VERSION 5.8 ;
BUSBITCHARS "[]" ;
DIVIDERCHAR "/" ;
UNITS
    DATABASE MICRONS 1000 ;
END UNITS

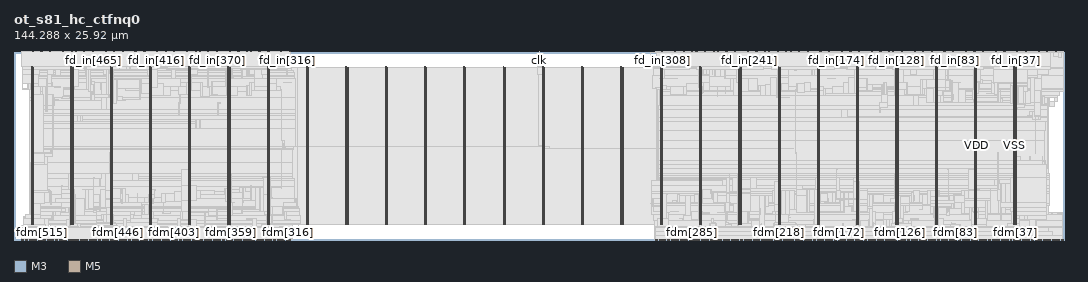
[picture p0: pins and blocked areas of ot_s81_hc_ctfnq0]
MACRO ot_s81_hc_ctfnq0
  FOREIGN ot_s81_hc_ctfnq0 0 0 ;
  CLASS BLOCK ;
  SIZE 144.288 BY 25.92 ;
  PIN clk
    DIRECTION INPUT ;
    USE SIGNAL ;
    PORT
      LAYER M3 ;
        RECT  72.144 25.882 72.162 25.92 ;
    END
  END clk
  PIN fd_in[0]
    DIRECTION INPUT ;
    USE SIGNAL ;
    PORT
      LAYER M5 ;
        RECT  144.24 25.836 144.264 25.92 ;
    END
  END fd_in[0]
  PIN fd_in[100]
    DIRECTION INPUT ;
    USE SIGNAL ;
    PORT
      LAYER M5 ;
        RECT  126.336 25.836 126.36 25.92 ;
    END
  END fd_in[100]
  PIN fd_in[101]
    DIRECTION INPUT ;
    USE SIGNAL ;
    PORT
      LAYER M5 ;
        RECT  126.144 25.836 126.168 25.92 ;
    END
  END fd_in[101]
  PIN fd_in[102]
    DIRECTION INPUT ;
    USE SIGNAL ;
    PORT
      LAYER M5 ;
        RECT  125.952 25.836 125.976 25.92 ;
    END
  END fd_in[102]
  PIN fd_in[103]
    DIRECTION INPUT ;
    USE SIGNAL ;
    PORT
      LAYER M5 ;
        RECT  125.808 25.836 125.832 25.92 ;
    END
  END fd_in[103]
  PIN fd_in[104]
    DIRECTION INPUT ;
    USE SIGNAL ;
    PORT
      LAYER M5 ;
        RECT  125.616 25.836 125.64 25.92 ;
    END
  END fd_in[104]
  PIN fd_in[105]
    DIRECTION INPUT ;
    USE SIGNAL ;
    PORT
      LAYER M5 ;
        RECT  125.424 25.836 125.448 25.92 ;
    END
  END fd_in[105]
  PIN fd_in[106]
    DIRECTION INPUT ;
    USE SIGNAL ;
    PORT
      LAYER M5 ;
        RECT  125.232 25.836 125.256 25.92 ;
    END
  END fd_in[106]
  PIN fd_in[107]
    DIRECTION INPUT ;
    USE SIGNAL ;
    PORT
      LAYER M5 ;
        RECT  125.088 25.836 125.112 25.92 ;
    END
  END fd_in[107]
  PIN fd_in[108]
    DIRECTION INPUT ;
    USE SIGNAL ;
    PORT
      LAYER M5 ;
        RECT  124.896 25.836 124.92 25.92 ;
    END
  END fd_in[108]
  PIN fd_in[109]
    DIRECTION INPUT ;
    USE SIGNAL ;
    PORT
      LAYER M5 ;
        RECT  124.704 25.836 124.728 25.92 ;
    END
  END fd_in[109]
  PIN fd_in[10]
    DIRECTION INPUT ;
    USE SIGNAL ;
    PORT
      LAYER M5 ;
        RECT  142.464 25.836 142.488 25.92 ;
    END
  END fd_in[10]
  PIN fd_in[110]
    DIRECTION INPUT ;
    USE SIGNAL ;
    PORT
      LAYER M5 ;
        RECT  124.512 25.836 124.536 25.92 ;
    END
  END fd_in[110]
  PIN fd_in[111]
    DIRECTION INPUT ;
    USE SIGNAL ;
    PORT
      LAYER M5 ;
        RECT  124.368 25.836 124.392 25.92 ;
    END
  END fd_in[111]
  PIN fd_in[112]
    DIRECTION INPUT ;
    USE SIGNAL ;
    PORT
      LAYER M5 ;
        RECT  124.176 25.836 124.2 25.92 ;
    END
  END fd_in[112]
  PIN fd_in[113]
    DIRECTION INPUT ;
    USE SIGNAL ;
    PORT
      LAYER M5 ;
        RECT  123.984 25.836 124.008 25.92 ;
    END
  END fd_in[113]
  PIN fd_in[114]
    DIRECTION INPUT ;
    USE SIGNAL ;
    PORT
      LAYER M5 ;
        RECT  123.792 25.836 123.816 25.92 ;
    END
  END fd_in[114]
  PIN fd_in[115]
    DIRECTION INPUT ;
    USE SIGNAL ;
    PORT
      LAYER M5 ;
        RECT  123.648 25.836 123.672 25.92 ;
    END
  END fd_in[115]
  PIN fd_in[116]
    DIRECTION INPUT ;
    USE SIGNAL ;
    PORT
      LAYER M5 ;
        RECT  123.456 25.836 123.48 25.92 ;
    END
  END fd_in[116]
  PIN fd_in[117]
    DIRECTION INPUT ;
    USE SIGNAL ;
    PORT
      LAYER M5 ;
        RECT  123.264 25.836 123.288 25.92 ;
    END
  END fd_in[117]
  PIN fd_in[118]
    DIRECTION INPUT ;
    USE SIGNAL ;
    PORT
      LAYER M5 ;
        RECT  123.072 25.836 123.096 25.92 ;
    END
  END fd_in[118]
  PIN fd_in[119]
    DIRECTION INPUT ;
    USE SIGNAL ;
    PORT
      LAYER M5 ;
        RECT  122.928 25.836 122.952 25.92 ;
    END
  END fd_in[119]
  PIN fd_in[11]
    DIRECTION INPUT ;
    USE SIGNAL ;
    PORT
      LAYER M5 ;
        RECT  142.272 25.836 142.296 25.92 ;
    END
  END fd_in[11]
  PIN fd_in[120]
    DIRECTION INPUT ;
    USE SIGNAL ;
    PORT
      LAYER M5 ;
        RECT  122.736 25.836 122.76 25.92 ;
    END
  END fd_in[120]
  PIN fd_in[121]
    DIRECTION INPUT ;
    USE SIGNAL ;
    PORT
      LAYER M5 ;
        RECT  122.544 25.836 122.568 25.92 ;
    END
  END fd_in[121]
  PIN fd_in[122]
    DIRECTION INPUT ;
    USE SIGNAL ;
    PORT
      LAYER M5 ;
        RECT  122.4 25.836 122.424 25.92 ;
    END
  END fd_in[122]
  PIN fd_in[123]
    DIRECTION INPUT ;
    USE SIGNAL ;
    PORT
      LAYER M5 ;
        RECT  122.208 25.836 122.232 25.92 ;
    END
  END fd_in[123]
  PIN fd_in[124]
    DIRECTION INPUT ;
    USE SIGNAL ;
    PORT
      LAYER M5 ;
        RECT  122.016 25.836 122.04 25.92 ;
    END
  END fd_in[124]
  PIN fd_in[125]
    DIRECTION INPUT ;
    USE SIGNAL ;
    PORT
      LAYER M5 ;
        RECT  121.824 25.836 121.848 25.92 ;
    END
  END fd_in[125]
  PIN fd_in[126]
    DIRECTION INPUT ;
    USE SIGNAL ;
    PORT
      LAYER M5 ;
        RECT  121.68 25.836 121.704 25.92 ;
    END
  END fd_in[126]
  PIN fd_in[127]
    DIRECTION INPUT ;
    USE SIGNAL ;
    PORT
      LAYER M5 ;
        RECT  121.488 25.836 121.512 25.92 ;
    END
  END fd_in[127]
  PIN fd_in[128]
    DIRECTION INPUT ;
    USE SIGNAL ;
    PORT
      LAYER M5 ;
        RECT  121.296 25.836 121.32 25.92 ;
    END
  END fd_in[128]
  PIN fd_in[129]
    DIRECTION INPUT ;
    USE SIGNAL ;
    PORT
      LAYER M5 ;
        RECT  121.104 25.836 121.128 25.92 ;
    END
  END fd_in[129]
  PIN fd_in[12]
    DIRECTION INPUT ;
    USE SIGNAL ;
    PORT
      LAYER M5 ;
        RECT  142.128 25.836 142.152 25.92 ;
    END
  END fd_in[12]
  PIN fd_in[130]
    DIRECTION INPUT ;
    USE SIGNAL ;
    PORT
      LAYER M5 ;
        RECT  120.96 25.836 120.984 25.92 ;
    END
  END fd_in[130]
  PIN fd_in[131]
    DIRECTION INPUT ;
    USE SIGNAL ;
    PORT
      LAYER M5 ;
        RECT  120.768 25.836 120.792 25.92 ;
    END
  END fd_in[131]
  PIN fd_in[132]
    DIRECTION INPUT ;
    USE SIGNAL ;
    PORT
      LAYER M5 ;
        RECT  120.576 25.836 120.6 25.92 ;
    END
  END fd_in[132]
  PIN fd_in[133]
    DIRECTION INPUT ;
    USE SIGNAL ;
    PORT
      LAYER M5 ;
        RECT  120.384 25.836 120.408 25.92 ;
    END
  END fd_in[133]
  PIN fd_in[134]
    DIRECTION INPUT ;
    USE SIGNAL ;
    PORT
      LAYER M5 ;
        RECT  120.24 25.836 120.264 25.92 ;
    END
  END fd_in[134]
  PIN fd_in[135]
    DIRECTION INPUT ;
    USE SIGNAL ;
    PORT
      LAYER M5 ;
        RECT  120.048 25.836 120.072 25.92 ;
    END
  END fd_in[135]
  PIN fd_in[136]
    DIRECTION INPUT ;
    USE SIGNAL ;
    PORT
      LAYER M5 ;
        RECT  119.856 25.836 119.88 25.92 ;
    END
  END fd_in[136]
  PIN fd_in[137]
    DIRECTION INPUT ;
    USE SIGNAL ;
    PORT
      LAYER M5 ;
        RECT  119.712 25.836 119.736 25.92 ;
    END
  END fd_in[137]
  PIN fd_in[138]
    DIRECTION INPUT ;
    USE SIGNAL ;
    PORT
      LAYER M5 ;
        RECT  119.52 25.836 119.544 25.92 ;
    END
  END fd_in[138]
  PIN fd_in[139]
    DIRECTION INPUT ;
    USE SIGNAL ;
    PORT
      LAYER M5 ;
        RECT  119.328 25.836 119.352 25.92 ;
    END
  END fd_in[139]
  PIN fd_in[13]
    DIRECTION INPUT ;
    USE SIGNAL ;
    PORT
      LAYER M5 ;
        RECT  141.936 25.836 141.96 25.92 ;
    END
  END fd_in[13]
  PIN fd_in[140]
    DIRECTION INPUT ;
    USE SIGNAL ;
    PORT
      LAYER M5 ;
        RECT  119.136 25.836 119.16 25.92 ;
    END
  END fd_in[140]
  PIN fd_in[141]
    DIRECTION INPUT ;
    USE SIGNAL ;
    PORT
      LAYER M5 ;
        RECT  118.992 25.836 119.016 25.92 ;
    END
  END fd_in[141]
  PIN fd_in[142]
    DIRECTION INPUT ;
    USE SIGNAL ;
    PORT
      LAYER M5 ;
        RECT  118.8 25.836 118.824 25.92 ;
    END
  END fd_in[142]
  PIN fd_in[143]
    DIRECTION INPUT ;
    USE SIGNAL ;
    PORT
      LAYER M5 ;
        RECT  118.608 25.836 118.632 25.92 ;
    END
  END fd_in[143]
  PIN fd_in[144]
    DIRECTION INPUT ;
    USE SIGNAL ;
    PORT
      LAYER M5 ;
        RECT  118.416 25.836 118.44 25.92 ;
    END
  END fd_in[144]
  PIN fd_in[145]
    DIRECTION INPUT ;
    USE SIGNAL ;
    PORT
      LAYER M5 ;
        RECT  118.272 25.836 118.296 25.92 ;
    END
  END fd_in[145]
  PIN fd_in[146]
    DIRECTION INPUT ;
    USE SIGNAL ;
    PORT
      LAYER M5 ;
        RECT  118.08 25.836 118.104 25.92 ;
    END
  END fd_in[146]
  PIN fd_in[147]
    DIRECTION INPUT ;
    USE SIGNAL ;
    PORT
      LAYER M5 ;
        RECT  117.888 25.836 117.912 25.92 ;
    END
  END fd_in[147]
  PIN fd_in[148]
    DIRECTION INPUT ;
    USE SIGNAL ;
    PORT
      LAYER M5 ;
        RECT  117.696 25.836 117.72 25.92 ;
    END
  END fd_in[148]
  PIN fd_in[149]
    DIRECTION INPUT ;
    USE SIGNAL ;
    PORT
      LAYER M5 ;
        RECT  117.552 25.836 117.576 25.92 ;
    END
  END fd_in[149]
  PIN fd_in[14]
    DIRECTION INPUT ;
    USE SIGNAL ;
    PORT
      LAYER M5 ;
        RECT  141.744 25.836 141.768 25.92 ;
    END
  END fd_in[14]
  PIN fd_in[150]
    DIRECTION INPUT ;
    USE SIGNAL ;
    PORT
      LAYER M5 ;
        RECT  117.36 25.836 117.384 25.92 ;
    END
  END fd_in[150]
  PIN fd_in[151]
    DIRECTION INPUT ;
    USE SIGNAL ;
    PORT
      LAYER M5 ;
        RECT  117.168 25.836 117.192 25.92 ;
    END
  END fd_in[151]
  PIN fd_in[152]
    DIRECTION INPUT ;
    USE SIGNAL ;
    PORT
      LAYER M5 ;
        RECT  116.976 25.836 117 25.92 ;
    END
  END fd_in[152]
  PIN fd_in[153]
    DIRECTION INPUT ;
    USE SIGNAL ;
    PORT
      LAYER M5 ;
        RECT  116.832 25.836 116.856 25.92 ;
    END
  END fd_in[153]
  PIN fd_in[154]
    DIRECTION INPUT ;
    USE SIGNAL ;
    PORT
      LAYER M5 ;
        RECT  116.64 25.836 116.664 25.92 ;
    END
  END fd_in[154]
  PIN fd_in[155]
    DIRECTION INPUT ;
    USE SIGNAL ;
    PORT
      LAYER M5 ;
        RECT  116.448 25.836 116.472 25.92 ;
    END
  END fd_in[155]
  PIN fd_in[156]
    DIRECTION INPUT ;
    USE SIGNAL ;
    PORT
      LAYER M5 ;
        RECT  116.304 25.836 116.328 25.92 ;
    END
  END fd_in[156]
  PIN fd_in[157]
    DIRECTION INPUT ;
    USE SIGNAL ;
    PORT
      LAYER M5 ;
        RECT  116.112 25.836 116.136 25.92 ;
    END
  END fd_in[157]
  PIN fd_in[158]
    DIRECTION INPUT ;
    USE SIGNAL ;
    PORT
      LAYER M5 ;
        RECT  115.92 25.836 115.944 25.92 ;
    END
  END fd_in[158]
  PIN fd_in[159]
    DIRECTION INPUT ;
    USE SIGNAL ;
    PORT
      LAYER M5 ;
        RECT  115.728 25.836 115.752 25.92 ;
    END
  END fd_in[159]
  PIN fd_in[15]
    DIRECTION INPUT ;
    USE SIGNAL ;
    PORT
      LAYER M5 ;
        RECT  141.552 25.836 141.576 25.92 ;
    END
  END fd_in[15]
  PIN fd_in[160]
    DIRECTION INPUT ;
    USE SIGNAL ;
    PORT
      LAYER M5 ;
        RECT  115.584 25.836 115.608 25.92 ;
    END
  END fd_in[160]
  PIN fd_in[161]
    DIRECTION INPUT ;
    USE SIGNAL ;
    PORT
      LAYER M5 ;
        RECT  115.392 25.836 115.416 25.92 ;
    END
  END fd_in[161]
  PIN fd_in[162]
    DIRECTION INPUT ;
    USE SIGNAL ;
    PORT
      LAYER M5 ;
        RECT  115.2 25.836 115.224 25.92 ;
    END
  END fd_in[162]
  PIN fd_in[163]
    DIRECTION INPUT ;
    USE SIGNAL ;
    PORT
      LAYER M5 ;
        RECT  115.008 25.836 115.032 25.92 ;
    END
  END fd_in[163]
  PIN fd_in[164]
    DIRECTION INPUT ;
    USE SIGNAL ;
    PORT
      LAYER M5 ;
        RECT  114.864 25.836 114.888 25.92 ;
    END
  END fd_in[164]
  PIN fd_in[165]
    DIRECTION INPUT ;
    USE SIGNAL ;
    PORT
      LAYER M5 ;
        RECT  114.672 25.836 114.696 25.92 ;
    END
  END fd_in[165]
  PIN fd_in[166]
    DIRECTION INPUT ;
    USE SIGNAL ;
    PORT
      LAYER M5 ;
        RECT  114.48 25.836 114.504 25.92 ;
    END
  END fd_in[166]
  PIN fd_in[167]
    DIRECTION INPUT ;
    USE SIGNAL ;
    PORT
      LAYER M5 ;
        RECT  114.288 25.836 114.312 25.92 ;
    END
  END fd_in[167]
  PIN fd_in[168]
    DIRECTION INPUT ;
    USE SIGNAL ;
    PORT
      LAYER M5 ;
        RECT  114.144 25.836 114.168 25.92 ;
    END
  END fd_in[168]
  PIN fd_in[169]
    DIRECTION INPUT ;
    USE SIGNAL ;
    PORT
      LAYER M5 ;
        RECT  113.952 25.836 113.976 25.92 ;
    END
  END fd_in[169]
  PIN fd_in[16]
    DIRECTION INPUT ;
    USE SIGNAL ;
    PORT
      LAYER M5 ;
        RECT  141.408 25.836 141.432 25.92 ;
    END
  END fd_in[16]
  PIN fd_in[170]
    DIRECTION INPUT ;
    USE SIGNAL ;
    PORT
      LAYER M5 ;
        RECT  113.76 25.836 113.784 25.92 ;
    END
  END fd_in[170]
  PIN fd_in[171]
    DIRECTION INPUT ;
    USE SIGNAL ;
    PORT
      LAYER M5 ;
        RECT  113.568 25.836 113.592 25.92 ;
    END
  END fd_in[171]
  PIN fd_in[172]
    DIRECTION INPUT ;
    USE SIGNAL ;
    PORT
      LAYER M5 ;
        RECT  113.424 25.836 113.448 25.92 ;
    END
  END fd_in[172]
  PIN fd_in[173]
    DIRECTION INPUT ;
    USE SIGNAL ;
    PORT
      LAYER M5 ;
        RECT  113.232 25.836 113.256 25.92 ;
    END
  END fd_in[173]
  PIN fd_in[174]
    DIRECTION INPUT ;
    USE SIGNAL ;
    PORT
      LAYER M5 ;
        RECT  113.04 25.836 113.064 25.92 ;
    END
  END fd_in[174]
  PIN fd_in[175]
    DIRECTION INPUT ;
    USE SIGNAL ;
    PORT
      LAYER M5 ;
        RECT  112.896 25.836 112.92 25.92 ;
    END
  END fd_in[175]
  PIN fd_in[176]
    DIRECTION INPUT ;
    USE SIGNAL ;
    PORT
      LAYER M5 ;
        RECT  112.704 25.836 112.728 25.92 ;
    END
  END fd_in[176]
  PIN fd_in[177]
    DIRECTION INPUT ;
    USE SIGNAL ;
    PORT
      LAYER M5 ;
        RECT  112.512 25.836 112.536 25.92 ;
    END
  END fd_in[177]
  PIN fd_in[178]
    DIRECTION INPUT ;
    USE SIGNAL ;
    PORT
      LAYER M5 ;
        RECT  112.32 25.836 112.344 25.92 ;
    END
  END fd_in[178]
  PIN fd_in[179]
    DIRECTION INPUT ;
    USE SIGNAL ;
    PORT
      LAYER M5 ;
        RECT  112.176 25.836 112.2 25.92 ;
    END
  END fd_in[179]
  PIN fd_in[17]
    DIRECTION INPUT ;
    USE SIGNAL ;
    PORT
      LAYER M5 ;
        RECT  141.216 25.836 141.24 25.92 ;
    END
  END fd_in[17]
  PIN fd_in[180]
    DIRECTION INPUT ;
    USE SIGNAL ;
    PORT
      LAYER M5 ;
        RECT  111.984 25.836 112.008 25.92 ;
    END
  END fd_in[180]
  PIN fd_in[181]
    DIRECTION INPUT ;
    USE SIGNAL ;
    PORT
      LAYER M5 ;
        RECT  111.792 25.836 111.816 25.92 ;
    END
  END fd_in[181]
  PIN fd_in[182]
    DIRECTION INPUT ;
    USE SIGNAL ;
    PORT
      LAYER M5 ;
        RECT  111.6 25.836 111.624 25.92 ;
    END
  END fd_in[182]
  PIN fd_in[183]
    DIRECTION INPUT ;
    USE SIGNAL ;
    PORT
      LAYER M5 ;
        RECT  111.456 25.836 111.48 25.92 ;
    END
  END fd_in[183]
  PIN fd_in[184]
    DIRECTION INPUT ;
    USE SIGNAL ;
    PORT
      LAYER M5 ;
        RECT  111.264 25.836 111.288 25.92 ;
    END
  END fd_in[184]
  PIN fd_in[185]
    DIRECTION INPUT ;
    USE SIGNAL ;
    PORT
      LAYER M5 ;
        RECT  111.072 25.836 111.096 25.92 ;
    END
  END fd_in[185]
  PIN fd_in[186]
    DIRECTION INPUT ;
    USE SIGNAL ;
    PORT
      LAYER M5 ;
        RECT  110.88 25.836 110.904 25.92 ;
    END
  END fd_in[186]
  PIN fd_in[187]
    DIRECTION INPUT ;
    USE SIGNAL ;
    PORT
      LAYER M5 ;
        RECT  110.736 25.836 110.76 25.92 ;
    END
  END fd_in[187]
  PIN fd_in[188]
    DIRECTION INPUT ;
    USE SIGNAL ;
    PORT
      LAYER M5 ;
        RECT  110.544 25.836 110.568 25.92 ;
    END
  END fd_in[188]
  PIN fd_in[189]
    DIRECTION INPUT ;
    USE SIGNAL ;
    PORT
      LAYER M5 ;
        RECT  110.352 25.836 110.376 25.92 ;
    END
  END fd_in[189]
  PIN fd_in[18]
    DIRECTION INPUT ;
    USE SIGNAL ;
    PORT
      LAYER M5 ;
        RECT  141.024 25.836 141.048 25.92 ;
    END
  END fd_in[18]
  PIN fd_in[190]
    DIRECTION INPUT ;
    USE SIGNAL ;
    PORT
      LAYER M5 ;
        RECT  110.16 25.836 110.184 25.92 ;
    END
  END fd_in[190]
  PIN fd_in[191]
    DIRECTION INPUT ;
    USE SIGNAL ;
    PORT
      LAYER M5 ;
        RECT  110.016 25.836 110.04 25.92 ;
    END
  END fd_in[191]
  PIN fd_in[192]
    DIRECTION INPUT ;
    USE SIGNAL ;
    PORT
      LAYER M5 ;
        RECT  109.824 25.836 109.848 25.92 ;
    END
  END fd_in[192]
  PIN fd_in[193]
    DIRECTION INPUT ;
    USE SIGNAL ;
    PORT
      LAYER M5 ;
        RECT  109.632 25.836 109.656 25.92 ;
    END
  END fd_in[193]
  PIN fd_in[194]
    DIRECTION INPUT ;
    USE SIGNAL ;
    PORT
      LAYER M5 ;
        RECT  109.488 25.836 109.512 25.92 ;
    END
  END fd_in[194]
  PIN fd_in[195]
    DIRECTION INPUT ;
    USE SIGNAL ;
    PORT
      LAYER M5 ;
        RECT  109.296 25.836 109.32 25.92 ;
    END
  END fd_in[195]
  PIN fd_in[196]
    DIRECTION INPUT ;
    USE SIGNAL ;
    PORT
      LAYER M5 ;
        RECT  109.104 25.836 109.128 25.92 ;
    END
  END fd_in[196]
  PIN fd_in[197]
    DIRECTION INPUT ;
    USE SIGNAL ;
    PORT
      LAYER M5 ;
        RECT  108.912 25.836 108.936 25.92 ;
    END
  END fd_in[197]
  PIN fd_in[198]
    DIRECTION INPUT ;
    USE SIGNAL ;
    PORT
      LAYER M5 ;
        RECT  108.768 25.836 108.792 25.92 ;
    END
  END fd_in[198]
  PIN fd_in[199]
    DIRECTION INPUT ;
    USE SIGNAL ;
    PORT
      LAYER M5 ;
        RECT  108.576 25.836 108.6 25.92 ;
    END
  END fd_in[199]
  PIN fd_in[19]
    DIRECTION INPUT ;
    USE SIGNAL ;
    PORT
      LAYER M5 ;
        RECT  140.832 25.836 140.856 25.92 ;
    END
  END fd_in[19]
  PIN fd_in[1]
    DIRECTION INPUT ;
    USE SIGNAL ;
    PORT
      LAYER M5 ;
        RECT  144.096 25.836 144.12 25.92 ;
    END
  END fd_in[1]
  PIN fd_in[200]
    DIRECTION INPUT ;
    USE SIGNAL ;
    PORT
      LAYER M5 ;
        RECT  108.384 25.836 108.408 25.92 ;
    END
  END fd_in[200]
  PIN fd_in[201]
    DIRECTION INPUT ;
    USE SIGNAL ;
    PORT
      LAYER M5 ;
        RECT  108.192 25.836 108.216 25.92 ;
    END
  END fd_in[201]
  PIN fd_in[202]
    DIRECTION INPUT ;
    USE SIGNAL ;
    PORT
      LAYER M5 ;
        RECT  108.048 25.836 108.072 25.92 ;
    END
  END fd_in[202]
  PIN fd_in[203]
    DIRECTION INPUT ;
    USE SIGNAL ;
    PORT
      LAYER M5 ;
        RECT  107.856 25.836 107.88 25.92 ;
    END
  END fd_in[203]
  PIN fd_in[204]
    DIRECTION INPUT ;
    USE SIGNAL ;
    PORT
      LAYER M5 ;
        RECT  107.664 25.836 107.688 25.92 ;
    END
  END fd_in[204]
  PIN fd_in[205]
    DIRECTION INPUT ;
    USE SIGNAL ;
    PORT
      LAYER M5 ;
        RECT  107.472 25.836 107.496 25.92 ;
    END
  END fd_in[205]
  PIN fd_in[206]
    DIRECTION INPUT ;
    USE SIGNAL ;
    PORT
      LAYER M5 ;
        RECT  107.328 25.836 107.352 25.92 ;
    END
  END fd_in[206]
  PIN fd_in[207]
    DIRECTION INPUT ;
    USE SIGNAL ;
    PORT
      LAYER M5 ;
        RECT  107.136 25.836 107.16 25.92 ;
    END
  END fd_in[207]
  PIN fd_in[208]
    DIRECTION INPUT ;
    USE SIGNAL ;
    PORT
      LAYER M5 ;
        RECT  106.944 25.836 106.968 25.92 ;
    END
  END fd_in[208]
  PIN fd_in[209]
    DIRECTION INPUT ;
    USE SIGNAL ;
    PORT
      LAYER M5 ;
        RECT  106.752 25.836 106.776 25.92 ;
    END
  END fd_in[209]
  PIN fd_in[20]
    DIRECTION INPUT ;
    USE SIGNAL ;
    PORT
      LAYER M5 ;
        RECT  140.688 25.836 140.712 25.92 ;
    END
  END fd_in[20]
  PIN fd_in[210]
    DIRECTION INPUT ;
    USE SIGNAL ;
    PORT
      LAYER M5 ;
        RECT  106.608 25.836 106.632 25.92 ;
    END
  END fd_in[210]
  PIN fd_in[211]
    DIRECTION INPUT ;
    USE SIGNAL ;
    PORT
      LAYER M5 ;
        RECT  106.416 25.836 106.44 25.92 ;
    END
  END fd_in[211]
  PIN fd_in[212]
    DIRECTION INPUT ;
    USE SIGNAL ;
    PORT
      LAYER M5 ;
        RECT  106.224 25.836 106.248 25.92 ;
    END
  END fd_in[212]
  PIN fd_in[213]
    DIRECTION INPUT ;
    USE SIGNAL ;
    PORT
      LAYER M5 ;
        RECT  106.08 25.836 106.104 25.92 ;
    END
  END fd_in[213]
  PIN fd_in[214]
    DIRECTION INPUT ;
    USE SIGNAL ;
    PORT
      LAYER M5 ;
        RECT  105.888 25.836 105.912 25.92 ;
    END
  END fd_in[214]
  PIN fd_in[215]
    DIRECTION INPUT ;
    USE SIGNAL ;
    PORT
      LAYER M5 ;
        RECT  105.696 25.836 105.72 25.92 ;
    END
  END fd_in[215]
  PIN fd_in[216]
    DIRECTION INPUT ;
    USE SIGNAL ;
    PORT
      LAYER M5 ;
        RECT  105.504 25.836 105.528 25.92 ;
    END
  END fd_in[216]
  PIN fd_in[217]
    DIRECTION INPUT ;
    USE SIGNAL ;
    PORT
      LAYER M5 ;
        RECT  105.36 25.836 105.384 25.92 ;
    END
  END fd_in[217]
  PIN fd_in[218]
    DIRECTION INPUT ;
    USE SIGNAL ;
    PORT
      LAYER M5 ;
        RECT  105.168 25.836 105.192 25.92 ;
    END
  END fd_in[218]
  PIN fd_in[219]
    DIRECTION INPUT ;
    USE SIGNAL ;
    PORT
      LAYER M5 ;
        RECT  104.976 25.836 105 25.92 ;
    END
  END fd_in[219]
  PIN fd_in[21]
    DIRECTION INPUT ;
    USE SIGNAL ;
    PORT
      LAYER M5 ;
        RECT  140.496 25.836 140.52 25.92 ;
    END
  END fd_in[21]
  PIN fd_in[220]
    DIRECTION INPUT ;
    USE SIGNAL ;
    PORT
      LAYER M5 ;
        RECT  104.784 25.836 104.808 25.92 ;
    END
  END fd_in[220]
  PIN fd_in[221]
    DIRECTION INPUT ;
    USE SIGNAL ;
    PORT
      LAYER M5 ;
        RECT  104.64 25.836 104.664 25.92 ;
    END
  END fd_in[221]
  PIN fd_in[222]
    DIRECTION INPUT ;
    USE SIGNAL ;
    PORT
      LAYER M5 ;
        RECT  104.448 25.836 104.472 25.92 ;
    END
  END fd_in[222]
  PIN fd_in[223]
    DIRECTION INPUT ;
    USE SIGNAL ;
    PORT
      LAYER M5 ;
        RECT  104.256 25.836 104.28 25.92 ;
    END
  END fd_in[223]
  PIN fd_in[224]
    DIRECTION INPUT ;
    USE SIGNAL ;
    PORT
      LAYER M5 ;
        RECT  104.064 25.836 104.088 25.92 ;
    END
  END fd_in[224]
  PIN fd_in[225]
    DIRECTION INPUT ;
    USE SIGNAL ;
    PORT
      LAYER M5 ;
        RECT  103.92 25.836 103.944 25.92 ;
    END
  END fd_in[225]
  PIN fd_in[226]
    DIRECTION INPUT ;
    USE SIGNAL ;
    PORT
      LAYER M5 ;
        RECT  103.728 25.836 103.752 25.92 ;
    END
  END fd_in[226]
  PIN fd_in[227]
    DIRECTION INPUT ;
    USE SIGNAL ;
    PORT
      LAYER M5 ;
        RECT  103.536 25.836 103.56 25.92 ;
    END
  END fd_in[227]
  PIN fd_in[228]
    DIRECTION INPUT ;
    USE SIGNAL ;
    PORT
      LAYER M5 ;
        RECT  103.392 25.836 103.416 25.92 ;
    END
  END fd_in[228]
  PIN fd_in[229]
    DIRECTION INPUT ;
    USE SIGNAL ;
    PORT
      LAYER M5 ;
        RECT  103.2 25.836 103.224 25.92 ;
    END
  END fd_in[229]
  PIN fd_in[22]
    DIRECTION INPUT ;
    USE SIGNAL ;
    PORT
      LAYER M5 ;
        RECT  140.304 25.836 140.328 25.92 ;
    END
  END fd_in[22]
  PIN fd_in[230]
    DIRECTION INPUT ;
    USE SIGNAL ;
    PORT
      LAYER M5 ;
        RECT  103.008 25.836 103.032 25.92 ;
    END
  END fd_in[230]
  PIN fd_in[231]
    DIRECTION INPUT ;
    USE SIGNAL ;
    PORT
      LAYER M5 ;
        RECT  102.816 25.836 102.84 25.92 ;
    END
  END fd_in[231]
  PIN fd_in[232]
    DIRECTION INPUT ;
    USE SIGNAL ;
    PORT
      LAYER M5 ;
        RECT  102.672 25.836 102.696 25.92 ;
    END
  END fd_in[232]
  PIN fd_in[233]
    DIRECTION INPUT ;
    USE SIGNAL ;
    PORT
      LAYER M5 ;
        RECT  102.48 25.836 102.504 25.92 ;
    END
  END fd_in[233]
  PIN fd_in[234]
    DIRECTION INPUT ;
    USE SIGNAL ;
    PORT
      LAYER M5 ;
        RECT  102.288 25.836 102.312 25.92 ;
    END
  END fd_in[234]
  PIN fd_in[235]
    DIRECTION INPUT ;
    USE SIGNAL ;
    PORT
      LAYER M5 ;
        RECT  102.096 25.836 102.12 25.92 ;
    END
  END fd_in[235]
  PIN fd_in[236]
    DIRECTION INPUT ;
    USE SIGNAL ;
    PORT
      LAYER M5 ;
        RECT  101.952 25.836 101.976 25.92 ;
    END
  END fd_in[236]
  PIN fd_in[237]
    DIRECTION INPUT ;
    USE SIGNAL ;
    PORT
      LAYER M5 ;
        RECT  101.76 25.836 101.784 25.92 ;
    END
  END fd_in[237]
  PIN fd_in[238]
    DIRECTION INPUT ;
    USE SIGNAL ;
    PORT
      LAYER M5 ;
        RECT  101.568 25.836 101.592 25.92 ;
    END
  END fd_in[238]
  PIN fd_in[239]
    DIRECTION INPUT ;
    USE SIGNAL ;
    PORT
      LAYER M5 ;
        RECT  101.376 25.836 101.4 25.92 ;
    END
  END fd_in[239]
  PIN fd_in[23]
    DIRECTION INPUT ;
    USE SIGNAL ;
    PORT
      LAYER M5 ;
        RECT  140.112 25.836 140.136 25.92 ;
    END
  END fd_in[23]
  PIN fd_in[240]
    DIRECTION INPUT ;
    USE SIGNAL ;
    PORT
      LAYER M5 ;
        RECT  101.232 25.836 101.256 25.92 ;
    END
  END fd_in[240]
  PIN fd_in[241]
    DIRECTION INPUT ;
    USE SIGNAL ;
    PORT
      LAYER M5 ;
        RECT  101.04 25.836 101.064 25.92 ;
    END
  END fd_in[241]
  PIN fd_in[242]
    DIRECTION INPUT ;
    USE SIGNAL ;
    PORT
      LAYER M5 ;
        RECT  100.848 25.836 100.872 25.92 ;
    END
  END fd_in[242]
  PIN fd_in[243]
    DIRECTION INPUT ;
    USE SIGNAL ;
    PORT
      LAYER M5 ;
        RECT  100.656 25.836 100.68 25.92 ;
    END
  END fd_in[243]
  PIN fd_in[244]
    DIRECTION INPUT ;
    USE SIGNAL ;
    PORT
      LAYER M5 ;
        RECT  100.512 25.836 100.536 25.92 ;
    END
  END fd_in[244]
  PIN fd_in[245]
    DIRECTION INPUT ;
    USE SIGNAL ;
    PORT
      LAYER M5 ;
        RECT  100.32 25.836 100.344 25.92 ;
    END
  END fd_in[245]
  PIN fd_in[246]
    DIRECTION INPUT ;
    USE SIGNAL ;
    PORT
      LAYER M5 ;
        RECT  100.128 25.836 100.152 25.92 ;
    END
  END fd_in[246]
  PIN fd_in[247]
    DIRECTION INPUT ;
    USE SIGNAL ;
    PORT
      LAYER M5 ;
        RECT  99.984 25.836 100.008 25.92 ;
    END
  END fd_in[247]
  PIN fd_in[248]
    DIRECTION INPUT ;
    USE SIGNAL ;
    PORT
      LAYER M5 ;
        RECT  99.792 25.836 99.816 25.92 ;
    END
  END fd_in[248]
  PIN fd_in[249]
    DIRECTION INPUT ;
    USE SIGNAL ;
    PORT
      LAYER M5 ;
        RECT  99.6 25.836 99.624 25.92 ;
    END
  END fd_in[249]
  PIN fd_in[24]
    DIRECTION INPUT ;
    USE SIGNAL ;
    PORT
      LAYER M5 ;
        RECT  139.968 25.836 139.992 25.92 ;
    END
  END fd_in[24]
  PIN fd_in[250]
    DIRECTION INPUT ;
    USE SIGNAL ;
    PORT
      LAYER M5 ;
        RECT  99.408 25.836 99.432 25.92 ;
    END
  END fd_in[250]
  PIN fd_in[251]
    DIRECTION INPUT ;
    USE SIGNAL ;
    PORT
      LAYER M5 ;
        RECT  99.264 25.836 99.288 25.92 ;
    END
  END fd_in[251]
  PIN fd_in[252]
    DIRECTION INPUT ;
    USE SIGNAL ;
    PORT
      LAYER M5 ;
        RECT  99.072 25.836 99.096 25.92 ;
    END
  END fd_in[252]
  PIN fd_in[253]
    DIRECTION INPUT ;
    USE SIGNAL ;
    PORT
      LAYER M5 ;
        RECT  98.88 25.836 98.904 25.92 ;
    END
  END fd_in[253]
  PIN fd_in[254]
    DIRECTION INPUT ;
    USE SIGNAL ;
    PORT
      LAYER M5 ;
        RECT  98.688 25.836 98.712 25.92 ;
    END
  END fd_in[254]
  PIN fd_in[255]
    DIRECTION INPUT ;
    USE SIGNAL ;
    PORT
      LAYER M5 ;
        RECT  98.544 25.836 98.568 25.92 ;
    END
  END fd_in[255]
  PIN fd_in[256]
    DIRECTION INPUT ;
    USE SIGNAL ;
    PORT
      LAYER M5 ;
        RECT  98.352 25.836 98.376 25.92 ;
    END
  END fd_in[256]
  PIN fd_in[257]
    DIRECTION INPUT ;
    USE SIGNAL ;
    PORT
      LAYER M5 ;
        RECT  98.16 25.836 98.184 25.92 ;
    END
  END fd_in[257]
  PIN fd_in[258]
    DIRECTION INPUT ;
    USE SIGNAL ;
    PORT
      LAYER M5 ;
        RECT  97.968 25.836 97.992 25.92 ;
    END
  END fd_in[258]
  PIN fd_in[259]
    DIRECTION INPUT ;
    USE SIGNAL ;
    PORT
      LAYER M5 ;
        RECT  97.824 25.836 97.848 25.92 ;
    END
  END fd_in[259]
  PIN fd_in[25]
    DIRECTION INPUT ;
    USE SIGNAL ;
    PORT
      LAYER M5 ;
        RECT  139.776 25.836 139.8 25.92 ;
    END
  END fd_in[25]
  PIN fd_in[260]
    DIRECTION INPUT ;
    USE SIGNAL ;
    PORT
      LAYER M5 ;
        RECT  97.632 25.836 97.656 25.92 ;
    END
  END fd_in[260]
  PIN fd_in[261]
    DIRECTION INPUT ;
    USE SIGNAL ;
    PORT
      LAYER M5 ;
        RECT  97.44 25.836 97.464 25.92 ;
    END
  END fd_in[261]
  PIN fd_in[262]
    DIRECTION INPUT ;
    USE SIGNAL ;
    PORT
      LAYER M5 ;
        RECT  97.248 25.836 97.272 25.92 ;
    END
  END fd_in[262]
  PIN fd_in[263]
    DIRECTION INPUT ;
    USE SIGNAL ;
    PORT
      LAYER M5 ;
        RECT  97.104 25.836 97.128 25.92 ;
    END
  END fd_in[263]
  PIN fd_in[264]
    DIRECTION INPUT ;
    USE SIGNAL ;
    PORT
      LAYER M5 ;
        RECT  96.912 25.836 96.936 25.92 ;
    END
  END fd_in[264]
  PIN fd_in[265]
    DIRECTION INPUT ;
    USE SIGNAL ;
    PORT
      LAYER M5 ;
        RECT  96.72 25.836 96.744 25.92 ;
    END
  END fd_in[265]
  PIN fd_in[266]
    DIRECTION INPUT ;
    USE SIGNAL ;
    PORT
      LAYER M5 ;
        RECT  96.576 25.836 96.6 25.92 ;
    END
  END fd_in[266]
  PIN fd_in[267]
    DIRECTION INPUT ;
    USE SIGNAL ;
    PORT
      LAYER M5 ;
        RECT  96.384 25.836 96.408 25.92 ;
    END
  END fd_in[267]
  PIN fd_in[268]
    DIRECTION INPUT ;
    USE SIGNAL ;
    PORT
      LAYER M5 ;
        RECT  96.192 25.836 96.216 25.92 ;
    END
  END fd_in[268]
  PIN fd_in[269]
    DIRECTION INPUT ;
    USE SIGNAL ;
    PORT
      LAYER M5 ;
        RECT  96 25.836 96.024 25.92 ;
    END
  END fd_in[269]
  PIN fd_in[26]
    DIRECTION INPUT ;
    USE SIGNAL ;
    PORT
      LAYER M5 ;
        RECT  139.584 25.836 139.608 25.92 ;
    END
  END fd_in[26]
  PIN fd_in[270]
    DIRECTION INPUT ;
    USE SIGNAL ;
    PORT
      LAYER M5 ;
        RECT  95.856 25.836 95.88 25.92 ;
    END
  END fd_in[270]
  PIN fd_in[271]
    DIRECTION INPUT ;
    USE SIGNAL ;
    PORT
      LAYER M5 ;
        RECT  95.664 25.836 95.688 25.92 ;
    END
  END fd_in[271]
  PIN fd_in[272]
    DIRECTION INPUT ;
    USE SIGNAL ;
    PORT
      LAYER M5 ;
        RECT  95.472 25.836 95.496 25.92 ;
    END
  END fd_in[272]
  PIN fd_in[273]
    DIRECTION INPUT ;
    USE SIGNAL ;
    PORT
      LAYER M5 ;
        RECT  95.28 25.836 95.304 25.92 ;
    END
  END fd_in[273]
  PIN fd_in[274]
    DIRECTION INPUT ;
    USE SIGNAL ;
    PORT
      LAYER M5 ;
        RECT  95.136 25.836 95.16 25.92 ;
    END
  END fd_in[274]
  PIN fd_in[275]
    DIRECTION INPUT ;
    USE SIGNAL ;
    PORT
      LAYER M5 ;
        RECT  94.944 25.836 94.968 25.92 ;
    END
  END fd_in[275]
  PIN fd_in[276]
    DIRECTION INPUT ;
    USE SIGNAL ;
    PORT
      LAYER M5 ;
        RECT  94.752 25.836 94.776 25.92 ;
    END
  END fd_in[276]
  PIN fd_in[277]
    DIRECTION INPUT ;
    USE SIGNAL ;
    PORT
      LAYER M5 ;
        RECT  94.56 25.836 94.584 25.92 ;
    END
  END fd_in[277]
  PIN fd_in[278]
    DIRECTION INPUT ;
    USE SIGNAL ;
    PORT
      LAYER M5 ;
        RECT  94.416 25.836 94.44 25.92 ;
    END
  END fd_in[278]
  PIN fd_in[279]
    DIRECTION INPUT ;
    USE SIGNAL ;
    PORT
      LAYER M5 ;
        RECT  94.224 25.836 94.248 25.92 ;
    END
  END fd_in[279]
  PIN fd_in[27]
    DIRECTION INPUT ;
    USE SIGNAL ;
    PORT
      LAYER M5 ;
        RECT  139.392 25.836 139.416 25.92 ;
    END
  END fd_in[27]
  PIN fd_in[280]
    DIRECTION INPUT ;
    USE SIGNAL ;
    PORT
      LAYER M5 ;
        RECT  94.032 25.836 94.056 25.92 ;
    END
  END fd_in[280]
  PIN fd_in[281]
    DIRECTION INPUT ;
    USE SIGNAL ;
    PORT
      LAYER M5 ;
        RECT  93.84 25.836 93.864 25.92 ;
    END
  END fd_in[281]
  PIN fd_in[282]
    DIRECTION INPUT ;
    USE SIGNAL ;
    PORT
      LAYER M5 ;
        RECT  93.696 25.836 93.72 25.92 ;
    END
  END fd_in[282]
  PIN fd_in[283]
    DIRECTION INPUT ;
    USE SIGNAL ;
    PORT
      LAYER M5 ;
        RECT  93.504 25.836 93.528 25.92 ;
    END
  END fd_in[283]
  PIN fd_in[284]
    DIRECTION INPUT ;
    USE SIGNAL ;
    PORT
      LAYER M5 ;
        RECT  93.312 25.836 93.336 25.92 ;
    END
  END fd_in[284]
  PIN fd_in[285]
    DIRECTION INPUT ;
    USE SIGNAL ;
    PORT
      LAYER M5 ;
        RECT  93.168 25.836 93.192 25.92 ;
    END
  END fd_in[285]
  PIN fd_in[286]
    DIRECTION INPUT ;
    USE SIGNAL ;
    PORT
      LAYER M5 ;
        RECT  92.976 25.836 93 25.92 ;
    END
  END fd_in[286]
  PIN fd_in[287]
    DIRECTION INPUT ;
    USE SIGNAL ;
    PORT
      LAYER M5 ;
        RECT  92.784 25.836 92.808 25.92 ;
    END
  END fd_in[287]
  PIN fd_in[288]
    DIRECTION INPUT ;
    USE SIGNAL ;
    PORT
      LAYER M5 ;
        RECT  92.592 25.836 92.616 25.92 ;
    END
  END fd_in[288]
  PIN fd_in[289]
    DIRECTION INPUT ;
    USE SIGNAL ;
    PORT
      LAYER M5 ;
        RECT  92.448 25.836 92.472 25.92 ;
    END
  END fd_in[289]
  PIN fd_in[28]
    DIRECTION INPUT ;
    USE SIGNAL ;
    PORT
      LAYER M5 ;
        RECT  139.248 25.836 139.272 25.92 ;
    END
  END fd_in[28]
  PIN fd_in[290]
    DIRECTION INPUT ;
    USE SIGNAL ;
    PORT
      LAYER M5 ;
        RECT  92.256 25.836 92.28 25.92 ;
    END
  END fd_in[290]
  PIN fd_in[291]
    DIRECTION INPUT ;
    USE SIGNAL ;
    PORT
      LAYER M5 ;
        RECT  92.064 25.836 92.088 25.92 ;
    END
  END fd_in[291]
  PIN fd_in[292]
    DIRECTION INPUT ;
    USE SIGNAL ;
    PORT
      LAYER M5 ;
        RECT  91.872 25.836 91.896 25.92 ;
    END
  END fd_in[292]
  PIN fd_in[293]
    DIRECTION INPUT ;
    USE SIGNAL ;
    PORT
      LAYER M5 ;
        RECT  91.728 25.836 91.752 25.92 ;
    END
  END fd_in[293]
  PIN fd_in[294]
    DIRECTION INPUT ;
    USE SIGNAL ;
    PORT
      LAYER M5 ;
        RECT  91.536 25.836 91.56 25.92 ;
    END
  END fd_in[294]
  PIN fd_in[295]
    DIRECTION INPUT ;
    USE SIGNAL ;
    PORT
      LAYER M5 ;
        RECT  91.344 25.836 91.368 25.92 ;
    END
  END fd_in[295]
  PIN fd_in[296]
    DIRECTION INPUT ;
    USE SIGNAL ;
    PORT
      LAYER M5 ;
        RECT  91.152 25.836 91.176 25.92 ;
    END
  END fd_in[296]
  PIN fd_in[297]
    DIRECTION INPUT ;
    USE SIGNAL ;
    PORT
      LAYER M5 ;
        RECT  91.008 25.836 91.032 25.92 ;
    END
  END fd_in[297]
  PIN fd_in[298]
    DIRECTION INPUT ;
    USE SIGNAL ;
    PORT
      LAYER M5 ;
        RECT  90.816 25.836 90.84 25.92 ;
    END
  END fd_in[298]
  PIN fd_in[299]
    DIRECTION INPUT ;
    USE SIGNAL ;
    PORT
      LAYER M5 ;
        RECT  90.624 25.836 90.648 25.92 ;
    END
  END fd_in[299]
  PIN fd_in[29]
    DIRECTION INPUT ;
    USE SIGNAL ;
    PORT
      LAYER M5 ;
        RECT  139.056 25.836 139.08 25.92 ;
    END
  END fd_in[29]
  PIN fd_in[2]
    DIRECTION INPUT ;
    USE SIGNAL ;
    PORT
      LAYER M5 ;
        RECT  143.904 25.836 143.928 25.92 ;
    END
  END fd_in[2]
  PIN fd_in[300]
    DIRECTION INPUT ;
    USE SIGNAL ;
    PORT
      LAYER M5 ;
        RECT  90.432 25.836 90.456 25.92 ;
    END
  END fd_in[300]
  PIN fd_in[301]
    DIRECTION INPUT ;
    USE SIGNAL ;
    PORT
      LAYER M5 ;
        RECT  90.288 25.836 90.312 25.92 ;
    END
  END fd_in[301]
  PIN fd_in[302]
    DIRECTION INPUT ;
    USE SIGNAL ;
    PORT
      LAYER M5 ;
        RECT  90.096 25.836 90.12 25.92 ;
    END
  END fd_in[302]
  PIN fd_in[303]
    DIRECTION INPUT ;
    USE SIGNAL ;
    PORT
      LAYER M5 ;
        RECT  89.904 25.836 89.928 25.92 ;
    END
  END fd_in[303]
  PIN fd_in[304]
    DIRECTION INPUT ;
    USE SIGNAL ;
    PORT
      LAYER M5 ;
        RECT  89.76 25.836 89.784 25.92 ;
    END
  END fd_in[304]
  PIN fd_in[305]
    DIRECTION INPUT ;
    USE SIGNAL ;
    PORT
      LAYER M5 ;
        RECT  89.568 25.836 89.592 25.92 ;
    END
  END fd_in[305]
  PIN fd_in[306]
    DIRECTION INPUT ;
    USE SIGNAL ;
    PORT
      LAYER M5 ;
        RECT  89.376 25.836 89.4 25.92 ;
    END
  END fd_in[306]
  PIN fd_in[307]
    DIRECTION INPUT ;
    USE SIGNAL ;
    PORT
      LAYER M5 ;
        RECT  89.184 25.836 89.208 25.92 ;
    END
  END fd_in[307]
  PIN fd_in[308]
    DIRECTION INPUT ;
    USE SIGNAL ;
    PORT
      LAYER M5 ;
        RECT  89.04 25.836 89.064 25.92 ;
    END
  END fd_in[308]
  PIN fd_in[309]
    DIRECTION INPUT ;
    USE SIGNAL ;
    PORT
      LAYER M5 ;
        RECT  88.848 25.836 88.872 25.92 ;
    END
  END fd_in[309]
  PIN fd_in[30]
    DIRECTION INPUT ;
    USE SIGNAL ;
    PORT
      LAYER M5 ;
        RECT  138.864 25.836 138.888 25.92 ;
    END
  END fd_in[30]
  PIN fd_in[310]
    DIRECTION INPUT ;
    USE SIGNAL ;
    PORT
      LAYER M5 ;
        RECT  88.656 25.836 88.68 25.92 ;
    END
  END fd_in[310]
  PIN fd_in[311]
    DIRECTION INPUT ;
    USE SIGNAL ;
    PORT
      LAYER M5 ;
        RECT  88.464 25.836 88.488 25.92 ;
    END
  END fd_in[311]
  PIN fd_in[312]
    DIRECTION INPUT ;
    USE SIGNAL ;
    PORT
      LAYER M5 ;
        RECT  88.32 25.836 88.344 25.92 ;
    END
  END fd_in[312]
  PIN fd_in[313]
    DIRECTION INPUT ;
    USE SIGNAL ;
    PORT
      LAYER M5 ;
        RECT  88.128 25.836 88.152 25.92 ;
    END
  END fd_in[313]
  PIN fd_in[314]
    DIRECTION INPUT ;
    USE SIGNAL ;
    PORT
      LAYER M5 ;
        RECT  37.92 25.836 37.944 25.92 ;
    END
  END fd_in[314]
  PIN fd_in[315]
    DIRECTION INPUT ;
    USE SIGNAL ;
    PORT
      LAYER M5 ;
        RECT  37.728 25.836 37.752 25.92 ;
    END
  END fd_in[315]
  PIN fd_in[316]
    DIRECTION INPUT ;
    USE SIGNAL ;
    PORT
      LAYER M5 ;
        RECT  37.584 25.836 37.608 25.92 ;
    END
  END fd_in[316]
  PIN fd_in[317]
    DIRECTION INPUT ;
    USE SIGNAL ;
    PORT
      LAYER M5 ;
        RECT  37.392 25.836 37.416 25.92 ;
    END
  END fd_in[317]
  PIN fd_in[318]
    DIRECTION INPUT ;
    USE SIGNAL ;
    PORT
      LAYER M5 ;
        RECT  37.2 25.836 37.224 25.92 ;
    END
  END fd_in[318]
  PIN fd_in[319]
    DIRECTION INPUT ;
    USE SIGNAL ;
    PORT
      LAYER M5 ;
        RECT  37.008 25.836 37.032 25.92 ;
    END
  END fd_in[319]
  PIN fd_in[31]
    DIRECTION INPUT ;
    USE SIGNAL ;
    PORT
      LAYER M5 ;
        RECT  138.72 25.836 138.744 25.92 ;
    END
  END fd_in[31]
  PIN fd_in[320]
    DIRECTION INPUT ;
    USE SIGNAL ;
    PORT
      LAYER M5 ;
        RECT  36.864 25.836 36.888 25.92 ;
    END
  END fd_in[320]
  PIN fd_in[321]
    DIRECTION INPUT ;
    USE SIGNAL ;
    PORT
      LAYER M5 ;
        RECT  36.672 25.836 36.696 25.92 ;
    END
  END fd_in[321]
  PIN fd_in[322]
    DIRECTION INPUT ;
    USE SIGNAL ;
    PORT
      LAYER M5 ;
        RECT  36.48 25.836 36.504 25.92 ;
    END
  END fd_in[322]
  PIN fd_in[323]
    DIRECTION INPUT ;
    USE SIGNAL ;
    PORT
      LAYER M5 ;
        RECT  36.336 25.836 36.36 25.92 ;
    END
  END fd_in[323]
  PIN fd_in[324]
    DIRECTION INPUT ;
    USE SIGNAL ;
    PORT
      LAYER M5 ;
        RECT  36.144 25.836 36.168 25.92 ;
    END
  END fd_in[324]
  PIN fd_in[325]
    DIRECTION INPUT ;
    USE SIGNAL ;
    PORT
      LAYER M5 ;
        RECT  35.952 25.836 35.976 25.92 ;
    END
  END fd_in[325]
  PIN fd_in[326]
    DIRECTION INPUT ;
    USE SIGNAL ;
    PORT
      LAYER M5 ;
        RECT  35.76 25.836 35.784 25.92 ;
    END
  END fd_in[326]
  PIN fd_in[327]
    DIRECTION INPUT ;
    USE SIGNAL ;
    PORT
      LAYER M5 ;
        RECT  35.616 25.836 35.64 25.92 ;
    END
  END fd_in[327]
  PIN fd_in[328]
    DIRECTION INPUT ;
    USE SIGNAL ;
    PORT
      LAYER M5 ;
        RECT  35.424 25.836 35.448 25.92 ;
    END
  END fd_in[328]
  PIN fd_in[329]
    DIRECTION INPUT ;
    USE SIGNAL ;
    PORT
      LAYER M5 ;
        RECT  35.232 25.836 35.256 25.92 ;
    END
  END fd_in[329]
  PIN fd_in[32]
    DIRECTION INPUT ;
    USE SIGNAL ;
    PORT
      LAYER M5 ;
        RECT  138.528 25.836 138.552 25.92 ;
    END
  END fd_in[32]
  PIN fd_in[330]
    DIRECTION INPUT ;
    USE SIGNAL ;
    PORT
      LAYER M5 ;
        RECT  35.04 25.836 35.064 25.92 ;
    END
  END fd_in[330]
  PIN fd_in[331]
    DIRECTION INPUT ;
    USE SIGNAL ;
    PORT
      LAYER M5 ;
        RECT  34.896 25.836 34.92 25.92 ;
    END
  END fd_in[331]
  PIN fd_in[332]
    DIRECTION INPUT ;
    USE SIGNAL ;
    PORT
      LAYER M5 ;
        RECT  34.704 25.836 34.728 25.92 ;
    END
  END fd_in[332]
  PIN fd_in[333]
    DIRECTION INPUT ;
    USE SIGNAL ;
    PORT
      LAYER M5 ;
        RECT  34.512 25.836 34.536 25.92 ;
    END
  END fd_in[333]
  PIN fd_in[334]
    DIRECTION INPUT ;
    USE SIGNAL ;
    PORT
      LAYER M5 ;
        RECT  34.32 25.836 34.344 25.92 ;
    END
  END fd_in[334]
  PIN fd_in[335]
    DIRECTION INPUT ;
    USE SIGNAL ;
    PORT
      LAYER M5 ;
        RECT  34.176 25.836 34.2 25.92 ;
    END
  END fd_in[335]
  PIN fd_in[336]
    DIRECTION INPUT ;
    USE SIGNAL ;
    PORT
      LAYER M5 ;
        RECT  33.984 25.836 34.008 25.92 ;
    END
  END fd_in[336]
  PIN fd_in[337]
    DIRECTION INPUT ;
    USE SIGNAL ;
    PORT
      LAYER M5 ;
        RECT  33.792 25.836 33.816 25.92 ;
    END
  END fd_in[337]
  PIN fd_in[338]
    DIRECTION INPUT ;
    USE SIGNAL ;
    PORT
      LAYER M5 ;
        RECT  33.648 25.836 33.672 25.92 ;
    END
  END fd_in[338]
  PIN fd_in[339]
    DIRECTION INPUT ;
    USE SIGNAL ;
    PORT
      LAYER M5 ;
        RECT  33.456 25.836 33.48 25.92 ;
    END
  END fd_in[339]
  PIN fd_in[33]
    DIRECTION INPUT ;
    USE SIGNAL ;
    PORT
      LAYER M5 ;
        RECT  138.336 25.836 138.36 25.92 ;
    END
  END fd_in[33]
  PIN fd_in[340]
    DIRECTION INPUT ;
    USE SIGNAL ;
    PORT
      LAYER M5 ;
        RECT  33.264 25.836 33.288 25.92 ;
    END
  END fd_in[340]
  PIN fd_in[341]
    DIRECTION INPUT ;
    USE SIGNAL ;
    PORT
      LAYER M5 ;
        RECT  33.072 25.836 33.096 25.92 ;
    END
  END fd_in[341]
  PIN fd_in[342]
    DIRECTION INPUT ;
    USE SIGNAL ;
    PORT
      LAYER M5 ;
        RECT  32.928 25.836 32.952 25.92 ;
    END
  END fd_in[342]
  PIN fd_in[343]
    DIRECTION INPUT ;
    USE SIGNAL ;
    PORT
      LAYER M5 ;
        RECT  32.736 25.836 32.76 25.92 ;
    END
  END fd_in[343]
  PIN fd_in[344]
    DIRECTION INPUT ;
    USE SIGNAL ;
    PORT
      LAYER M5 ;
        RECT  32.544 25.836 32.568 25.92 ;
    END
  END fd_in[344]
  PIN fd_in[345]
    DIRECTION INPUT ;
    USE SIGNAL ;
    PORT
      LAYER M5 ;
        RECT  32.352 25.836 32.376 25.92 ;
    END
  END fd_in[345]
  PIN fd_in[346]
    DIRECTION INPUT ;
    USE SIGNAL ;
    PORT
      LAYER M5 ;
        RECT  32.208 25.836 32.232 25.92 ;
    END
  END fd_in[346]
  PIN fd_in[347]
    DIRECTION INPUT ;
    USE SIGNAL ;
    PORT
      LAYER M5 ;
        RECT  32.016 25.836 32.04 25.92 ;
    END
  END fd_in[347]
  PIN fd_in[348]
    DIRECTION INPUT ;
    USE SIGNAL ;
    PORT
      LAYER M5 ;
        RECT  31.824 25.836 31.848 25.92 ;
    END
  END fd_in[348]
  PIN fd_in[349]
    DIRECTION INPUT ;
    USE SIGNAL ;
    PORT
      LAYER M5 ;
        RECT  31.632 25.836 31.656 25.92 ;
    END
  END fd_in[349]
  PIN fd_in[34]
    DIRECTION INPUT ;
    USE SIGNAL ;
    PORT
      LAYER M5 ;
        RECT  138.144 25.836 138.168 25.92 ;
    END
  END fd_in[34]
  PIN fd_in[350]
    DIRECTION INPUT ;
    USE SIGNAL ;
    PORT
      LAYER M5 ;
        RECT  31.488 25.836 31.512 25.92 ;
    END
  END fd_in[350]
  PIN fd_in[351]
    DIRECTION INPUT ;
    USE SIGNAL ;
    PORT
      LAYER M5 ;
        RECT  31.296 25.836 31.32 25.92 ;
    END
  END fd_in[351]
  PIN fd_in[352]
    DIRECTION INPUT ;
    USE SIGNAL ;
    PORT
      LAYER M5 ;
        RECT  31.104 25.836 31.128 25.92 ;
    END
  END fd_in[352]
  PIN fd_in[353]
    DIRECTION INPUT ;
    USE SIGNAL ;
    PORT
      LAYER M5 ;
        RECT  30.912 25.836 30.936 25.92 ;
    END
  END fd_in[353]
  PIN fd_in[354]
    DIRECTION INPUT ;
    USE SIGNAL ;
    PORT
      LAYER M5 ;
        RECT  30.768 25.836 30.792 25.92 ;
    END
  END fd_in[354]
  PIN fd_in[355]
    DIRECTION INPUT ;
    USE SIGNAL ;
    PORT
      LAYER M5 ;
        RECT  30.576 25.836 30.6 25.92 ;
    END
  END fd_in[355]
  PIN fd_in[356]
    DIRECTION INPUT ;
    USE SIGNAL ;
    PORT
      LAYER M5 ;
        RECT  30.384 25.836 30.408 25.92 ;
    END
  END fd_in[356]
  PIN fd_in[357]
    DIRECTION INPUT ;
    USE SIGNAL ;
    PORT
      LAYER M5 ;
        RECT  30.24 25.836 30.264 25.92 ;
    END
  END fd_in[357]
  PIN fd_in[358]
    DIRECTION INPUT ;
    USE SIGNAL ;
    PORT
      LAYER M5 ;
        RECT  30.048 25.836 30.072 25.92 ;
    END
  END fd_in[358]
  PIN fd_in[359]
    DIRECTION INPUT ;
    USE SIGNAL ;
    PORT
      LAYER M5 ;
        RECT  29.856 25.836 29.88 25.92 ;
    END
  END fd_in[359]
  PIN fd_in[35]
    DIRECTION INPUT ;
    USE SIGNAL ;
    PORT
      LAYER M5 ;
        RECT  138 25.836 138.024 25.92 ;
    END
  END fd_in[35]
  PIN fd_in[360]
    DIRECTION INPUT ;
    USE SIGNAL ;
    PORT
      LAYER M5 ;
        RECT  29.664 25.836 29.688 25.92 ;
    END
  END fd_in[360]
  PIN fd_in[361]
    DIRECTION INPUT ;
    USE SIGNAL ;
    PORT
      LAYER M5 ;
        RECT  29.52 25.836 29.544 25.92 ;
    END
  END fd_in[361]
  PIN fd_in[362]
    DIRECTION INPUT ;
    USE SIGNAL ;
    PORT
      LAYER M5 ;
        RECT  29.328 25.836 29.352 25.92 ;
    END
  END fd_in[362]
  PIN fd_in[363]
    DIRECTION INPUT ;
    USE SIGNAL ;
    PORT
      LAYER M5 ;
        RECT  29.136 25.836 29.16 25.92 ;
    END
  END fd_in[363]
  PIN fd_in[364]
    DIRECTION INPUT ;
    USE SIGNAL ;
    PORT
      LAYER M5 ;
        RECT  28.944 25.836 28.968 25.92 ;
    END
  END fd_in[364]
  PIN fd_in[365]
    DIRECTION INPUT ;
    USE SIGNAL ;
    PORT
      LAYER M5 ;
        RECT  28.8 25.836 28.824 25.92 ;
    END
  END fd_in[365]
  PIN fd_in[366]
    DIRECTION INPUT ;
    USE SIGNAL ;
    PORT
      LAYER M5 ;
        RECT  28.608 25.836 28.632 25.92 ;
    END
  END fd_in[366]
  PIN fd_in[367]
    DIRECTION INPUT ;
    USE SIGNAL ;
    PORT
      LAYER M5 ;
        RECT  28.416 25.836 28.44 25.92 ;
    END
  END fd_in[367]
  PIN fd_in[368]
    DIRECTION INPUT ;
    USE SIGNAL ;
    PORT
      LAYER M5 ;
        RECT  28.224 25.836 28.248 25.92 ;
    END
  END fd_in[368]
  PIN fd_in[369]
    DIRECTION INPUT ;
    USE SIGNAL ;
    PORT
      LAYER M5 ;
        RECT  28.08 25.836 28.104 25.92 ;
    END
  END fd_in[369]
  PIN fd_in[36]
    DIRECTION INPUT ;
    USE SIGNAL ;
    PORT
      LAYER M5 ;
        RECT  137.808 25.836 137.832 25.92 ;
    END
  END fd_in[36]
  PIN fd_in[370]
    DIRECTION INPUT ;
    USE SIGNAL ;
    PORT
      LAYER M5 ;
        RECT  27.888 25.836 27.912 25.92 ;
    END
  END fd_in[370]
  PIN fd_in[371]
    DIRECTION INPUT ;
    USE SIGNAL ;
    PORT
      LAYER M5 ;
        RECT  27.696 25.836 27.72 25.92 ;
    END
  END fd_in[371]
  PIN fd_in[372]
    DIRECTION INPUT ;
    USE SIGNAL ;
    PORT
      LAYER M5 ;
        RECT  27.504 25.836 27.528 25.92 ;
    END
  END fd_in[372]
  PIN fd_in[373]
    DIRECTION INPUT ;
    USE SIGNAL ;
    PORT
      LAYER M5 ;
        RECT  27.36 25.836 27.384 25.92 ;
    END
  END fd_in[373]
  PIN fd_in[374]
    DIRECTION INPUT ;
    USE SIGNAL ;
    PORT
      LAYER M5 ;
        RECT  27.168 25.836 27.192 25.92 ;
    END
  END fd_in[374]
  PIN fd_in[375]
    DIRECTION INPUT ;
    USE SIGNAL ;
    PORT
      LAYER M5 ;
        RECT  26.976 25.836 27 25.92 ;
    END
  END fd_in[375]
  PIN fd_in[376]
    DIRECTION INPUT ;
    USE SIGNAL ;
    PORT
      LAYER M5 ;
        RECT  26.832 25.836 26.856 25.92 ;
    END
  END fd_in[376]
  PIN fd_in[377]
    DIRECTION INPUT ;
    USE SIGNAL ;
    PORT
      LAYER M5 ;
        RECT  26.64 25.836 26.664 25.92 ;
    END
  END fd_in[377]
  PIN fd_in[378]
    DIRECTION INPUT ;
    USE SIGNAL ;
    PORT
      LAYER M5 ;
        RECT  26.448 25.836 26.472 25.92 ;
    END
  END fd_in[378]
  PIN fd_in[379]
    DIRECTION INPUT ;
    USE SIGNAL ;
    PORT
      LAYER M5 ;
        RECT  26.256 25.836 26.28 25.92 ;
    END
  END fd_in[379]
  PIN fd_in[37]
    DIRECTION INPUT ;
    USE SIGNAL ;
    PORT
      LAYER M5 ;
        RECT  137.616 25.836 137.64 25.92 ;
    END
  END fd_in[37]
  PIN fd_in[380]
    DIRECTION INPUT ;
    USE SIGNAL ;
    PORT
      LAYER M5 ;
        RECT  26.112 25.836 26.136 25.92 ;
    END
  END fd_in[380]
  PIN fd_in[381]
    DIRECTION INPUT ;
    USE SIGNAL ;
    PORT
      LAYER M5 ;
        RECT  25.92 25.836 25.944 25.92 ;
    END
  END fd_in[381]
  PIN fd_in[382]
    DIRECTION INPUT ;
    USE SIGNAL ;
    PORT
      LAYER M5 ;
        RECT  25.728 25.836 25.752 25.92 ;
    END
  END fd_in[382]
  PIN fd_in[383]
    DIRECTION INPUT ;
    USE SIGNAL ;
    PORT
      LAYER M5 ;
        RECT  25.536 25.836 25.56 25.92 ;
    END
  END fd_in[383]
  PIN fd_in[384]
    DIRECTION INPUT ;
    USE SIGNAL ;
    PORT
      LAYER M5 ;
        RECT  25.392 25.836 25.416 25.92 ;
    END
  END fd_in[384]
  PIN fd_in[385]
    DIRECTION INPUT ;
    USE SIGNAL ;
    PORT
      LAYER M5 ;
        RECT  25.2 25.836 25.224 25.92 ;
    END
  END fd_in[385]
  PIN fd_in[386]
    DIRECTION INPUT ;
    USE SIGNAL ;
    PORT
      LAYER M5 ;
        RECT  25.008 25.836 25.032 25.92 ;
    END
  END fd_in[386]
  PIN fd_in[387]
    DIRECTION INPUT ;
    USE SIGNAL ;
    PORT
      LAYER M5 ;
        RECT  24.816 25.836 24.84 25.92 ;
    END
  END fd_in[387]
  PIN fd_in[388]
    DIRECTION INPUT ;
    USE SIGNAL ;
    PORT
      LAYER M5 ;
        RECT  24.672 25.836 24.696 25.92 ;
    END
  END fd_in[388]
  PIN fd_in[389]
    DIRECTION INPUT ;
    USE SIGNAL ;
    PORT
      LAYER M5 ;
        RECT  24.48 25.836 24.504 25.92 ;
    END
  END fd_in[389]
  PIN fd_in[38]
    DIRECTION INPUT ;
    USE SIGNAL ;
    PORT
      LAYER M5 ;
        RECT  137.424 25.836 137.448 25.92 ;
    END
  END fd_in[38]
  PIN fd_in[390]
    DIRECTION INPUT ;
    USE SIGNAL ;
    PORT
      LAYER M5 ;
        RECT  24.288 25.836 24.312 25.92 ;
    END
  END fd_in[390]
  PIN fd_in[391]
    DIRECTION INPUT ;
    USE SIGNAL ;
    PORT
      LAYER M5 ;
        RECT  24.096 25.836 24.12 25.92 ;
    END
  END fd_in[391]
  PIN fd_in[392]
    DIRECTION INPUT ;
    USE SIGNAL ;
    PORT
      LAYER M5 ;
        RECT  23.952 25.836 23.976 25.92 ;
    END
  END fd_in[392]
  PIN fd_in[393]
    DIRECTION INPUT ;
    USE SIGNAL ;
    PORT
      LAYER M5 ;
        RECT  23.76 25.836 23.784 25.92 ;
    END
  END fd_in[393]
  PIN fd_in[394]
    DIRECTION INPUT ;
    USE SIGNAL ;
    PORT
      LAYER M5 ;
        RECT  23.568 25.836 23.592 25.92 ;
    END
  END fd_in[394]
  PIN fd_in[395]
    DIRECTION INPUT ;
    USE SIGNAL ;
    PORT
      LAYER M5 ;
        RECT  23.424 25.836 23.448 25.92 ;
    END
  END fd_in[395]
  PIN fd_in[396]
    DIRECTION INPUT ;
    USE SIGNAL ;
    PORT
      LAYER M5 ;
        RECT  23.232 25.836 23.256 25.92 ;
    END
  END fd_in[396]
  PIN fd_in[397]
    DIRECTION INPUT ;
    USE SIGNAL ;
    PORT
      LAYER M5 ;
        RECT  23.04 25.836 23.064 25.92 ;
    END
  END fd_in[397]
  PIN fd_in[398]
    DIRECTION INPUT ;
    USE SIGNAL ;
    PORT
      LAYER M5 ;
        RECT  22.848 25.836 22.872 25.92 ;
    END
  END fd_in[398]
  PIN fd_in[399]
    DIRECTION INPUT ;
    USE SIGNAL ;
    PORT
      LAYER M5 ;
        RECT  22.704 25.836 22.728 25.92 ;
    END
  END fd_in[399]
  PIN fd_in[39]
    DIRECTION INPUT ;
    USE SIGNAL ;
    PORT
      LAYER M5 ;
        RECT  137.28 25.836 137.304 25.92 ;
    END
  END fd_in[39]
  PIN fd_in[3]
    DIRECTION INPUT ;
    USE SIGNAL ;
    PORT
      LAYER M5 ;
        RECT  143.712 25.836 143.736 25.92 ;
    END
  END fd_in[3]
  PIN fd_in[400]
    DIRECTION INPUT ;
    USE SIGNAL ;
    PORT
      LAYER M5 ;
        RECT  22.512 25.836 22.536 25.92 ;
    END
  END fd_in[400]
  PIN fd_in[401]
    DIRECTION INPUT ;
    USE SIGNAL ;
    PORT
      LAYER M5 ;
        RECT  22.32 25.836 22.344 25.92 ;
    END
  END fd_in[401]
  PIN fd_in[402]
    DIRECTION INPUT ;
    USE SIGNAL ;
    PORT
      LAYER M5 ;
        RECT  22.128 25.836 22.152 25.92 ;
    END
  END fd_in[402]
  PIN fd_in[403]
    DIRECTION INPUT ;
    USE SIGNAL ;
    PORT
      LAYER M5 ;
        RECT  21.984 25.836 22.008 25.92 ;
    END
  END fd_in[403]
  PIN fd_in[404]
    DIRECTION INPUT ;
    USE SIGNAL ;
    PORT
      LAYER M5 ;
        RECT  21.792 25.836 21.816 25.92 ;
    END
  END fd_in[404]
  PIN fd_in[405]
    DIRECTION INPUT ;
    USE SIGNAL ;
    PORT
      LAYER M5 ;
        RECT  21.6 25.836 21.624 25.92 ;
    END
  END fd_in[405]
  PIN fd_in[406]
    DIRECTION INPUT ;
    USE SIGNAL ;
    PORT
      LAYER M5 ;
        RECT  21.408 25.836 21.432 25.92 ;
    END
  END fd_in[406]
  PIN fd_in[407]
    DIRECTION INPUT ;
    USE SIGNAL ;
    PORT
      LAYER M5 ;
        RECT  21.264 25.836 21.288 25.92 ;
    END
  END fd_in[407]
  PIN fd_in[408]
    DIRECTION INPUT ;
    USE SIGNAL ;
    PORT
      LAYER M5 ;
        RECT  21.072 25.836 21.096 25.92 ;
    END
  END fd_in[408]
  PIN fd_in[409]
    DIRECTION INPUT ;
    USE SIGNAL ;
    PORT
      LAYER M5 ;
        RECT  20.88 25.836 20.904 25.92 ;
    END
  END fd_in[409]
  PIN fd_in[40]
    DIRECTION INPUT ;
    USE SIGNAL ;
    PORT
      LAYER M5 ;
        RECT  137.088 25.836 137.112 25.92 ;
    END
  END fd_in[40]
  PIN fd_in[410]
    DIRECTION INPUT ;
    USE SIGNAL ;
    PORT
      LAYER M5 ;
        RECT  20.688 25.836 20.712 25.92 ;
    END
  END fd_in[410]
  PIN fd_in[411]
    DIRECTION INPUT ;
    USE SIGNAL ;
    PORT
      LAYER M5 ;
        RECT  20.544 25.836 20.568 25.92 ;
    END
  END fd_in[411]
  PIN fd_in[412]
    DIRECTION INPUT ;
    USE SIGNAL ;
    PORT
      LAYER M5 ;
        RECT  20.352 25.836 20.376 25.92 ;
    END
  END fd_in[412]
  PIN fd_in[413]
    DIRECTION INPUT ;
    USE SIGNAL ;
    PORT
      LAYER M5 ;
        RECT  20.16 25.836 20.184 25.92 ;
    END
  END fd_in[413]
  PIN fd_in[414]
    DIRECTION INPUT ;
    USE SIGNAL ;
    PORT
      LAYER M5 ;
        RECT  20.016 25.836 20.04 25.92 ;
    END
  END fd_in[414]
  PIN fd_in[415]
    DIRECTION INPUT ;
    USE SIGNAL ;
    PORT
      LAYER M5 ;
        RECT  19.824 25.836 19.848 25.92 ;
    END
  END fd_in[415]
  PIN fd_in[416]
    DIRECTION INPUT ;
    USE SIGNAL ;
    PORT
      LAYER M5 ;
        RECT  19.632 25.836 19.656 25.92 ;
    END
  END fd_in[416]
  PIN fd_in[417]
    DIRECTION INPUT ;
    USE SIGNAL ;
    PORT
      LAYER M5 ;
        RECT  19.44 25.836 19.464 25.92 ;
    END
  END fd_in[417]
  PIN fd_in[418]
    DIRECTION INPUT ;
    USE SIGNAL ;
    PORT
      LAYER M5 ;
        RECT  19.296 25.836 19.32 25.92 ;
    END
  END fd_in[418]
  PIN fd_in[419]
    DIRECTION INPUT ;
    USE SIGNAL ;
    PORT
      LAYER M5 ;
        RECT  19.104 25.836 19.128 25.92 ;
    END
  END fd_in[419]
  PIN fd_in[41]
    DIRECTION INPUT ;
    USE SIGNAL ;
    PORT
      LAYER M5 ;
        RECT  136.896 25.836 136.92 25.92 ;
    END
  END fd_in[41]
  PIN fd_in[420]
    DIRECTION INPUT ;
    USE SIGNAL ;
    PORT
      LAYER M5 ;
        RECT  18.912 25.836 18.936 25.92 ;
    END
  END fd_in[420]
  PIN fd_in[421]
    DIRECTION INPUT ;
    USE SIGNAL ;
    PORT
      LAYER M5 ;
        RECT  18.72 25.836 18.744 25.92 ;
    END
  END fd_in[421]
  PIN fd_in[422]
    DIRECTION INPUT ;
    USE SIGNAL ;
    PORT
      LAYER M5 ;
        RECT  18.576 25.836 18.6 25.92 ;
    END
  END fd_in[422]
  PIN fd_in[423]
    DIRECTION INPUT ;
    USE SIGNAL ;
    PORT
      LAYER M5 ;
        RECT  18.384 25.836 18.408 25.92 ;
    END
  END fd_in[423]
  PIN fd_in[424]
    DIRECTION INPUT ;
    USE SIGNAL ;
    PORT
      LAYER M5 ;
        RECT  18.192 25.836 18.216 25.92 ;
    END
  END fd_in[424]
  PIN fd_in[425]
    DIRECTION INPUT ;
    USE SIGNAL ;
    PORT
      LAYER M5 ;
        RECT  18 25.836 18.024 25.92 ;
    END
  END fd_in[425]
  PIN fd_in[426]
    DIRECTION INPUT ;
    USE SIGNAL ;
    PORT
      LAYER M5 ;
        RECT  17.856 25.836 17.88 25.92 ;
    END
  END fd_in[426]
  PIN fd_in[427]
    DIRECTION INPUT ;
    USE SIGNAL ;
    PORT
      LAYER M5 ;
        RECT  17.664 25.836 17.688 25.92 ;
    END
  END fd_in[427]
  PIN fd_in[428]
    DIRECTION INPUT ;
    USE SIGNAL ;
    PORT
      LAYER M5 ;
        RECT  17.472 25.836 17.496 25.92 ;
    END
  END fd_in[428]
  PIN fd_in[429]
    DIRECTION INPUT ;
    USE SIGNAL ;
    PORT
      LAYER M5 ;
        RECT  17.328 25.836 17.352 25.92 ;
    END
  END fd_in[429]
  PIN fd_in[42]
    DIRECTION INPUT ;
    USE SIGNAL ;
    PORT
      LAYER M5 ;
        RECT  136.704 25.836 136.728 25.92 ;
    END
  END fd_in[42]
  PIN fd_in[430]
    DIRECTION INPUT ;
    USE SIGNAL ;
    PORT
      LAYER M5 ;
        RECT  17.136 25.836 17.16 25.92 ;
    END
  END fd_in[430]
  PIN fd_in[431]
    DIRECTION INPUT ;
    USE SIGNAL ;
    PORT
      LAYER M5 ;
        RECT  16.944 25.836 16.968 25.92 ;
    END
  END fd_in[431]
  PIN fd_in[432]
    DIRECTION INPUT ;
    USE SIGNAL ;
    PORT
      LAYER M5 ;
        RECT  16.752 25.836 16.776 25.92 ;
    END
  END fd_in[432]
  PIN fd_in[433]
    DIRECTION INPUT ;
    USE SIGNAL ;
    PORT
      LAYER M5 ;
        RECT  16.608 25.836 16.632 25.92 ;
    END
  END fd_in[433]
  PIN fd_in[434]
    DIRECTION INPUT ;
    USE SIGNAL ;
    PORT
      LAYER M5 ;
        RECT  16.416 25.836 16.44 25.92 ;
    END
  END fd_in[434]
  PIN fd_in[435]
    DIRECTION INPUT ;
    USE SIGNAL ;
    PORT
      LAYER M5 ;
        RECT  16.224 25.836 16.248 25.92 ;
    END
  END fd_in[435]
  PIN fd_in[436]
    DIRECTION INPUT ;
    USE SIGNAL ;
    PORT
      LAYER M5 ;
        RECT  16.032 25.836 16.056 25.92 ;
    END
  END fd_in[436]
  PIN fd_in[437]
    DIRECTION INPUT ;
    USE SIGNAL ;
    PORT
      LAYER M5 ;
        RECT  15.888 25.836 15.912 25.92 ;
    END
  END fd_in[437]
  PIN fd_in[438]
    DIRECTION INPUT ;
    USE SIGNAL ;
    PORT
      LAYER M5 ;
        RECT  15.696 25.836 15.72 25.92 ;
    END
  END fd_in[438]
  PIN fd_in[439]
    DIRECTION INPUT ;
    USE SIGNAL ;
    PORT
      LAYER M5 ;
        RECT  15.504 25.836 15.528 25.92 ;
    END
  END fd_in[439]
  PIN fd_in[43]
    DIRECTION INPUT ;
    USE SIGNAL ;
    PORT
      LAYER M5 ;
        RECT  136.56 25.836 136.584 25.92 ;
    END
  END fd_in[43]
  PIN fd_in[440]
    DIRECTION INPUT ;
    USE SIGNAL ;
    PORT
      LAYER M5 ;
        RECT  15.312 25.836 15.336 25.92 ;
    END
  END fd_in[440]
  PIN fd_in[441]
    DIRECTION INPUT ;
    USE SIGNAL ;
    PORT
      LAYER M5 ;
        RECT  15.168 25.836 15.192 25.92 ;
    END
  END fd_in[441]
  PIN fd_in[442]
    DIRECTION INPUT ;
    USE SIGNAL ;
    PORT
      LAYER M5 ;
        RECT  14.976 25.836 15 25.92 ;
    END
  END fd_in[442]
  PIN fd_in[443]
    DIRECTION INPUT ;
    USE SIGNAL ;
    PORT
      LAYER M5 ;
        RECT  14.784 25.836 14.808 25.92 ;
    END
  END fd_in[443]
  PIN fd_in[444]
    DIRECTION INPUT ;
    USE SIGNAL ;
    PORT
      LAYER M5 ;
        RECT  14.592 25.836 14.616 25.92 ;
    END
  END fd_in[444]
  PIN fd_in[445]
    DIRECTION INPUT ;
    USE SIGNAL ;
    PORT
      LAYER M5 ;
        RECT  14.448 25.836 14.472 25.92 ;
    END
  END fd_in[445]
  PIN fd_in[446]
    DIRECTION INPUT ;
    USE SIGNAL ;
    PORT
      LAYER M5 ;
        RECT  14.256 25.836 14.28 25.92 ;
    END
  END fd_in[446]
  PIN fd_in[447]
    DIRECTION INPUT ;
    USE SIGNAL ;
    PORT
      LAYER M5 ;
        RECT  14.064 25.836 14.088 25.92 ;
    END
  END fd_in[447]
  PIN fd_in[448]
    DIRECTION INPUT ;
    USE SIGNAL ;
    PORT
      LAYER M5 ;
        RECT  13.92 25.836 13.944 25.92 ;
    END
  END fd_in[448]
  PIN fd_in[449]
    DIRECTION INPUT ;
    USE SIGNAL ;
    PORT
      LAYER M5 ;
        RECT  13.728 25.836 13.752 25.92 ;
    END
  END fd_in[449]
  PIN fd_in[44]
    DIRECTION INPUT ;
    USE SIGNAL ;
    PORT
      LAYER M5 ;
        RECT  136.368 25.836 136.392 25.92 ;
    END
  END fd_in[44]
  PIN fd_in[450]
    DIRECTION INPUT ;
    USE SIGNAL ;
    PORT
      LAYER M5 ;
        RECT  13.536 25.836 13.56 25.92 ;
    END
  END fd_in[450]
  PIN fd_in[451]
    DIRECTION INPUT ;
    USE SIGNAL ;
    PORT
      LAYER M5 ;
        RECT  13.344 25.836 13.368 25.92 ;
    END
  END fd_in[451]
  PIN fd_in[452]
    DIRECTION INPUT ;
    USE SIGNAL ;
    PORT
      LAYER M5 ;
        RECT  13.2 25.836 13.224 25.92 ;
    END
  END fd_in[452]
  PIN fd_in[453]
    DIRECTION INPUT ;
    USE SIGNAL ;
    PORT
      LAYER M5 ;
        RECT  13.008 25.836 13.032 25.92 ;
    END
  END fd_in[453]
  PIN fd_in[454]
    DIRECTION INPUT ;
    USE SIGNAL ;
    PORT
      LAYER M5 ;
        RECT  12.816 25.836 12.84 25.92 ;
    END
  END fd_in[454]
  PIN fd_in[455]
    DIRECTION INPUT ;
    USE SIGNAL ;
    PORT
      LAYER M5 ;
        RECT  12.624 25.836 12.648 25.92 ;
    END
  END fd_in[455]
  PIN fd_in[456]
    DIRECTION INPUT ;
    USE SIGNAL ;
    PORT
      LAYER M5 ;
        RECT  12.48 25.836 12.504 25.92 ;
    END
  END fd_in[456]
  PIN fd_in[457]
    DIRECTION INPUT ;
    USE SIGNAL ;
    PORT
      LAYER M5 ;
        RECT  12.288 25.836 12.312 25.92 ;
    END
  END fd_in[457]
  PIN fd_in[458]
    DIRECTION INPUT ;
    USE SIGNAL ;
    PORT
      LAYER M5 ;
        RECT  12.096 25.836 12.12 25.92 ;
    END
  END fd_in[458]
  PIN fd_in[459]
    DIRECTION INPUT ;
    USE SIGNAL ;
    PORT
      LAYER M5 ;
        RECT  11.904 25.836 11.928 25.92 ;
    END
  END fd_in[459]
  PIN fd_in[45]
    DIRECTION INPUT ;
    USE SIGNAL ;
    PORT
      LAYER M5 ;
        RECT  136.176 25.836 136.2 25.92 ;
    END
  END fd_in[45]
  PIN fd_in[460]
    DIRECTION INPUT ;
    USE SIGNAL ;
    PORT
      LAYER M5 ;
        RECT  11.76 25.836 11.784 25.92 ;
    END
  END fd_in[460]
  PIN fd_in[461]
    DIRECTION INPUT ;
    USE SIGNAL ;
    PORT
      LAYER M5 ;
        RECT  11.568 25.836 11.592 25.92 ;
    END
  END fd_in[461]
  PIN fd_in[462]
    DIRECTION INPUT ;
    USE SIGNAL ;
    PORT
      LAYER M5 ;
        RECT  11.376 25.836 11.4 25.92 ;
    END
  END fd_in[462]
  PIN fd_in[463]
    DIRECTION INPUT ;
    USE SIGNAL ;
    PORT
      LAYER M5 ;
        RECT  11.184 25.836 11.208 25.92 ;
    END
  END fd_in[463]
  PIN fd_in[464]
    DIRECTION INPUT ;
    USE SIGNAL ;
    PORT
      LAYER M5 ;
        RECT  11.04 25.836 11.064 25.92 ;
    END
  END fd_in[464]
  PIN fd_in[465]
    DIRECTION INPUT ;
    USE SIGNAL ;
    PORT
      LAYER M5 ;
        RECT  10.848 25.836 10.872 25.92 ;
    END
  END fd_in[465]
  PIN fd_in[466]
    DIRECTION INPUT ;
    USE SIGNAL ;
    PORT
      LAYER M5 ;
        RECT  10.656 25.836 10.68 25.92 ;
    END
  END fd_in[466]
  PIN fd_in[467]
    DIRECTION INPUT ;
    USE SIGNAL ;
    PORT
      LAYER M5 ;
        RECT  10.512 25.836 10.536 25.92 ;
    END
  END fd_in[467]
  PIN fd_in[468]
    DIRECTION INPUT ;
    USE SIGNAL ;
    PORT
      LAYER M5 ;
        RECT  10.32 25.836 10.344 25.92 ;
    END
  END fd_in[468]
  PIN fd_in[469]
    DIRECTION INPUT ;
    USE SIGNAL ;
    PORT
      LAYER M5 ;
        RECT  10.128 25.836 10.152 25.92 ;
    END
  END fd_in[469]
  PIN fd_in[46]
    DIRECTION INPUT ;
    USE SIGNAL ;
    PORT
      LAYER M5 ;
        RECT  136.032 25.836 136.056 25.92 ;
    END
  END fd_in[46]
  PIN fd_in[470]
    DIRECTION INPUT ;
    USE SIGNAL ;
    PORT
      LAYER M5 ;
        RECT  9.936 25.836 9.96 25.92 ;
    END
  END fd_in[470]
  PIN fd_in[471]
    DIRECTION INPUT ;
    USE SIGNAL ;
    PORT
      LAYER M5 ;
        RECT  9.792 25.836 9.816 25.92 ;
    END
  END fd_in[471]
  PIN fd_in[472]
    DIRECTION INPUT ;
    USE SIGNAL ;
    PORT
      LAYER M5 ;
        RECT  9.6 25.836 9.624 25.92 ;
    END
  END fd_in[472]
  PIN fd_in[473]
    DIRECTION INPUT ;
    USE SIGNAL ;
    PORT
      LAYER M5 ;
        RECT  9.408 25.836 9.432 25.92 ;
    END
  END fd_in[473]
  PIN fd_in[474]
    DIRECTION INPUT ;
    USE SIGNAL ;
    PORT
      LAYER M5 ;
        RECT  9.216 25.836 9.24 25.92 ;
    END
  END fd_in[474]
  PIN fd_in[475]
    DIRECTION INPUT ;
    USE SIGNAL ;
    PORT
      LAYER M5 ;
        RECT  9.072 25.836 9.096 25.92 ;
    END
  END fd_in[475]
  PIN fd_in[476]
    DIRECTION INPUT ;
    USE SIGNAL ;
    PORT
      LAYER M5 ;
        RECT  8.88 25.836 8.904 25.92 ;
    END
  END fd_in[476]
  PIN fd_in[477]
    DIRECTION INPUT ;
    USE SIGNAL ;
    PORT
      LAYER M5 ;
        RECT  8.688 25.836 8.712 25.92 ;
    END
  END fd_in[477]
  PIN fd_in[478]
    DIRECTION INPUT ;
    USE SIGNAL ;
    PORT
      LAYER M5 ;
        RECT  8.496 25.836 8.52 25.92 ;
    END
  END fd_in[478]
  PIN fd_in[479]
    DIRECTION INPUT ;
    USE SIGNAL ;
    PORT
      LAYER M5 ;
        RECT  8.352 25.836 8.376 25.92 ;
    END
  END fd_in[479]
  PIN fd_in[47]
    DIRECTION INPUT ;
    USE SIGNAL ;
    PORT
      LAYER M5 ;
        RECT  135.84 25.836 135.864 25.92 ;
    END
  END fd_in[47]
  PIN fd_in[480]
    DIRECTION INPUT ;
    USE SIGNAL ;
    PORT
      LAYER M5 ;
        RECT  8.16 25.836 8.184 25.92 ;
    END
  END fd_in[480]
  PIN fd_in[481]
    DIRECTION INPUT ;
    USE SIGNAL ;
    PORT
      LAYER M5 ;
        RECT  7.968 25.836 7.992 25.92 ;
    END
  END fd_in[481]
  PIN fd_in[482]
    DIRECTION INPUT ;
    USE SIGNAL ;
    PORT
      LAYER M5 ;
        RECT  7.776 25.836 7.8 25.92 ;
    END
  END fd_in[482]
  PIN fd_in[483]
    DIRECTION INPUT ;
    USE SIGNAL ;
    PORT
      LAYER M5 ;
        RECT  7.632 25.836 7.656 25.92 ;
    END
  END fd_in[483]
  PIN fd_in[484]
    DIRECTION INPUT ;
    USE SIGNAL ;
    PORT
      LAYER M5 ;
        RECT  7.44 25.836 7.464 25.92 ;
    END
  END fd_in[484]
  PIN fd_in[485]
    DIRECTION INPUT ;
    USE SIGNAL ;
    PORT
      LAYER M5 ;
        RECT  7.248 25.836 7.272 25.92 ;
    END
  END fd_in[485]
  PIN fd_in[486]
    DIRECTION INPUT ;
    USE SIGNAL ;
    PORT
      LAYER M5 ;
        RECT  7.104 25.836 7.128 25.92 ;
    END
  END fd_in[486]
  PIN fd_in[487]
    DIRECTION INPUT ;
    USE SIGNAL ;
    PORT
      LAYER M5 ;
        RECT  6.912 25.836 6.936 25.92 ;
    END
  END fd_in[487]
  PIN fd_in[488]
    DIRECTION INPUT ;
    USE SIGNAL ;
    PORT
      LAYER M5 ;
        RECT  6.72 25.836 6.744 25.92 ;
    END
  END fd_in[488]
  PIN fd_in[489]
    DIRECTION INPUT ;
    USE SIGNAL ;
    PORT
      LAYER M5 ;
        RECT  6.528 25.836 6.552 25.92 ;
    END
  END fd_in[489]
  PIN fd_in[48]
    DIRECTION INPUT ;
    USE SIGNAL ;
    PORT
      LAYER M5 ;
        RECT  135.648 25.836 135.672 25.92 ;
    END
  END fd_in[48]
  PIN fd_in[490]
    DIRECTION INPUT ;
    USE SIGNAL ;
    PORT
      LAYER M5 ;
        RECT  6.384 25.836 6.408 25.92 ;
    END
  END fd_in[490]
  PIN fd_in[491]
    DIRECTION INPUT ;
    USE SIGNAL ;
    PORT
      LAYER M5 ;
        RECT  6.192 25.836 6.216 25.92 ;
    END
  END fd_in[491]
  PIN fd_in[492]
    DIRECTION INPUT ;
    USE SIGNAL ;
    PORT
      LAYER M5 ;
        RECT  6 25.836 6.024 25.92 ;
    END
  END fd_in[492]
  PIN fd_in[493]
    DIRECTION INPUT ;
    USE SIGNAL ;
    PORT
      LAYER M5 ;
        RECT  5.808 25.836 5.832 25.92 ;
    END
  END fd_in[493]
  PIN fd_in[494]
    DIRECTION INPUT ;
    USE SIGNAL ;
    PORT
      LAYER M5 ;
        RECT  5.664 25.836 5.688 25.92 ;
    END
  END fd_in[494]
  PIN fd_in[495]
    DIRECTION INPUT ;
    USE SIGNAL ;
    PORT
      LAYER M5 ;
        RECT  5.472 25.836 5.496 25.92 ;
    END
  END fd_in[495]
  PIN fd_in[496]
    DIRECTION INPUT ;
    USE SIGNAL ;
    PORT
      LAYER M5 ;
        RECT  5.28 25.836 5.304 25.92 ;
    END
  END fd_in[496]
  PIN fd_in[497]
    DIRECTION INPUT ;
    USE SIGNAL ;
    PORT
      LAYER M5 ;
        RECT  5.088 25.836 5.112 25.92 ;
    END
  END fd_in[497]
  PIN fd_in[498]
    DIRECTION INPUT ;
    USE SIGNAL ;
    PORT
      LAYER M5 ;
        RECT  4.944 25.836 4.968 25.92 ;
    END
  END fd_in[498]
  PIN fd_in[499]
    DIRECTION INPUT ;
    USE SIGNAL ;
    PORT
      LAYER M5 ;
        RECT  4.752 25.836 4.776 25.92 ;
    END
  END fd_in[499]
  PIN fd_in[49]
    DIRECTION INPUT ;
    USE SIGNAL ;
    PORT
      LAYER M5 ;
        RECT  135.456 25.836 135.48 25.92 ;
    END
  END fd_in[49]
  PIN fd_in[4]
    DIRECTION INPUT ;
    USE SIGNAL ;
    PORT
      LAYER M5 ;
        RECT  143.52 25.836 143.544 25.92 ;
    END
  END fd_in[4]
  PIN fd_in[500]
    DIRECTION INPUT ;
    USE SIGNAL ;
    PORT
      LAYER M5 ;
        RECT  4.56 25.836 4.584 25.92 ;
    END
  END fd_in[500]
  PIN fd_in[501]
    DIRECTION INPUT ;
    USE SIGNAL ;
    PORT
      LAYER M5 ;
        RECT  4.368 25.836 4.392 25.92 ;
    END
  END fd_in[501]
  PIN fd_in[502]
    DIRECTION INPUT ;
    USE SIGNAL ;
    PORT
      LAYER M5 ;
        RECT  4.224 25.836 4.248 25.92 ;
    END
  END fd_in[502]
  PIN fd_in[503]
    DIRECTION INPUT ;
    USE SIGNAL ;
    PORT
      LAYER M5 ;
        RECT  4.032 25.836 4.056 25.92 ;
    END
  END fd_in[503]
  PIN fd_in[504]
    DIRECTION INPUT ;
    USE SIGNAL ;
    PORT
      LAYER M5 ;
        RECT  3.84 25.836 3.864 25.92 ;
    END
  END fd_in[504]
  PIN fd_in[505]
    DIRECTION INPUT ;
    USE SIGNAL ;
    PORT
      LAYER M5 ;
        RECT  3.696 25.836 3.72 25.92 ;
    END
  END fd_in[505]
  PIN fd_in[506]
    DIRECTION INPUT ;
    USE SIGNAL ;
    PORT
      LAYER M5 ;
        RECT  3.504 25.836 3.528 25.92 ;
    END
  END fd_in[506]
  PIN fd_in[507]
    DIRECTION INPUT ;
    USE SIGNAL ;
    PORT
      LAYER M5 ;
        RECT  3.312 25.836 3.336 25.92 ;
    END
  END fd_in[507]
  PIN fd_in[508]
    DIRECTION INPUT ;
    USE SIGNAL ;
    PORT
      LAYER M5 ;
        RECT  3.12 25.836 3.144 25.92 ;
    END
  END fd_in[508]
  PIN fd_in[509]
    DIRECTION INPUT ;
    USE SIGNAL ;
    PORT
      LAYER M5 ;
        RECT  2.976 25.836 3 25.92 ;
    END
  END fd_in[509]
  PIN fd_in[50]
    DIRECTION INPUT ;
    USE SIGNAL ;
    PORT
      LAYER M5 ;
        RECT  135.312 25.836 135.336 25.92 ;
    END
  END fd_in[50]
  PIN fd_in[510]
    DIRECTION INPUT ;
    USE SIGNAL ;
    PORT
      LAYER M5 ;
        RECT  2.784 25.836 2.808 25.92 ;
    END
  END fd_in[510]
  PIN fd_in[511]
    DIRECTION INPUT ;
    USE SIGNAL ;
    PORT
      LAYER M5 ;
        RECT  2.592 25.836 2.616 25.92 ;
    END
  END fd_in[511]
  PIN fd_in[512]
    DIRECTION INPUT ;
    USE SIGNAL ;
    PORT
      LAYER M5 ;
        RECT  2.4 25.836 2.424 25.92 ;
    END
  END fd_in[512]
  PIN fd_in[513]
    DIRECTION INPUT ;
    USE SIGNAL ;
    PORT
      LAYER M5 ;
        RECT  2.256 25.836 2.28 25.92 ;
    END
  END fd_in[513]
  PIN fd_in[514]
    DIRECTION INPUT ;
    USE SIGNAL ;
    PORT
      LAYER M5 ;
        RECT  2.064 25.836 2.088 25.92 ;
    END
  END fd_in[514]
  PIN fd_in[515]
    DIRECTION INPUT ;
    USE SIGNAL ;
    PORT
      LAYER M5 ;
        RECT  1.872 25.836 1.896 25.92 ;
    END
  END fd_in[515]
  PIN fd_in[516]
    DIRECTION INPUT ;
    USE SIGNAL ;
    PORT
      LAYER M5 ;
        RECT  1.68 25.836 1.704 25.92 ;
    END
  END fd_in[516]
  PIN fd_in[517]
    DIRECTION INPUT ;
    USE SIGNAL ;
    PORT
      LAYER M5 ;
        RECT  1.536 25.836 1.56 25.92 ;
    END
  END fd_in[517]
  PIN fd_in[518]
    DIRECTION INPUT ;
    USE SIGNAL ;
    PORT
      LAYER M5 ;
        RECT  1.344 25.836 1.368 25.92 ;
    END
  END fd_in[518]
  PIN fd_in[519]
    DIRECTION INPUT ;
    USE SIGNAL ;
    PORT
      LAYER M5 ;
        RECT  1.152 25.836 1.176 25.92 ;
    END
  END fd_in[519]
  PIN fd_in[51]
    DIRECTION INPUT ;
    USE SIGNAL ;
    PORT
      LAYER M5 ;
        RECT  135.12 25.836 135.144 25.92 ;
    END
  END fd_in[51]
  PIN fd_in[520]
    DIRECTION INPUT ;
    USE SIGNAL ;
    PORT
      LAYER M5 ;
        RECT  1.008 25.836 1.032 25.92 ;
    END
  END fd_in[520]
  PIN fd_in[52]
    DIRECTION INPUT ;
    USE SIGNAL ;
    PORT
      LAYER M5 ;
        RECT  134.928 25.836 134.952 25.92 ;
    END
  END fd_in[52]
  PIN fd_in[53]
    DIRECTION INPUT ;
    USE SIGNAL ;
    PORT
      LAYER M5 ;
        RECT  134.736 25.836 134.76 25.92 ;
    END
  END fd_in[53]
  PIN fd_in[54]
    DIRECTION INPUT ;
    USE SIGNAL ;
    PORT
      LAYER M5 ;
        RECT  134.592 25.836 134.616 25.92 ;
    END
  END fd_in[54]
  PIN fd_in[55]
    DIRECTION INPUT ;
    USE SIGNAL ;
    PORT
      LAYER M5 ;
        RECT  134.4 25.836 134.424 25.92 ;
    END
  END fd_in[55]
  PIN fd_in[56]
    DIRECTION INPUT ;
    USE SIGNAL ;
    PORT
      LAYER M5 ;
        RECT  134.208 25.836 134.232 25.92 ;
    END
  END fd_in[56]
  PIN fd_in[57]
    DIRECTION INPUT ;
    USE SIGNAL ;
    PORT
      LAYER M5 ;
        RECT  134.016 25.836 134.04 25.92 ;
    END
  END fd_in[57]
  PIN fd_in[58]
    DIRECTION INPUT ;
    USE SIGNAL ;
    PORT
      LAYER M5 ;
        RECT  133.872 25.836 133.896 25.92 ;
    END
  END fd_in[58]
  PIN fd_in[59]
    DIRECTION INPUT ;
    USE SIGNAL ;
    PORT
      LAYER M5 ;
        RECT  133.68 25.836 133.704 25.92 ;
    END
  END fd_in[59]
  PIN fd_in[5]
    DIRECTION INPUT ;
    USE SIGNAL ;
    PORT
      LAYER M5 ;
        RECT  143.376 25.836 143.4 25.92 ;
    END
  END fd_in[5]
  PIN fd_in[60]
    DIRECTION INPUT ;
    USE SIGNAL ;
    PORT
      LAYER M5 ;
        RECT  133.488 25.836 133.512 25.92 ;
    END
  END fd_in[60]
  PIN fd_in[61]
    DIRECTION INPUT ;
    USE SIGNAL ;
    PORT
      LAYER M5 ;
        RECT  133.296 25.836 133.32 25.92 ;
    END
  END fd_in[61]
  PIN fd_in[62]
    DIRECTION INPUT ;
    USE SIGNAL ;
    PORT
      LAYER M5 ;
        RECT  133.152 25.836 133.176 25.92 ;
    END
  END fd_in[62]
  PIN fd_in[63]
    DIRECTION INPUT ;
    USE SIGNAL ;
    PORT
      LAYER M5 ;
        RECT  132.96 25.836 132.984 25.92 ;
    END
  END fd_in[63]
  PIN fd_in[64]
    DIRECTION INPUT ;
    USE SIGNAL ;
    PORT
      LAYER M5 ;
        RECT  132.768 25.836 132.792 25.92 ;
    END
  END fd_in[64]
  PIN fd_in[65]
    DIRECTION INPUT ;
    USE SIGNAL ;
    PORT
      LAYER M5 ;
        RECT  132.624 25.836 132.648 25.92 ;
    END
  END fd_in[65]
  PIN fd_in[66]
    DIRECTION INPUT ;
    USE SIGNAL ;
    PORT
      LAYER M5 ;
        RECT  132.432 25.836 132.456 25.92 ;
    END
  END fd_in[66]
  PIN fd_in[67]
    DIRECTION INPUT ;
    USE SIGNAL ;
    PORT
      LAYER M5 ;
        RECT  132.24 25.836 132.264 25.92 ;
    END
  END fd_in[67]
  PIN fd_in[68]
    DIRECTION INPUT ;
    USE SIGNAL ;
    PORT
      LAYER M5 ;
        RECT  132.048 25.836 132.072 25.92 ;
    END
  END fd_in[68]
  PIN fd_in[69]
    DIRECTION INPUT ;
    USE SIGNAL ;
    PORT
      LAYER M5 ;
        RECT  131.904 25.836 131.928 25.92 ;
    END
  END fd_in[69]
  PIN fd_in[6]
    DIRECTION INPUT ;
    USE SIGNAL ;
    PORT
      LAYER M5 ;
        RECT  143.184 25.836 143.208 25.92 ;
    END
  END fd_in[6]
  PIN fd_in[70]
    DIRECTION INPUT ;
    USE SIGNAL ;
    PORT
      LAYER M5 ;
        RECT  131.712 25.836 131.736 25.92 ;
    END
  END fd_in[70]
  PIN fd_in[71]
    DIRECTION INPUT ;
    USE SIGNAL ;
    PORT
      LAYER M5 ;
        RECT  131.52 25.836 131.544 25.92 ;
    END
  END fd_in[71]
  PIN fd_in[72]
    DIRECTION INPUT ;
    USE SIGNAL ;
    PORT
      LAYER M5 ;
        RECT  131.328 25.836 131.352 25.92 ;
    END
  END fd_in[72]
  PIN fd_in[73]
    DIRECTION INPUT ;
    USE SIGNAL ;
    PORT
      LAYER M5 ;
        RECT  131.184 25.836 131.208 25.92 ;
    END
  END fd_in[73]
  PIN fd_in[74]
    DIRECTION INPUT ;
    USE SIGNAL ;
    PORT
      LAYER M5 ;
        RECT  130.992 25.836 131.016 25.92 ;
    END
  END fd_in[74]
  PIN fd_in[75]
    DIRECTION INPUT ;
    USE SIGNAL ;
    PORT
      LAYER M5 ;
        RECT  130.8 25.836 130.824 25.92 ;
    END
  END fd_in[75]
  PIN fd_in[76]
    DIRECTION INPUT ;
    USE SIGNAL ;
    PORT
      LAYER M5 ;
        RECT  130.608 25.836 130.632 25.92 ;
    END
  END fd_in[76]
  PIN fd_in[77]
    DIRECTION INPUT ;
    USE SIGNAL ;
    PORT
      LAYER M5 ;
        RECT  130.464 25.836 130.488 25.92 ;
    END
  END fd_in[77]
  PIN fd_in[78]
    DIRECTION INPUT ;
    USE SIGNAL ;
    PORT
      LAYER M5 ;
        RECT  130.272 25.836 130.296 25.92 ;
    END
  END fd_in[78]
  PIN fd_in[79]
    DIRECTION INPUT ;
    USE SIGNAL ;
    PORT
      LAYER M5 ;
        RECT  130.08 25.836 130.104 25.92 ;
    END
  END fd_in[79]
  PIN fd_in[7]
    DIRECTION INPUT ;
    USE SIGNAL ;
    PORT
      LAYER M5 ;
        RECT  142.992 25.836 143.016 25.92 ;
    END
  END fd_in[7]
  PIN fd_in[80]
    DIRECTION INPUT ;
    USE SIGNAL ;
    PORT
      LAYER M5 ;
        RECT  129.888 25.836 129.912 25.92 ;
    END
  END fd_in[80]
  PIN fd_in[81]
    DIRECTION INPUT ;
    USE SIGNAL ;
    PORT
      LAYER M5 ;
        RECT  129.744 25.836 129.768 25.92 ;
    END
  END fd_in[81]
  PIN fd_in[82]
    DIRECTION INPUT ;
    USE SIGNAL ;
    PORT
      LAYER M5 ;
        RECT  129.552 25.836 129.576 25.92 ;
    END
  END fd_in[82]
  PIN fd_in[83]
    DIRECTION INPUT ;
    USE SIGNAL ;
    PORT
      LAYER M5 ;
        RECT  129.36 25.836 129.384 25.92 ;
    END
  END fd_in[83]
  PIN fd_in[84]
    DIRECTION INPUT ;
    USE SIGNAL ;
    PORT
      LAYER M5 ;
        RECT  129.216 25.836 129.24 25.92 ;
    END
  END fd_in[84]
  PIN fd_in[85]
    DIRECTION INPUT ;
    USE SIGNAL ;
    PORT
      LAYER M5 ;
        RECT  129.024 25.836 129.048 25.92 ;
    END
  END fd_in[85]
  PIN fd_in[86]
    DIRECTION INPUT ;
    USE SIGNAL ;
    PORT
      LAYER M5 ;
        RECT  128.832 25.836 128.856 25.92 ;
    END
  END fd_in[86]
  PIN fd_in[87]
    DIRECTION INPUT ;
    USE SIGNAL ;
    PORT
      LAYER M5 ;
        RECT  128.64 25.836 128.664 25.92 ;
    END
  END fd_in[87]
  PIN fd_in[88]
    DIRECTION INPUT ;
    USE SIGNAL ;
    PORT
      LAYER M5 ;
        RECT  128.496 25.836 128.52 25.92 ;
    END
  END fd_in[88]
  PIN fd_in[89]
    DIRECTION INPUT ;
    USE SIGNAL ;
    PORT
      LAYER M5 ;
        RECT  128.304 25.836 128.328 25.92 ;
    END
  END fd_in[89]
  PIN fd_in[8]
    DIRECTION INPUT ;
    USE SIGNAL ;
    PORT
      LAYER M5 ;
        RECT  142.8 25.836 142.824 25.92 ;
    END
  END fd_in[8]
  PIN fd_in[90]
    DIRECTION INPUT ;
    USE SIGNAL ;
    PORT
      LAYER M5 ;
        RECT  128.112 25.836 128.136 25.92 ;
    END
  END fd_in[90]
  PIN fd_in[91]
    DIRECTION INPUT ;
    USE SIGNAL ;
    PORT
      LAYER M5 ;
        RECT  127.92 25.836 127.944 25.92 ;
    END
  END fd_in[91]
  PIN fd_in[92]
    DIRECTION INPUT ;
    USE SIGNAL ;
    PORT
      LAYER M5 ;
        RECT  127.776 25.836 127.8 25.92 ;
    END
  END fd_in[92]
  PIN fd_in[93]
    DIRECTION INPUT ;
    USE SIGNAL ;
    PORT
      LAYER M5 ;
        RECT  127.584 25.836 127.608 25.92 ;
    END
  END fd_in[93]
  PIN fd_in[94]
    DIRECTION INPUT ;
    USE SIGNAL ;
    PORT
      LAYER M5 ;
        RECT  127.392 25.836 127.416 25.92 ;
    END
  END fd_in[94]
  PIN fd_in[95]
    DIRECTION INPUT ;
    USE SIGNAL ;
    PORT
      LAYER M5 ;
        RECT  127.2 25.836 127.224 25.92 ;
    END
  END fd_in[95]
  PIN fd_in[96]
    DIRECTION INPUT ;
    USE SIGNAL ;
    PORT
      LAYER M5 ;
        RECT  127.056 25.836 127.08 25.92 ;
    END
  END fd_in[96]
  PIN fd_in[97]
    DIRECTION INPUT ;
    USE SIGNAL ;
    PORT
      LAYER M5 ;
        RECT  126.864 25.836 126.888 25.92 ;
    END
  END fd_in[97]
  PIN fd_in[98]
    DIRECTION INPUT ;
    USE SIGNAL ;
    PORT
      LAYER M5 ;
        RECT  126.672 25.836 126.696 25.92 ;
    END
  END fd_in[98]
  PIN fd_in[99]
    DIRECTION INPUT ;
    USE SIGNAL ;
    PORT
      LAYER M5 ;
        RECT  126.48 25.836 126.504 25.92 ;
    END
  END fd_in[99]
  PIN fd_in[9]
    DIRECTION INPUT ;
    USE SIGNAL ;
    PORT
      LAYER M5 ;
        RECT  142.656 25.836 142.68 25.92 ;
    END
  END fd_in[9]
  PIN fdm[0]
    DIRECTION OUTPUT ;
    USE SIGNAL ;
    PORT
      LAYER M5 ;
        RECT  144.24 0 144.264 0.084 ;
    END
  END fdm[0]
  PIN fdm[100]
    DIRECTION OUTPUT ;
    USE SIGNAL ;
    PORT
      LAYER M5 ;
        RECT  126.336 0 126.36 0.084 ;
    END
  END fdm[100]
  PIN fdm[101]
    DIRECTION OUTPUT ;
    USE SIGNAL ;
    PORT
      LAYER M5 ;
        RECT  126.144 0 126.168 0.084 ;
    END
  END fdm[101]
  PIN fdm[102]
    DIRECTION OUTPUT ;
    USE SIGNAL ;
    PORT
      LAYER M5 ;
        RECT  125.952 0 125.976 0.084 ;
    END
  END fdm[102]
  PIN fdm[103]
    DIRECTION OUTPUT ;
    USE SIGNAL ;
    PORT
      LAYER M5 ;
        RECT  125.808 0 125.832 0.084 ;
    END
  END fdm[103]
  PIN fdm[104]
    DIRECTION OUTPUT ;
    USE SIGNAL ;
    PORT
      LAYER M5 ;
        RECT  125.616 0 125.64 0.084 ;
    END
  END fdm[104]
  PIN fdm[105]
    DIRECTION OUTPUT ;
    USE SIGNAL ;
    PORT
      LAYER M5 ;
        RECT  125.424 0 125.448 0.084 ;
    END
  END fdm[105]
  PIN fdm[106]
    DIRECTION OUTPUT ;
    USE SIGNAL ;
    PORT
      LAYER M5 ;
        RECT  125.232 0 125.256 0.084 ;
    END
  END fdm[106]
  PIN fdm[107]
    DIRECTION OUTPUT ;
    USE SIGNAL ;
    PORT
      LAYER M5 ;
        RECT  125.088 0 125.112 0.084 ;
    END
  END fdm[107]
  PIN fdm[108]
    DIRECTION OUTPUT ;
    USE SIGNAL ;
    PORT
      LAYER M5 ;
        RECT  124.896 0 124.92 0.084 ;
    END
  END fdm[108]
  PIN fdm[109]
    DIRECTION OUTPUT ;
    USE SIGNAL ;
    PORT
      LAYER M5 ;
        RECT  124.704 0 124.728 0.084 ;
    END
  END fdm[109]
  PIN fdm[10]
    DIRECTION OUTPUT ;
    USE SIGNAL ;
    PORT
      LAYER M5 ;
        RECT  142.464 0 142.488 0.084 ;
    END
  END fdm[10]
  PIN fdm[110]
    DIRECTION OUTPUT ;
    USE SIGNAL ;
    PORT
      LAYER M5 ;
        RECT  124.512 0 124.536 0.084 ;
    END
  END fdm[110]
  PIN fdm[111]
    DIRECTION OUTPUT ;
    USE SIGNAL ;
    PORT
      LAYER M5 ;
        RECT  124.368 0 124.392 0.084 ;
    END
  END fdm[111]
  PIN fdm[112]
    DIRECTION OUTPUT ;
    USE SIGNAL ;
    PORT
      LAYER M5 ;
        RECT  124.176 0 124.2 0.084 ;
    END
  END fdm[112]
  PIN fdm[113]
    DIRECTION OUTPUT ;
    USE SIGNAL ;
    PORT
      LAYER M5 ;
        RECT  123.984 0 124.008 0.084 ;
    END
  END fdm[113]
  PIN fdm[114]
    DIRECTION OUTPUT ;
    USE SIGNAL ;
    PORT
      LAYER M5 ;
        RECT  123.792 0 123.816 0.084 ;
    END
  END fdm[114]
  PIN fdm[115]
    DIRECTION OUTPUT ;
    USE SIGNAL ;
    PORT
      LAYER M5 ;
        RECT  123.648 0 123.672 0.084 ;
    END
  END fdm[115]
  PIN fdm[116]
    DIRECTION OUTPUT ;
    USE SIGNAL ;
    PORT
      LAYER M5 ;
        RECT  123.456 0 123.48 0.084 ;
    END
  END fdm[116]
  PIN fdm[117]
    DIRECTION OUTPUT ;
    USE SIGNAL ;
    PORT
      LAYER M5 ;
        RECT  123.264 0 123.288 0.084 ;
    END
  END fdm[117]
  PIN fdm[118]
    DIRECTION OUTPUT ;
    USE SIGNAL ;
    PORT
      LAYER M5 ;
        RECT  123.072 0 123.096 0.084 ;
    END
  END fdm[118]
  PIN fdm[119]
    DIRECTION OUTPUT ;
    USE SIGNAL ;
    PORT
      LAYER M5 ;
        RECT  122.928 0 122.952 0.084 ;
    END
  END fdm[119]
  PIN fdm[11]
    DIRECTION OUTPUT ;
    USE SIGNAL ;
    PORT
      LAYER M5 ;
        RECT  142.272 0 142.296 0.084 ;
    END
  END fdm[11]
  PIN fdm[120]
    DIRECTION OUTPUT ;
    USE SIGNAL ;
    PORT
      LAYER M5 ;
        RECT  122.736 0 122.76 0.084 ;
    END
  END fdm[120]
  PIN fdm[121]
    DIRECTION OUTPUT ;
    USE SIGNAL ;
    PORT
      LAYER M5 ;
        RECT  122.544 0 122.568 0.084 ;
    END
  END fdm[121]
  PIN fdm[122]
    DIRECTION OUTPUT ;
    USE SIGNAL ;
    PORT
      LAYER M5 ;
        RECT  122.4 0 122.424 0.084 ;
    END
  END fdm[122]
  PIN fdm[123]
    DIRECTION OUTPUT ;
    USE SIGNAL ;
    PORT
      LAYER M5 ;
        RECT  122.208 0 122.232 0.084 ;
    END
  END fdm[123]
  PIN fdm[124]
    DIRECTION OUTPUT ;
    USE SIGNAL ;
    PORT
      LAYER M5 ;
        RECT  122.016 0 122.04 0.084 ;
    END
  END fdm[124]
  PIN fdm[125]
    DIRECTION OUTPUT ;
    USE SIGNAL ;
    PORT
      LAYER M5 ;
        RECT  121.824 0 121.848 0.084 ;
    END
  END fdm[125]
  PIN fdm[126]
    DIRECTION OUTPUT ;
    USE SIGNAL ;
    PORT
      LAYER M5 ;
        RECT  121.68 0 121.704 0.084 ;
    END
  END fdm[126]
  PIN fdm[127]
    DIRECTION OUTPUT ;
    USE SIGNAL ;
    PORT
      LAYER M5 ;
        RECT  121.488 0 121.512 0.084 ;
    END
  END fdm[127]
  PIN fdm[128]
    DIRECTION OUTPUT ;
    USE SIGNAL ;
    PORT
      LAYER M5 ;
        RECT  121.296 0 121.32 0.084 ;
    END
  END fdm[128]
  PIN fdm[129]
    DIRECTION OUTPUT ;
    USE SIGNAL ;
    PORT
      LAYER M5 ;
        RECT  121.104 0 121.128 0.084 ;
    END
  END fdm[129]
  PIN fdm[12]
    DIRECTION OUTPUT ;
    USE SIGNAL ;
    PORT
      LAYER M5 ;
        RECT  142.128 0 142.152 0.084 ;
    END
  END fdm[12]
  PIN fdm[130]
    DIRECTION OUTPUT ;
    USE SIGNAL ;
    PORT
      LAYER M5 ;
        RECT  120.96 0 120.984 0.084 ;
    END
  END fdm[130]
  PIN fdm[131]
    DIRECTION OUTPUT ;
    USE SIGNAL ;
    PORT
      LAYER M5 ;
        RECT  120.768 0 120.792 0.084 ;
    END
  END fdm[131]
  PIN fdm[132]
    DIRECTION OUTPUT ;
    USE SIGNAL ;
    PORT
      LAYER M5 ;
        RECT  120.576 0 120.6 0.084 ;
    END
  END fdm[132]
  PIN fdm[133]
    DIRECTION OUTPUT ;
    USE SIGNAL ;
    PORT
      LAYER M5 ;
        RECT  120.384 0 120.408 0.084 ;
    END
  END fdm[133]
  PIN fdm[134]
    DIRECTION OUTPUT ;
    USE SIGNAL ;
    PORT
      LAYER M5 ;
        RECT  120.24 0 120.264 0.084 ;
    END
  END fdm[134]
  PIN fdm[135]
    DIRECTION OUTPUT ;
    USE SIGNAL ;
    PORT
      LAYER M5 ;
        RECT  120.048 0 120.072 0.084 ;
    END
  END fdm[135]
  PIN fdm[136]
    DIRECTION OUTPUT ;
    USE SIGNAL ;
    PORT
      LAYER M5 ;
        RECT  119.856 0 119.88 0.084 ;
    END
  END fdm[136]
  PIN fdm[137]
    DIRECTION OUTPUT ;
    USE SIGNAL ;
    PORT
      LAYER M5 ;
        RECT  119.712 0 119.736 0.084 ;
    END
  END fdm[137]
  PIN fdm[138]
    DIRECTION OUTPUT ;
    USE SIGNAL ;
    PORT
      LAYER M5 ;
        RECT  119.52 0 119.544 0.084 ;
    END
  END fdm[138]
  PIN fdm[139]
    DIRECTION OUTPUT ;
    USE SIGNAL ;
    PORT
      LAYER M5 ;
        RECT  119.328 0 119.352 0.084 ;
    END
  END fdm[139]
  PIN fdm[13]
    DIRECTION OUTPUT ;
    USE SIGNAL ;
    PORT
      LAYER M5 ;
        RECT  141.936 0 141.96 0.084 ;
    END
  END fdm[13]
  PIN fdm[140]
    DIRECTION OUTPUT ;
    USE SIGNAL ;
    PORT
      LAYER M5 ;
        RECT  119.136 0 119.16 0.084 ;
    END
  END fdm[140]
  PIN fdm[141]
    DIRECTION OUTPUT ;
    USE SIGNAL ;
    PORT
      LAYER M5 ;
        RECT  118.992 0 119.016 0.084 ;
    END
  END fdm[141]
  PIN fdm[142]
    DIRECTION OUTPUT ;
    USE SIGNAL ;
    PORT
      LAYER M5 ;
        RECT  118.8 0 118.824 0.084 ;
    END
  END fdm[142]
  PIN fdm[143]
    DIRECTION OUTPUT ;
    USE SIGNAL ;
    PORT
      LAYER M5 ;
        RECT  118.608 0 118.632 0.084 ;
    END
  END fdm[143]
  PIN fdm[144]
    DIRECTION OUTPUT ;
    USE SIGNAL ;
    PORT
      LAYER M5 ;
        RECT  118.416 0 118.44 0.084 ;
    END
  END fdm[144]
  PIN fdm[145]
    DIRECTION OUTPUT ;
    USE SIGNAL ;
    PORT
      LAYER M5 ;
        RECT  118.272 0 118.296 0.084 ;
    END
  END fdm[145]
  PIN fdm[146]
    DIRECTION OUTPUT ;
    USE SIGNAL ;
    PORT
      LAYER M5 ;
        RECT  118.08 0 118.104 0.084 ;
    END
  END fdm[146]
  PIN fdm[147]
    DIRECTION OUTPUT ;
    USE SIGNAL ;
    PORT
      LAYER M5 ;
        RECT  117.888 0 117.912 0.084 ;
    END
  END fdm[147]
  PIN fdm[148]
    DIRECTION OUTPUT ;
    USE SIGNAL ;
    PORT
      LAYER M5 ;
        RECT  117.696 0 117.72 0.084 ;
    END
  END fdm[148]
  PIN fdm[149]
    DIRECTION OUTPUT ;
    USE SIGNAL ;
    PORT
      LAYER M5 ;
        RECT  117.552 0 117.576 0.084 ;
    END
  END fdm[149]
  PIN fdm[14]
    DIRECTION OUTPUT ;
    USE SIGNAL ;
    PORT
      LAYER M5 ;
        RECT  141.744 0 141.768 0.084 ;
    END
  END fdm[14]
  PIN fdm[150]
    DIRECTION OUTPUT ;
    USE SIGNAL ;
    PORT
      LAYER M5 ;
        RECT  117.36 0 117.384 0.084 ;
    END
  END fdm[150]
  PIN fdm[151]
    DIRECTION OUTPUT ;
    USE SIGNAL ;
    PORT
      LAYER M5 ;
        RECT  117.168 0 117.192 0.084 ;
    END
  END fdm[151]
  PIN fdm[152]
    DIRECTION OUTPUT ;
    USE SIGNAL ;
    PORT
      LAYER M5 ;
        RECT  116.976 0 117 0.084 ;
    END
  END fdm[152]
  PIN fdm[153]
    DIRECTION OUTPUT ;
    USE SIGNAL ;
    PORT
      LAYER M5 ;
        RECT  116.832 0 116.856 0.084 ;
    END
  END fdm[153]
  PIN fdm[154]
    DIRECTION OUTPUT ;
    USE SIGNAL ;
    PORT
      LAYER M5 ;
        RECT  116.64 0 116.664 0.084 ;
    END
  END fdm[154]
  PIN fdm[155]
    DIRECTION OUTPUT ;
    USE SIGNAL ;
    PORT
      LAYER M5 ;
        RECT  116.448 0 116.472 0.084 ;
    END
  END fdm[155]
  PIN fdm[156]
    DIRECTION OUTPUT ;
    USE SIGNAL ;
    PORT
      LAYER M5 ;
        RECT  116.304 0 116.328 0.084 ;
    END
  END fdm[156]
  PIN fdm[157]
    DIRECTION OUTPUT ;
    USE SIGNAL ;
    PORT
      LAYER M5 ;
        RECT  116.112 0 116.136 0.084 ;
    END
  END fdm[157]
  PIN fdm[158]
    DIRECTION OUTPUT ;
    USE SIGNAL ;
    PORT
      LAYER M5 ;
        RECT  115.92 0 115.944 0.084 ;
    END
  END fdm[158]
  PIN fdm[159]
    DIRECTION OUTPUT ;
    USE SIGNAL ;
    PORT
      LAYER M5 ;
        RECT  115.728 0 115.752 0.084 ;
    END
  END fdm[159]
  PIN fdm[15]
    DIRECTION OUTPUT ;
    USE SIGNAL ;
    PORT
      LAYER M5 ;
        RECT  141.552 0 141.576 0.084 ;
    END
  END fdm[15]
  PIN fdm[160]
    DIRECTION OUTPUT ;
    USE SIGNAL ;
    PORT
      LAYER M5 ;
        RECT  115.584 0 115.608 0.084 ;
    END
  END fdm[160]
  PIN fdm[161]
    DIRECTION OUTPUT ;
    USE SIGNAL ;
    PORT
      LAYER M5 ;
        RECT  115.392 0 115.416 0.084 ;
    END
  END fdm[161]
  PIN fdm[162]
    DIRECTION OUTPUT ;
    USE SIGNAL ;
    PORT
      LAYER M5 ;
        RECT  115.2 0 115.224 0.084 ;
    END
  END fdm[162]
  PIN fdm[163]
    DIRECTION OUTPUT ;
    USE SIGNAL ;
    PORT
      LAYER M5 ;
        RECT  115.008 0 115.032 0.084 ;
    END
  END fdm[163]
  PIN fdm[164]
    DIRECTION OUTPUT ;
    USE SIGNAL ;
    PORT
      LAYER M5 ;
        RECT  114.864 0 114.888 0.084 ;
    END
  END fdm[164]
  PIN fdm[165]
    DIRECTION OUTPUT ;
    USE SIGNAL ;
    PORT
      LAYER M5 ;
        RECT  114.672 0 114.696 0.084 ;
    END
  END fdm[165]
  PIN fdm[166]
    DIRECTION OUTPUT ;
    USE SIGNAL ;
    PORT
      LAYER M5 ;
        RECT  114.48 0 114.504 0.084 ;
    END
  END fdm[166]
  PIN fdm[167]
    DIRECTION OUTPUT ;
    USE SIGNAL ;
    PORT
      LAYER M5 ;
        RECT  114.288 0 114.312 0.084 ;
    END
  END fdm[167]
  PIN fdm[168]
    DIRECTION OUTPUT ;
    USE SIGNAL ;
    PORT
      LAYER M5 ;
        RECT  114.144 0 114.168 0.084 ;
    END
  END fdm[168]
  PIN fdm[169]
    DIRECTION OUTPUT ;
    USE SIGNAL ;
    PORT
      LAYER M5 ;
        RECT  113.952 0 113.976 0.084 ;
    END
  END fdm[169]
  PIN fdm[16]
    DIRECTION OUTPUT ;
    USE SIGNAL ;
    PORT
      LAYER M5 ;
        RECT  141.408 0 141.432 0.084 ;
    END
  END fdm[16]
  PIN fdm[170]
    DIRECTION OUTPUT ;
    USE SIGNAL ;
    PORT
      LAYER M5 ;
        RECT  113.76 0 113.784 0.084 ;
    END
  END fdm[170]
  PIN fdm[171]
    DIRECTION OUTPUT ;
    USE SIGNAL ;
    PORT
      LAYER M5 ;
        RECT  113.568 0 113.592 0.084 ;
    END
  END fdm[171]
  PIN fdm[172]
    DIRECTION OUTPUT ;
    USE SIGNAL ;
    PORT
      LAYER M5 ;
        RECT  113.424 0 113.448 0.084 ;
    END
  END fdm[172]
  PIN fdm[173]
    DIRECTION OUTPUT ;
    USE SIGNAL ;
    PORT
      LAYER M5 ;
        RECT  113.232 0 113.256 0.084 ;
    END
  END fdm[173]
  PIN fdm[174]
    DIRECTION OUTPUT ;
    USE SIGNAL ;
    PORT
      LAYER M5 ;
        RECT  113.04 0 113.064 0.084 ;
    END
  END fdm[174]
  PIN fdm[175]
    DIRECTION OUTPUT ;
    USE SIGNAL ;
    PORT
      LAYER M5 ;
        RECT  112.896 0 112.92 0.084 ;
    END
  END fdm[175]
  PIN fdm[176]
    DIRECTION OUTPUT ;
    USE SIGNAL ;
    PORT
      LAYER M5 ;
        RECT  112.704 0 112.728 0.084 ;
    END
  END fdm[176]
  PIN fdm[177]
    DIRECTION OUTPUT ;
    USE SIGNAL ;
    PORT
      LAYER M5 ;
        RECT  112.512 0 112.536 0.084 ;
    END
  END fdm[177]
  PIN fdm[178]
    DIRECTION OUTPUT ;
    USE SIGNAL ;
    PORT
      LAYER M5 ;
        RECT  112.32 0 112.344 0.084 ;
    END
  END fdm[178]
  PIN fdm[179]
    DIRECTION OUTPUT ;
    USE SIGNAL ;
    PORT
      LAYER M5 ;
        RECT  112.176 0 112.2 0.084 ;
    END
  END fdm[179]
  PIN fdm[17]
    DIRECTION OUTPUT ;
    USE SIGNAL ;
    PORT
      LAYER M5 ;
        RECT  141.216 0 141.24 0.084 ;
    END
  END fdm[17]
  PIN fdm[180]
    DIRECTION OUTPUT ;
    USE SIGNAL ;
    PORT
      LAYER M5 ;
        RECT  111.984 0 112.008 0.084 ;
    END
  END fdm[180]
  PIN fdm[181]
    DIRECTION OUTPUT ;
    USE SIGNAL ;
    PORT
      LAYER M5 ;
        RECT  111.792 0 111.816 0.084 ;
    END
  END fdm[181]
  PIN fdm[182]
    DIRECTION OUTPUT ;
    USE SIGNAL ;
    PORT
      LAYER M5 ;
        RECT  111.6 0 111.624 0.084 ;
    END
  END fdm[182]
  PIN fdm[183]
    DIRECTION OUTPUT ;
    USE SIGNAL ;
    PORT
      LAYER M5 ;
        RECT  111.456 0 111.48 0.084 ;
    END
  END fdm[183]
  PIN fdm[184]
    DIRECTION OUTPUT ;
    USE SIGNAL ;
    PORT
      LAYER M5 ;
        RECT  111.264 0 111.288 0.084 ;
    END
  END fdm[184]
  PIN fdm[185]
    DIRECTION OUTPUT ;
    USE SIGNAL ;
    PORT
      LAYER M5 ;
        RECT  111.072 0 111.096 0.084 ;
    END
  END fdm[185]
  PIN fdm[186]
    DIRECTION OUTPUT ;
    USE SIGNAL ;
    PORT
      LAYER M5 ;
        RECT  110.88 0 110.904 0.084 ;
    END
  END fdm[186]
  PIN fdm[187]
    DIRECTION OUTPUT ;
    USE SIGNAL ;
    PORT
      LAYER M5 ;
        RECT  110.736 0 110.76 0.084 ;
    END
  END fdm[187]
  PIN fdm[188]
    DIRECTION OUTPUT ;
    USE SIGNAL ;
    PORT
      LAYER M5 ;
        RECT  110.544 0 110.568 0.084 ;
    END
  END fdm[188]
  PIN fdm[189]
    DIRECTION OUTPUT ;
    USE SIGNAL ;
    PORT
      LAYER M5 ;
        RECT  110.352 0 110.376 0.084 ;
    END
  END fdm[189]
  PIN fdm[18]
    DIRECTION OUTPUT ;
    USE SIGNAL ;
    PORT
      LAYER M5 ;
        RECT  141.024 0 141.048 0.084 ;
    END
  END fdm[18]
  PIN fdm[190]
    DIRECTION OUTPUT ;
    USE SIGNAL ;
    PORT
      LAYER M5 ;
        RECT  110.16 0 110.184 0.084 ;
    END
  END fdm[190]
  PIN fdm[191]
    DIRECTION OUTPUT ;
    USE SIGNAL ;
    PORT
      LAYER M5 ;
        RECT  110.016 0 110.04 0.084 ;
    END
  END fdm[191]
  PIN fdm[192]
    DIRECTION OUTPUT ;
    USE SIGNAL ;
    PORT
      LAYER M5 ;
        RECT  109.824 0 109.848 0.084 ;
    END
  END fdm[192]
  PIN fdm[193]
    DIRECTION OUTPUT ;
    USE SIGNAL ;
    PORT
      LAYER M5 ;
        RECT  109.632 0 109.656 0.084 ;
    END
  END fdm[193]
  PIN fdm[194]
    DIRECTION OUTPUT ;
    USE SIGNAL ;
    PORT
      LAYER M5 ;
        RECT  109.488 0 109.512 0.084 ;
    END
  END fdm[194]
  PIN fdm[195]
    DIRECTION OUTPUT ;
    USE SIGNAL ;
    PORT
      LAYER M5 ;
        RECT  109.296 0 109.32 0.084 ;
    END
  END fdm[195]
  PIN fdm[196]
    DIRECTION OUTPUT ;
    USE SIGNAL ;
    PORT
      LAYER M5 ;
        RECT  109.104 0 109.128 0.084 ;
    END
  END fdm[196]
  PIN fdm[197]
    DIRECTION OUTPUT ;
    USE SIGNAL ;
    PORT
      LAYER M5 ;
        RECT  108.912 0 108.936 0.084 ;
    END
  END fdm[197]
  PIN fdm[198]
    DIRECTION OUTPUT ;
    USE SIGNAL ;
    PORT
      LAYER M5 ;
        RECT  108.768 0 108.792 0.084 ;
    END
  END fdm[198]
  PIN fdm[199]
    DIRECTION OUTPUT ;
    USE SIGNAL ;
    PORT
      LAYER M5 ;
        RECT  108.576 0 108.6 0.084 ;
    END
  END fdm[199]
  PIN fdm[19]
    DIRECTION OUTPUT ;
    USE SIGNAL ;
    PORT
      LAYER M5 ;
        RECT  140.832 0 140.856 0.084 ;
    END
  END fdm[19]
  PIN fdm[1]
    DIRECTION OUTPUT ;
    USE SIGNAL ;
    PORT
      LAYER M5 ;
        RECT  144.096 0 144.12 0.084 ;
    END
  END fdm[1]
  PIN fdm[200]
    DIRECTION OUTPUT ;
    USE SIGNAL ;
    PORT
      LAYER M5 ;
        RECT  108.384 0 108.408 0.084 ;
    END
  END fdm[200]
  PIN fdm[201]
    DIRECTION OUTPUT ;
    USE SIGNAL ;
    PORT
      LAYER M5 ;
        RECT  108.192 0 108.216 0.084 ;
    END
  END fdm[201]
  PIN fdm[202]
    DIRECTION OUTPUT ;
    USE SIGNAL ;
    PORT
      LAYER M5 ;
        RECT  108.048 0 108.072 0.084 ;
    END
  END fdm[202]
  PIN fdm[203]
    DIRECTION OUTPUT ;
    USE SIGNAL ;
    PORT
      LAYER M5 ;
        RECT  107.856 0 107.88 0.084 ;
    END
  END fdm[203]
  PIN fdm[204]
    DIRECTION OUTPUT ;
    USE SIGNAL ;
    PORT
      LAYER M5 ;
        RECT  107.664 0 107.688 0.084 ;
    END
  END fdm[204]
  PIN fdm[205]
    DIRECTION OUTPUT ;
    USE SIGNAL ;
    PORT
      LAYER M5 ;
        RECT  107.472 0 107.496 0.084 ;
    END
  END fdm[205]
  PIN fdm[206]
    DIRECTION OUTPUT ;
    USE SIGNAL ;
    PORT
      LAYER M5 ;
        RECT  107.328 0 107.352 0.084 ;
    END
  END fdm[206]
  PIN fdm[207]
    DIRECTION OUTPUT ;
    USE SIGNAL ;
    PORT
      LAYER M5 ;
        RECT  107.136 0 107.16 0.084 ;
    END
  END fdm[207]
  PIN fdm[208]
    DIRECTION OUTPUT ;
    USE SIGNAL ;
    PORT
      LAYER M5 ;
        RECT  106.944 0 106.968 0.084 ;
    END
  END fdm[208]
  PIN fdm[209]
    DIRECTION OUTPUT ;
    USE SIGNAL ;
    PORT
      LAYER M5 ;
        RECT  106.752 0 106.776 0.084 ;
    END
  END fdm[209]
  PIN fdm[20]
    DIRECTION OUTPUT ;
    USE SIGNAL ;
    PORT
      LAYER M5 ;
        RECT  140.688 0 140.712 0.084 ;
    END
  END fdm[20]
  PIN fdm[210]
    DIRECTION OUTPUT ;
    USE SIGNAL ;
    PORT
      LAYER M5 ;
        RECT  106.608 0 106.632 0.084 ;
    END
  END fdm[210]
  PIN fdm[211]
    DIRECTION OUTPUT ;
    USE SIGNAL ;
    PORT
      LAYER M5 ;
        RECT  106.416 0 106.44 0.084 ;
    END
  END fdm[211]
  PIN fdm[212]
    DIRECTION OUTPUT ;
    USE SIGNAL ;
    PORT
      LAYER M5 ;
        RECT  106.224 0 106.248 0.084 ;
    END
  END fdm[212]
  PIN fdm[213]
    DIRECTION OUTPUT ;
    USE SIGNAL ;
    PORT
      LAYER M5 ;
        RECT  106.08 0 106.104 0.084 ;
    END
  END fdm[213]
  PIN fdm[214]
    DIRECTION OUTPUT ;
    USE SIGNAL ;
    PORT
      LAYER M5 ;
        RECT  105.888 0 105.912 0.084 ;
    END
  END fdm[214]
  PIN fdm[215]
    DIRECTION OUTPUT ;
    USE SIGNAL ;
    PORT
      LAYER M5 ;
        RECT  105.696 0 105.72 0.084 ;
    END
  END fdm[215]
  PIN fdm[216]
    DIRECTION OUTPUT ;
    USE SIGNAL ;
    PORT
      LAYER M5 ;
        RECT  105.504 0 105.528 0.084 ;
    END
  END fdm[216]
  PIN fdm[217]
    DIRECTION OUTPUT ;
    USE SIGNAL ;
    PORT
      LAYER M5 ;
        RECT  105.36 0 105.384 0.084 ;
    END
  END fdm[217]
  PIN fdm[218]
    DIRECTION OUTPUT ;
    USE SIGNAL ;
    PORT
      LAYER M5 ;
        RECT  105.168 0 105.192 0.084 ;
    END
  END fdm[218]
  PIN fdm[219]
    DIRECTION OUTPUT ;
    USE SIGNAL ;
    PORT
      LAYER M5 ;
        RECT  104.976 0 105 0.084 ;
    END
  END fdm[219]
  PIN fdm[21]
    DIRECTION OUTPUT ;
    USE SIGNAL ;
    PORT
      LAYER M5 ;
        RECT  140.496 0 140.52 0.084 ;
    END
  END fdm[21]
  PIN fdm[220]
    DIRECTION OUTPUT ;
    USE SIGNAL ;
    PORT
      LAYER M5 ;
        RECT  104.784 0 104.808 0.084 ;
    END
  END fdm[220]
  PIN fdm[221]
    DIRECTION OUTPUT ;
    USE SIGNAL ;
    PORT
      LAYER M5 ;
        RECT  104.64 0 104.664 0.084 ;
    END
  END fdm[221]
  PIN fdm[222]
    DIRECTION OUTPUT ;
    USE SIGNAL ;
    PORT
      LAYER M5 ;
        RECT  104.448 0 104.472 0.084 ;
    END
  END fdm[222]
  PIN fdm[223]
    DIRECTION OUTPUT ;
    USE SIGNAL ;
    PORT
      LAYER M5 ;
        RECT  104.256 0 104.28 0.084 ;
    END
  END fdm[223]
  PIN fdm[224]
    DIRECTION OUTPUT ;
    USE SIGNAL ;
    PORT
      LAYER M5 ;
        RECT  104.064 0 104.088 0.084 ;
    END
  END fdm[224]
  PIN fdm[225]
    DIRECTION OUTPUT ;
    USE SIGNAL ;
    PORT
      LAYER M5 ;
        RECT  103.92 0 103.944 0.084 ;
    END
  END fdm[225]
  PIN fdm[226]
    DIRECTION OUTPUT ;
    USE SIGNAL ;
    PORT
      LAYER M5 ;
        RECT  103.728 0 103.752 0.084 ;
    END
  END fdm[226]
  PIN fdm[227]
    DIRECTION OUTPUT ;
    USE SIGNAL ;
    PORT
      LAYER M5 ;
        RECT  103.536 0 103.56 0.084 ;
    END
  END fdm[227]
  PIN fdm[228]
    DIRECTION OUTPUT ;
    USE SIGNAL ;
    PORT
      LAYER M5 ;
        RECT  103.392 0 103.416 0.084 ;
    END
  END fdm[228]
  PIN fdm[229]
    DIRECTION OUTPUT ;
    USE SIGNAL ;
    PORT
      LAYER M5 ;
        RECT  103.2 0 103.224 0.084 ;
    END
  END fdm[229]
  PIN fdm[22]
    DIRECTION OUTPUT ;
    USE SIGNAL ;
    PORT
      LAYER M5 ;
        RECT  140.304 0 140.328 0.084 ;
    END
  END fdm[22]
  PIN fdm[230]
    DIRECTION OUTPUT ;
    USE SIGNAL ;
    PORT
      LAYER M5 ;
        RECT  103.008 0 103.032 0.084 ;
    END
  END fdm[230]
  PIN fdm[231]
    DIRECTION OUTPUT ;
    USE SIGNAL ;
    PORT
      LAYER M5 ;
        RECT  102.816 0 102.84 0.084 ;
    END
  END fdm[231]
  PIN fdm[232]
    DIRECTION OUTPUT ;
    USE SIGNAL ;
    PORT
      LAYER M5 ;
        RECT  102.672 0 102.696 0.084 ;
    END
  END fdm[232]
  PIN fdm[233]
    DIRECTION OUTPUT ;
    USE SIGNAL ;
    PORT
      LAYER M5 ;
        RECT  102.48 0 102.504 0.084 ;
    END
  END fdm[233]
  PIN fdm[234]
    DIRECTION OUTPUT ;
    USE SIGNAL ;
    PORT
      LAYER M5 ;
        RECT  102.288 0 102.312 0.084 ;
    END
  END fdm[234]
  PIN fdm[235]
    DIRECTION OUTPUT ;
    USE SIGNAL ;
    PORT
      LAYER M5 ;
        RECT  102.096 0 102.12 0.084 ;
    END
  END fdm[235]
  PIN fdm[236]
    DIRECTION OUTPUT ;
    USE SIGNAL ;
    PORT
      LAYER M5 ;
        RECT  101.952 0 101.976 0.084 ;
    END
  END fdm[236]
  PIN fdm[237]
    DIRECTION OUTPUT ;
    USE SIGNAL ;
    PORT
      LAYER M5 ;
        RECT  101.76 0 101.784 0.084 ;
    END
  END fdm[237]
  PIN fdm[238]
    DIRECTION OUTPUT ;
    USE SIGNAL ;
    PORT
      LAYER M5 ;
        RECT  101.568 0 101.592 0.084 ;
    END
  END fdm[238]
  PIN fdm[239]
    DIRECTION OUTPUT ;
    USE SIGNAL ;
    PORT
      LAYER M5 ;
        RECT  101.376 0 101.4 0.084 ;
    END
  END fdm[239]
  PIN fdm[23]
    DIRECTION OUTPUT ;
    USE SIGNAL ;
    PORT
      LAYER M5 ;
        RECT  140.112 0 140.136 0.084 ;
    END
  END fdm[23]
  PIN fdm[240]
    DIRECTION OUTPUT ;
    USE SIGNAL ;
    PORT
      LAYER M5 ;
        RECT  101.232 0 101.256 0.084 ;
    END
  END fdm[240]
  PIN fdm[241]
    DIRECTION OUTPUT ;
    USE SIGNAL ;
    PORT
      LAYER M5 ;
        RECT  101.04 0 101.064 0.084 ;
    END
  END fdm[241]
  PIN fdm[242]
    DIRECTION OUTPUT ;
    USE SIGNAL ;
    PORT
      LAYER M5 ;
        RECT  100.848 0 100.872 0.084 ;
    END
  END fdm[242]
  PIN fdm[243]
    DIRECTION OUTPUT ;
    USE SIGNAL ;
    PORT
      LAYER M5 ;
        RECT  100.656 0 100.68 0.084 ;
    END
  END fdm[243]
  PIN fdm[244]
    DIRECTION OUTPUT ;
    USE SIGNAL ;
    PORT
      LAYER M5 ;
        RECT  100.512 0 100.536 0.084 ;
    END
  END fdm[244]
  PIN fdm[245]
    DIRECTION OUTPUT ;
    USE SIGNAL ;
    PORT
      LAYER M5 ;
        RECT  100.32 0 100.344 0.084 ;
    END
  END fdm[245]
  PIN fdm[246]
    DIRECTION OUTPUT ;
    USE SIGNAL ;
    PORT
      LAYER M5 ;
        RECT  100.128 0 100.152 0.084 ;
    END
  END fdm[246]
  PIN fdm[247]
    DIRECTION OUTPUT ;
    USE SIGNAL ;
    PORT
      LAYER M5 ;
        RECT  99.984 0 100.008 0.084 ;
    END
  END fdm[247]
  PIN fdm[248]
    DIRECTION OUTPUT ;
    USE SIGNAL ;
    PORT
      LAYER M5 ;
        RECT  99.792 0 99.816 0.084 ;
    END
  END fdm[248]
  PIN fdm[249]
    DIRECTION OUTPUT ;
    USE SIGNAL ;
    PORT
      LAYER M5 ;
        RECT  99.6 0 99.624 0.084 ;
    END
  END fdm[249]
  PIN fdm[24]
    DIRECTION OUTPUT ;
    USE SIGNAL ;
    PORT
      LAYER M5 ;
        RECT  139.968 0 139.992 0.084 ;
    END
  END fdm[24]
  PIN fdm[250]
    DIRECTION OUTPUT ;
    USE SIGNAL ;
    PORT
      LAYER M5 ;
        RECT  99.408 0 99.432 0.084 ;
    END
  END fdm[250]
  PIN fdm[251]
    DIRECTION OUTPUT ;
    USE SIGNAL ;
    PORT
      LAYER M5 ;
        RECT  99.264 0 99.288 0.084 ;
    END
  END fdm[251]
  PIN fdm[252]
    DIRECTION OUTPUT ;
    USE SIGNAL ;
    PORT
      LAYER M5 ;
        RECT  99.072 0 99.096 0.084 ;
    END
  END fdm[252]
  PIN fdm[253]
    DIRECTION OUTPUT ;
    USE SIGNAL ;
    PORT
      LAYER M5 ;
        RECT  98.88 0 98.904 0.084 ;
    END
  END fdm[253]
  PIN fdm[254]
    DIRECTION OUTPUT ;
    USE SIGNAL ;
    PORT
      LAYER M5 ;
        RECT  98.688 0 98.712 0.084 ;
    END
  END fdm[254]
  PIN fdm[255]
    DIRECTION OUTPUT ;
    USE SIGNAL ;
    PORT
      LAYER M5 ;
        RECT  98.544 0 98.568 0.084 ;
    END
  END fdm[255]
  PIN fdm[256]
    DIRECTION OUTPUT ;
    USE SIGNAL ;
    PORT
      LAYER M5 ;
        RECT  98.352 0 98.376 0.084 ;
    END
  END fdm[256]
  PIN fdm[257]
    DIRECTION OUTPUT ;
    USE SIGNAL ;
    PORT
      LAYER M5 ;
        RECT  98.16 0 98.184 0.084 ;
    END
  END fdm[257]
  PIN fdm[258]
    DIRECTION OUTPUT ;
    USE SIGNAL ;
    PORT
      LAYER M5 ;
        RECT  97.968 0 97.992 0.084 ;
    END
  END fdm[258]
  PIN fdm[259]
    DIRECTION OUTPUT ;
    USE SIGNAL ;
    PORT
      LAYER M5 ;
        RECT  97.824 0 97.848 0.084 ;
    END
  END fdm[259]
  PIN fdm[25]
    DIRECTION OUTPUT ;
    USE SIGNAL ;
    PORT
      LAYER M5 ;
        RECT  139.776 0 139.8 0.084 ;
    END
  END fdm[25]
  PIN fdm[260]
    DIRECTION OUTPUT ;
    USE SIGNAL ;
    PORT
      LAYER M5 ;
        RECT  97.632 0 97.656 0.084 ;
    END
  END fdm[260]
  PIN fdm[261]
    DIRECTION OUTPUT ;
    USE SIGNAL ;
    PORT
      LAYER M5 ;
        RECT  97.44 0 97.464 0.084 ;
    END
  END fdm[261]
  PIN fdm[262]
    DIRECTION OUTPUT ;
    USE SIGNAL ;
    PORT
      LAYER M5 ;
        RECT  97.248 0 97.272 0.084 ;
    END
  END fdm[262]
  PIN fdm[263]
    DIRECTION OUTPUT ;
    USE SIGNAL ;
    PORT
      LAYER M5 ;
        RECT  97.104 0 97.128 0.084 ;
    END
  END fdm[263]
  PIN fdm[264]
    DIRECTION OUTPUT ;
    USE SIGNAL ;
    PORT
      LAYER M5 ;
        RECT  96.912 0 96.936 0.084 ;
    END
  END fdm[264]
  PIN fdm[265]
    DIRECTION OUTPUT ;
    USE SIGNAL ;
    PORT
      LAYER M5 ;
        RECT  96.72 0 96.744 0.084 ;
    END
  END fdm[265]
  PIN fdm[266]
    DIRECTION OUTPUT ;
    USE SIGNAL ;
    PORT
      LAYER M5 ;
        RECT  96.576 0 96.6 0.084 ;
    END
  END fdm[266]
  PIN fdm[267]
    DIRECTION OUTPUT ;
    USE SIGNAL ;
    PORT
      LAYER M5 ;
        RECT  96.384 0 96.408 0.084 ;
    END
  END fdm[267]
  PIN fdm[268]
    DIRECTION OUTPUT ;
    USE SIGNAL ;
    PORT
      LAYER M5 ;
        RECT  96.192 0 96.216 0.084 ;
    END
  END fdm[268]
  PIN fdm[269]
    DIRECTION OUTPUT ;
    USE SIGNAL ;
    PORT
      LAYER M5 ;
        RECT  96 0 96.024 0.084 ;
    END
  END fdm[269]
  PIN fdm[26]
    DIRECTION OUTPUT ;
    USE SIGNAL ;
    PORT
      LAYER M5 ;
        RECT  139.584 0 139.608 0.084 ;
    END
  END fdm[26]
  PIN fdm[270]
    DIRECTION OUTPUT ;
    USE SIGNAL ;
    PORT
      LAYER M5 ;
        RECT  95.856 0 95.88 0.084 ;
    END
  END fdm[270]
  PIN fdm[271]
    DIRECTION OUTPUT ;
    USE SIGNAL ;
    PORT
      LAYER M5 ;
        RECT  95.664 0 95.688 0.084 ;
    END
  END fdm[271]
  PIN fdm[272]
    DIRECTION OUTPUT ;
    USE SIGNAL ;
    PORT
      LAYER M5 ;
        RECT  95.472 0 95.496 0.084 ;
    END
  END fdm[272]
  PIN fdm[273]
    DIRECTION OUTPUT ;
    USE SIGNAL ;
    PORT
      LAYER M5 ;
        RECT  95.28 0 95.304 0.084 ;
    END
  END fdm[273]
  PIN fdm[274]
    DIRECTION OUTPUT ;
    USE SIGNAL ;
    PORT
      LAYER M5 ;
        RECT  95.136 0 95.16 0.084 ;
    END
  END fdm[274]
  PIN fdm[275]
    DIRECTION OUTPUT ;
    USE SIGNAL ;
    PORT
      LAYER M5 ;
        RECT  94.944 0 94.968 0.084 ;
    END
  END fdm[275]
  PIN fdm[276]
    DIRECTION OUTPUT ;
    USE SIGNAL ;
    PORT
      LAYER M5 ;
        RECT  94.752 0 94.776 0.084 ;
    END
  END fdm[276]
  PIN fdm[277]
    DIRECTION OUTPUT ;
    USE SIGNAL ;
    PORT
      LAYER M5 ;
        RECT  94.56 0 94.584 0.084 ;
    END
  END fdm[277]
  PIN fdm[278]
    DIRECTION OUTPUT ;
    USE SIGNAL ;
    PORT
      LAYER M5 ;
        RECT  94.416 0 94.44 0.084 ;
    END
  END fdm[278]
  PIN fdm[279]
    DIRECTION OUTPUT ;
    USE SIGNAL ;
    PORT
      LAYER M5 ;
        RECT  94.224 0 94.248 0.084 ;
    END
  END fdm[279]
  PIN fdm[27]
    DIRECTION OUTPUT ;
    USE SIGNAL ;
    PORT
      LAYER M5 ;
        RECT  139.392 0 139.416 0.084 ;
    END
  END fdm[27]
  PIN fdm[280]
    DIRECTION OUTPUT ;
    USE SIGNAL ;
    PORT
      LAYER M5 ;
        RECT  94.032 0 94.056 0.084 ;
    END
  END fdm[280]
  PIN fdm[281]
    DIRECTION OUTPUT ;
    USE SIGNAL ;
    PORT
      LAYER M5 ;
        RECT  93.84 0 93.864 0.084 ;
    END
  END fdm[281]
  PIN fdm[282]
    DIRECTION OUTPUT ;
    USE SIGNAL ;
    PORT
      LAYER M5 ;
        RECT  93.696 0 93.72 0.084 ;
    END
  END fdm[282]
  PIN fdm[283]
    DIRECTION OUTPUT ;
    USE SIGNAL ;
    PORT
      LAYER M5 ;
        RECT  93.504 0 93.528 0.084 ;
    END
  END fdm[283]
  PIN fdm[284]
    DIRECTION OUTPUT ;
    USE SIGNAL ;
    PORT
      LAYER M5 ;
        RECT  93.312 0 93.336 0.084 ;
    END
  END fdm[284]
  PIN fdm[285]
    DIRECTION OUTPUT ;
    USE SIGNAL ;
    PORT
      LAYER M5 ;
        RECT  93.168 0 93.192 0.084 ;
    END
  END fdm[285]
  PIN fdm[286]
    DIRECTION OUTPUT ;
    USE SIGNAL ;
    PORT
      LAYER M5 ;
        RECT  92.976 0 93 0.084 ;
    END
  END fdm[286]
  PIN fdm[287]
    DIRECTION OUTPUT ;
    USE SIGNAL ;
    PORT
      LAYER M5 ;
        RECT  92.784 0 92.808 0.084 ;
    END
  END fdm[287]
  PIN fdm[288]
    DIRECTION OUTPUT ;
    USE SIGNAL ;
    PORT
      LAYER M5 ;
        RECT  92.592 0 92.616 0.084 ;
    END
  END fdm[288]
  PIN fdm[289]
    DIRECTION OUTPUT ;
    USE SIGNAL ;
    PORT
      LAYER M5 ;
        RECT  92.448 0 92.472 0.084 ;
    END
  END fdm[289]
  PIN fdm[28]
    DIRECTION OUTPUT ;
    USE SIGNAL ;
    PORT
      LAYER M5 ;
        RECT  139.248 0 139.272 0.084 ;
    END
  END fdm[28]
  PIN fdm[290]
    DIRECTION OUTPUT ;
    USE SIGNAL ;
    PORT
      LAYER M5 ;
        RECT  92.256 0 92.28 0.084 ;
    END
  END fdm[290]
  PIN fdm[291]
    DIRECTION OUTPUT ;
    USE SIGNAL ;
    PORT
      LAYER M5 ;
        RECT  92.064 0 92.088 0.084 ;
    END
  END fdm[291]
  PIN fdm[292]
    DIRECTION OUTPUT ;
    USE SIGNAL ;
    PORT
      LAYER M5 ;
        RECT  91.872 0 91.896 0.084 ;
    END
  END fdm[292]
  PIN fdm[293]
    DIRECTION OUTPUT ;
    USE SIGNAL ;
    PORT
      LAYER M5 ;
        RECT  91.728 0 91.752 0.084 ;
    END
  END fdm[293]
  PIN fdm[294]
    DIRECTION OUTPUT ;
    USE SIGNAL ;
    PORT
      LAYER M5 ;
        RECT  91.536 0 91.56 0.084 ;
    END
  END fdm[294]
  PIN fdm[295]
    DIRECTION OUTPUT ;
    USE SIGNAL ;
    PORT
      LAYER M5 ;
        RECT  91.344 0 91.368 0.084 ;
    END
  END fdm[295]
  PIN fdm[296]
    DIRECTION OUTPUT ;
    USE SIGNAL ;
    PORT
      LAYER M5 ;
        RECT  91.152 0 91.176 0.084 ;
    END
  END fdm[296]
  PIN fdm[297]
    DIRECTION OUTPUT ;
    USE SIGNAL ;
    PORT
      LAYER M5 ;
        RECT  91.008 0 91.032 0.084 ;
    END
  END fdm[297]
  PIN fdm[298]
    DIRECTION OUTPUT ;
    USE SIGNAL ;
    PORT
      LAYER M5 ;
        RECT  90.816 0 90.84 0.084 ;
    END
  END fdm[298]
  PIN fdm[299]
    DIRECTION OUTPUT ;
    USE SIGNAL ;
    PORT
      LAYER M5 ;
        RECT  90.624 0 90.648 0.084 ;
    END
  END fdm[299]
  PIN fdm[29]
    DIRECTION OUTPUT ;
    USE SIGNAL ;
    PORT
      LAYER M5 ;
        RECT  139.056 0 139.08 0.084 ;
    END
  END fdm[29]
  PIN fdm[2]
    DIRECTION OUTPUT ;
    USE SIGNAL ;
    PORT
      LAYER M5 ;
        RECT  143.904 0 143.928 0.084 ;
    END
  END fdm[2]
  PIN fdm[300]
    DIRECTION OUTPUT ;
    USE SIGNAL ;
    PORT
      LAYER M5 ;
        RECT  90.432 0 90.456 0.084 ;
    END
  END fdm[300]
  PIN fdm[301]
    DIRECTION OUTPUT ;
    USE SIGNAL ;
    PORT
      LAYER M5 ;
        RECT  90.288 0 90.312 0.084 ;
    END
  END fdm[301]
  PIN fdm[302]
    DIRECTION OUTPUT ;
    USE SIGNAL ;
    PORT
      LAYER M5 ;
        RECT  90.096 0 90.12 0.084 ;
    END
  END fdm[302]
  PIN fdm[303]
    DIRECTION OUTPUT ;
    USE SIGNAL ;
    PORT
      LAYER M5 ;
        RECT  89.904 0 89.928 0.084 ;
    END
  END fdm[303]
  PIN fdm[304]
    DIRECTION OUTPUT ;
    USE SIGNAL ;
    PORT
      LAYER M5 ;
        RECT  89.76 0 89.784 0.084 ;
    END
  END fdm[304]
  PIN fdm[305]
    DIRECTION OUTPUT ;
    USE SIGNAL ;
    PORT
      LAYER M5 ;
        RECT  89.568 0 89.592 0.084 ;
    END
  END fdm[305]
  PIN fdm[306]
    DIRECTION OUTPUT ;
    USE SIGNAL ;
    PORT
      LAYER M5 ;
        RECT  89.376 0 89.4 0.084 ;
    END
  END fdm[306]
  PIN fdm[307]
    DIRECTION OUTPUT ;
    USE SIGNAL ;
    PORT
      LAYER M5 ;
        RECT  89.184 0 89.208 0.084 ;
    END
  END fdm[307]
  PIN fdm[308]
    DIRECTION OUTPUT ;
    USE SIGNAL ;
    PORT
      LAYER M5 ;
        RECT  89.04 0 89.064 0.084 ;
    END
  END fdm[308]
  PIN fdm[309]
    DIRECTION OUTPUT ;
    USE SIGNAL ;
    PORT
      LAYER M5 ;
        RECT  88.848 0 88.872 0.084 ;
    END
  END fdm[309]
  PIN fdm[30]
    DIRECTION OUTPUT ;
    USE SIGNAL ;
    PORT
      LAYER M5 ;
        RECT  138.864 0 138.888 0.084 ;
    END
  END fdm[30]
  PIN fdm[310]
    DIRECTION OUTPUT ;
    USE SIGNAL ;
    PORT
      LAYER M5 ;
        RECT  88.656 0 88.68 0.084 ;
    END
  END fdm[310]
  PIN fdm[311]
    DIRECTION OUTPUT ;
    USE SIGNAL ;
    PORT
      LAYER M5 ;
        RECT  88.464 0 88.488 0.084 ;
    END
  END fdm[311]
  PIN fdm[312]
    DIRECTION OUTPUT ;
    USE SIGNAL ;
    PORT
      LAYER M5 ;
        RECT  88.32 0 88.344 0.084 ;
    END
  END fdm[312]
  PIN fdm[313]
    DIRECTION OUTPUT ;
    USE SIGNAL ;
    PORT
      LAYER M5 ;
        RECT  88.128 0 88.152 0.084 ;
    END
  END fdm[313]
  PIN fdm[314]
    DIRECTION OUTPUT ;
    USE SIGNAL ;
    PORT
      LAYER M5 ;
        RECT  37.92 0 37.944 0.084 ;
    END
  END fdm[314]
  PIN fdm[315]
    DIRECTION OUTPUT ;
    USE SIGNAL ;
    PORT
      LAYER M5 ;
        RECT  37.728 0 37.752 0.084 ;
    END
  END fdm[315]
  PIN fdm[316]
    DIRECTION OUTPUT ;
    USE SIGNAL ;
    PORT
      LAYER M5 ;
        RECT  37.584 0 37.608 0.084 ;
    END
  END fdm[316]
  PIN fdm[317]
    DIRECTION OUTPUT ;
    USE SIGNAL ;
    PORT
      LAYER M5 ;
        RECT  37.392 0 37.416 0.084 ;
    END
  END fdm[317]
  PIN fdm[318]
    DIRECTION OUTPUT ;
    USE SIGNAL ;
    PORT
      LAYER M5 ;
        RECT  37.2 0 37.224 0.084 ;
    END
  END fdm[318]
  PIN fdm[319]
    DIRECTION OUTPUT ;
    USE SIGNAL ;
    PORT
      LAYER M5 ;
        RECT  37.008 0 37.032 0.084 ;
    END
  END fdm[319]
  PIN fdm[31]
    DIRECTION OUTPUT ;
    USE SIGNAL ;
    PORT
      LAYER M5 ;
        RECT  138.72 0 138.744 0.084 ;
    END
  END fdm[31]
  PIN fdm[320]
    DIRECTION OUTPUT ;
    USE SIGNAL ;
    PORT
      LAYER M5 ;
        RECT  36.864 0 36.888 0.084 ;
    END
  END fdm[320]
  PIN fdm[321]
    DIRECTION OUTPUT ;
    USE SIGNAL ;
    PORT
      LAYER M5 ;
        RECT  36.672 0 36.696 0.084 ;
    END
  END fdm[321]
  PIN fdm[322]
    DIRECTION OUTPUT ;
    USE SIGNAL ;
    PORT
      LAYER M5 ;
        RECT  36.48 0 36.504 0.084 ;
    END
  END fdm[322]
  PIN fdm[323]
    DIRECTION OUTPUT ;
    USE SIGNAL ;
    PORT
      LAYER M5 ;
        RECT  36.336 0 36.36 0.084 ;
    END
  END fdm[323]
  PIN fdm[324]
    DIRECTION OUTPUT ;
    USE SIGNAL ;
    PORT
      LAYER M5 ;
        RECT  36.144 0 36.168 0.084 ;
    END
  END fdm[324]
  PIN fdm[325]
    DIRECTION OUTPUT ;
    USE SIGNAL ;
    PORT
      LAYER M5 ;
        RECT  35.952 0 35.976 0.084 ;
    END
  END fdm[325]
  PIN fdm[326]
    DIRECTION OUTPUT ;
    USE SIGNAL ;
    PORT
      LAYER M5 ;
        RECT  35.76 0 35.784 0.084 ;
    END
  END fdm[326]
  PIN fdm[327]
    DIRECTION OUTPUT ;
    USE SIGNAL ;
    PORT
      LAYER M5 ;
        RECT  35.616 0 35.64 0.084 ;
    END
  END fdm[327]
  PIN fdm[328]
    DIRECTION OUTPUT ;
    USE SIGNAL ;
    PORT
      LAYER M5 ;
        RECT  35.424 0 35.448 0.084 ;
    END
  END fdm[328]
  PIN fdm[329]
    DIRECTION OUTPUT ;
    USE SIGNAL ;
    PORT
      LAYER M5 ;
        RECT  35.232 0 35.256 0.084 ;
    END
  END fdm[329]
  PIN fdm[32]
    DIRECTION OUTPUT ;
    USE SIGNAL ;
    PORT
      LAYER M5 ;
        RECT  138.528 0 138.552 0.084 ;
    END
  END fdm[32]
  PIN fdm[330]
    DIRECTION OUTPUT ;
    USE SIGNAL ;
    PORT
      LAYER M5 ;
        RECT  35.04 0 35.064 0.084 ;
    END
  END fdm[330]
  PIN fdm[331]
    DIRECTION OUTPUT ;
    USE SIGNAL ;
    PORT
      LAYER M5 ;
        RECT  34.896 0 34.92 0.084 ;
    END
  END fdm[331]
  PIN fdm[332]
    DIRECTION OUTPUT ;
    USE SIGNAL ;
    PORT
      LAYER M5 ;
        RECT  34.704 0 34.728 0.084 ;
    END
  END fdm[332]
  PIN fdm[333]
    DIRECTION OUTPUT ;
    USE SIGNAL ;
    PORT
      LAYER M5 ;
        RECT  34.512 0 34.536 0.084 ;
    END
  END fdm[333]
  PIN fdm[334]
    DIRECTION OUTPUT ;
    USE SIGNAL ;
    PORT
      LAYER M5 ;
        RECT  34.32 0 34.344 0.084 ;
    END
  END fdm[334]
  PIN fdm[335]
    DIRECTION OUTPUT ;
    USE SIGNAL ;
    PORT
      LAYER M5 ;
        RECT  34.176 0 34.2 0.084 ;
    END
  END fdm[335]
  PIN fdm[336]
    DIRECTION OUTPUT ;
    USE SIGNAL ;
    PORT
      LAYER M5 ;
        RECT  33.984 0 34.008 0.084 ;
    END
  END fdm[336]
  PIN fdm[337]
    DIRECTION OUTPUT ;
    USE SIGNAL ;
    PORT
      LAYER M5 ;
        RECT  33.792 0 33.816 0.084 ;
    END
  END fdm[337]
  PIN fdm[338]
    DIRECTION OUTPUT ;
    USE SIGNAL ;
    PORT
      LAYER M5 ;
        RECT  33.648 0 33.672 0.084 ;
    END
  END fdm[338]
  PIN fdm[339]
    DIRECTION OUTPUT ;
    USE SIGNAL ;
    PORT
      LAYER M5 ;
        RECT  33.456 0 33.48 0.084 ;
    END
  END fdm[339]
  PIN fdm[33]
    DIRECTION OUTPUT ;
    USE SIGNAL ;
    PORT
      LAYER M5 ;
        RECT  138.336 0 138.36 0.084 ;
    END
  END fdm[33]
  PIN fdm[340]
    DIRECTION OUTPUT ;
    USE SIGNAL ;
    PORT
      LAYER M5 ;
        RECT  33.264 0 33.288 0.084 ;
    END
  END fdm[340]
  PIN fdm[341]
    DIRECTION OUTPUT ;
    USE SIGNAL ;
    PORT
      LAYER M5 ;
        RECT  33.072 0 33.096 0.084 ;
    END
  END fdm[341]
  PIN fdm[342]
    DIRECTION OUTPUT ;
    USE SIGNAL ;
    PORT
      LAYER M5 ;
        RECT  32.928 0 32.952 0.084 ;
    END
  END fdm[342]
  PIN fdm[343]
    DIRECTION OUTPUT ;
    USE SIGNAL ;
    PORT
      LAYER M5 ;
        RECT  32.736 0 32.76 0.084 ;
    END
  END fdm[343]
  PIN fdm[344]
    DIRECTION OUTPUT ;
    USE SIGNAL ;
    PORT
      LAYER M5 ;
        RECT  32.544 0 32.568 0.084 ;
    END
  END fdm[344]
  PIN fdm[345]
    DIRECTION OUTPUT ;
    USE SIGNAL ;
    PORT
      LAYER M5 ;
        RECT  32.352 0 32.376 0.084 ;
    END
  END fdm[345]
  PIN fdm[346]
    DIRECTION OUTPUT ;
    USE SIGNAL ;
    PORT
      LAYER M5 ;
        RECT  32.208 0 32.232 0.084 ;
    END
  END fdm[346]
  PIN fdm[347]
    DIRECTION OUTPUT ;
    USE SIGNAL ;
    PORT
      LAYER M5 ;
        RECT  32.016 0 32.04 0.084 ;
    END
  END fdm[347]
  PIN fdm[348]
    DIRECTION OUTPUT ;
    USE SIGNAL ;
    PORT
      LAYER M5 ;
        RECT  31.824 0 31.848 0.084 ;
    END
  END fdm[348]
  PIN fdm[349]
    DIRECTION OUTPUT ;
    USE SIGNAL ;
    PORT
      LAYER M5 ;
        RECT  31.632 0 31.656 0.084 ;
    END
  END fdm[349]
  PIN fdm[34]
    DIRECTION OUTPUT ;
    USE SIGNAL ;
    PORT
      LAYER M5 ;
        RECT  138.144 0 138.168 0.084 ;
    END
  END fdm[34]
  PIN fdm[350]
    DIRECTION OUTPUT ;
    USE SIGNAL ;
    PORT
      LAYER M5 ;
        RECT  31.488 0 31.512 0.084 ;
    END
  END fdm[350]
  PIN fdm[351]
    DIRECTION OUTPUT ;
    USE SIGNAL ;
    PORT
      LAYER M5 ;
        RECT  31.296 0 31.32 0.084 ;
    END
  END fdm[351]
  PIN fdm[352]
    DIRECTION OUTPUT ;
    USE SIGNAL ;
    PORT
      LAYER M5 ;
        RECT  31.104 0 31.128 0.084 ;
    END
  END fdm[352]
  PIN fdm[353]
    DIRECTION OUTPUT ;
    USE SIGNAL ;
    PORT
      LAYER M5 ;
        RECT  30.912 0 30.936 0.084 ;
    END
  END fdm[353]
  PIN fdm[354]
    DIRECTION OUTPUT ;
    USE SIGNAL ;
    PORT
      LAYER M5 ;
        RECT  30.768 0 30.792 0.084 ;
    END
  END fdm[354]
  PIN fdm[355]
    DIRECTION OUTPUT ;
    USE SIGNAL ;
    PORT
      LAYER M5 ;
        RECT  30.576 0 30.6 0.084 ;
    END
  END fdm[355]
  PIN fdm[356]
    DIRECTION OUTPUT ;
    USE SIGNAL ;
    PORT
      LAYER M5 ;
        RECT  30.384 0 30.408 0.084 ;
    END
  END fdm[356]
  PIN fdm[357]
    DIRECTION OUTPUT ;
    USE SIGNAL ;
    PORT
      LAYER M5 ;
        RECT  30.24 0 30.264 0.084 ;
    END
  END fdm[357]
  PIN fdm[358]
    DIRECTION OUTPUT ;
    USE SIGNAL ;
    PORT
      LAYER M5 ;
        RECT  30.048 0 30.072 0.084 ;
    END
  END fdm[358]
  PIN fdm[359]
    DIRECTION OUTPUT ;
    USE SIGNAL ;
    PORT
      LAYER M5 ;
        RECT  29.856 0 29.88 0.084 ;
    END
  END fdm[359]
  PIN fdm[35]
    DIRECTION OUTPUT ;
    USE SIGNAL ;
    PORT
      LAYER M5 ;
        RECT  138 0 138.024 0.084 ;
    END
  END fdm[35]
  PIN fdm[360]
    DIRECTION OUTPUT ;
    USE SIGNAL ;
    PORT
      LAYER M5 ;
        RECT  29.664 0 29.688 0.084 ;
    END
  END fdm[360]
  PIN fdm[361]
    DIRECTION OUTPUT ;
    USE SIGNAL ;
    PORT
      LAYER M5 ;
        RECT  29.52 0 29.544 0.084 ;
    END
  END fdm[361]
  PIN fdm[362]
    DIRECTION OUTPUT ;
    USE SIGNAL ;
    PORT
      LAYER M5 ;
        RECT  29.328 0 29.352 0.084 ;
    END
  END fdm[362]
  PIN fdm[363]
    DIRECTION OUTPUT ;
    USE SIGNAL ;
    PORT
      LAYER M5 ;
        RECT  29.136 0 29.16 0.084 ;
    END
  END fdm[363]
  PIN fdm[364]
    DIRECTION OUTPUT ;
    USE SIGNAL ;
    PORT
      LAYER M5 ;
        RECT  28.944 0 28.968 0.084 ;
    END
  END fdm[364]
  PIN fdm[365]
    DIRECTION OUTPUT ;
    USE SIGNAL ;
    PORT
      LAYER M5 ;
        RECT  28.8 0 28.824 0.084 ;
    END
  END fdm[365]
  PIN fdm[366]
    DIRECTION OUTPUT ;
    USE SIGNAL ;
    PORT
      LAYER M5 ;
        RECT  28.608 0 28.632 0.084 ;
    END
  END fdm[366]
  PIN fdm[367]
    DIRECTION OUTPUT ;
    USE SIGNAL ;
    PORT
      LAYER M5 ;
        RECT  28.416 0 28.44 0.084 ;
    END
  END fdm[367]
  PIN fdm[368]
    DIRECTION OUTPUT ;
    USE SIGNAL ;
    PORT
      LAYER M5 ;
        RECT  28.224 0 28.248 0.084 ;
    END
  END fdm[368]
  PIN fdm[369]
    DIRECTION OUTPUT ;
    USE SIGNAL ;
    PORT
      LAYER M5 ;
        RECT  28.08 0 28.104 0.084 ;
    END
  END fdm[369]
  PIN fdm[36]
    DIRECTION OUTPUT ;
    USE SIGNAL ;
    PORT
      LAYER M5 ;
        RECT  137.808 0 137.832 0.084 ;
    END
  END fdm[36]
  PIN fdm[370]
    DIRECTION OUTPUT ;
    USE SIGNAL ;
    PORT
      LAYER M5 ;
        RECT  27.888 0 27.912 0.084 ;
    END
  END fdm[370]
  PIN fdm[371]
    DIRECTION OUTPUT ;
    USE SIGNAL ;
    PORT
      LAYER M5 ;
        RECT  27.696 0 27.72 0.084 ;
    END
  END fdm[371]
  PIN fdm[372]
    DIRECTION OUTPUT ;
    USE SIGNAL ;
    PORT
      LAYER M5 ;
        RECT  27.504 0 27.528 0.084 ;
    END
  END fdm[372]
  PIN fdm[373]
    DIRECTION OUTPUT ;
    USE SIGNAL ;
    PORT
      LAYER M5 ;
        RECT  27.36 0 27.384 0.084 ;
    END
  END fdm[373]
  PIN fdm[374]
    DIRECTION OUTPUT ;
    USE SIGNAL ;
    PORT
      LAYER M5 ;
        RECT  27.168 0 27.192 0.084 ;
    END
  END fdm[374]
  PIN fdm[375]
    DIRECTION OUTPUT ;
    USE SIGNAL ;
    PORT
      LAYER M5 ;
        RECT  26.976 0 27 0.084 ;
    END
  END fdm[375]
  PIN fdm[376]
    DIRECTION OUTPUT ;
    USE SIGNAL ;
    PORT
      LAYER M5 ;
        RECT  26.832 0 26.856 0.084 ;
    END
  END fdm[376]
  PIN fdm[377]
    DIRECTION OUTPUT ;
    USE SIGNAL ;
    PORT
      LAYER M5 ;
        RECT  26.64 0 26.664 0.084 ;
    END
  END fdm[377]
  PIN fdm[378]
    DIRECTION OUTPUT ;
    USE SIGNAL ;
    PORT
      LAYER M5 ;
        RECT  26.448 0 26.472 0.084 ;
    END
  END fdm[378]
  PIN fdm[379]
    DIRECTION OUTPUT ;
    USE SIGNAL ;
    PORT
      LAYER M5 ;
        RECT  26.256 0 26.28 0.084 ;
    END
  END fdm[379]
  PIN fdm[37]
    DIRECTION OUTPUT ;
    USE SIGNAL ;
    PORT
      LAYER M5 ;
        RECT  137.616 0 137.64 0.084 ;
    END
  END fdm[37]
  PIN fdm[380]
    DIRECTION OUTPUT ;
    USE SIGNAL ;
    PORT
      LAYER M5 ;
        RECT  26.112 0 26.136 0.084 ;
    END
  END fdm[380]
  PIN fdm[381]
    DIRECTION OUTPUT ;
    USE SIGNAL ;
    PORT
      LAYER M5 ;
        RECT  25.92 0 25.944 0.084 ;
    END
  END fdm[381]
  PIN fdm[382]
    DIRECTION OUTPUT ;
    USE SIGNAL ;
    PORT
      LAYER M5 ;
        RECT  25.728 0 25.752 0.084 ;
    END
  END fdm[382]
  PIN fdm[383]
    DIRECTION OUTPUT ;
    USE SIGNAL ;
    PORT
      LAYER M5 ;
        RECT  25.536 0 25.56 0.084 ;
    END
  END fdm[383]
  PIN fdm[384]
    DIRECTION OUTPUT ;
    USE SIGNAL ;
    PORT
      LAYER M5 ;
        RECT  25.392 0 25.416 0.084 ;
    END
  END fdm[384]
  PIN fdm[385]
    DIRECTION OUTPUT ;
    USE SIGNAL ;
    PORT
      LAYER M5 ;
        RECT  25.2 0 25.224 0.084 ;
    END
  END fdm[385]
  PIN fdm[386]
    DIRECTION OUTPUT ;
    USE SIGNAL ;
    PORT
      LAYER M5 ;
        RECT  25.008 0 25.032 0.084 ;
    END
  END fdm[386]
  PIN fdm[387]
    DIRECTION OUTPUT ;
    USE SIGNAL ;
    PORT
      LAYER M5 ;
        RECT  24.816 0 24.84 0.084 ;
    END
  END fdm[387]
  PIN fdm[388]
    DIRECTION OUTPUT ;
    USE SIGNAL ;
    PORT
      LAYER M5 ;
        RECT  24.672 0 24.696 0.084 ;
    END
  END fdm[388]
  PIN fdm[389]
    DIRECTION OUTPUT ;
    USE SIGNAL ;
    PORT
      LAYER M5 ;
        RECT  24.48 0 24.504 0.084 ;
    END
  END fdm[389]
  PIN fdm[38]
    DIRECTION OUTPUT ;
    USE SIGNAL ;
    PORT
      LAYER M5 ;
        RECT  137.424 0 137.448 0.084 ;
    END
  END fdm[38]
  PIN fdm[390]
    DIRECTION OUTPUT ;
    USE SIGNAL ;
    PORT
      LAYER M5 ;
        RECT  24.288 0 24.312 0.084 ;
    END
  END fdm[390]
  PIN fdm[391]
    DIRECTION OUTPUT ;
    USE SIGNAL ;
    PORT
      LAYER M5 ;
        RECT  24.096 0 24.12 0.084 ;
    END
  END fdm[391]
  PIN fdm[392]
    DIRECTION OUTPUT ;
    USE SIGNAL ;
    PORT
      LAYER M5 ;
        RECT  23.952 0 23.976 0.084 ;
    END
  END fdm[392]
  PIN fdm[393]
    DIRECTION OUTPUT ;
    USE SIGNAL ;
    PORT
      LAYER M5 ;
        RECT  23.76 0 23.784 0.084 ;
    END
  END fdm[393]
  PIN fdm[394]
    DIRECTION OUTPUT ;
    USE SIGNAL ;
    PORT
      LAYER M5 ;
        RECT  23.568 0 23.592 0.084 ;
    END
  END fdm[394]
  PIN fdm[395]
    DIRECTION OUTPUT ;
    USE SIGNAL ;
    PORT
      LAYER M5 ;
        RECT  23.424 0 23.448 0.084 ;
    END
  END fdm[395]
  PIN fdm[396]
    DIRECTION OUTPUT ;
    USE SIGNAL ;
    PORT
      LAYER M5 ;
        RECT  23.232 0 23.256 0.084 ;
    END
  END fdm[396]
  PIN fdm[397]
    DIRECTION OUTPUT ;
    USE SIGNAL ;
    PORT
      LAYER M5 ;
        RECT  23.04 0 23.064 0.084 ;
    END
  END fdm[397]
  PIN fdm[398]
    DIRECTION OUTPUT ;
    USE SIGNAL ;
    PORT
      LAYER M5 ;
        RECT  22.848 0 22.872 0.084 ;
    END
  END fdm[398]
  PIN fdm[399]
    DIRECTION OUTPUT ;
    USE SIGNAL ;
    PORT
      LAYER M5 ;
        RECT  22.704 0 22.728 0.084 ;
    END
  END fdm[399]
  PIN fdm[39]
    DIRECTION OUTPUT ;
    USE SIGNAL ;
    PORT
      LAYER M5 ;
        RECT  137.28 0 137.304 0.084 ;
    END
  END fdm[39]
  PIN fdm[3]
    DIRECTION OUTPUT ;
    USE SIGNAL ;
    PORT
      LAYER M5 ;
        RECT  143.712 0 143.736 0.084 ;
    END
  END fdm[3]
  PIN fdm[400]
    DIRECTION OUTPUT ;
    USE SIGNAL ;
    PORT
      LAYER M5 ;
        RECT  22.512 0 22.536 0.084 ;
    END
  END fdm[400]
  PIN fdm[401]
    DIRECTION OUTPUT ;
    USE SIGNAL ;
    PORT
      LAYER M5 ;
        RECT  22.32 0 22.344 0.084 ;
    END
  END fdm[401]
  PIN fdm[402]
    DIRECTION OUTPUT ;
    USE SIGNAL ;
    PORT
      LAYER M5 ;
        RECT  22.128 0 22.152 0.084 ;
    END
  END fdm[402]
  PIN fdm[403]
    DIRECTION OUTPUT ;
    USE SIGNAL ;
    PORT
      LAYER M5 ;
        RECT  21.984 0 22.008 0.084 ;
    END
  END fdm[403]
  PIN fdm[404]
    DIRECTION OUTPUT ;
    USE SIGNAL ;
    PORT
      LAYER M5 ;
        RECT  21.792 0 21.816 0.084 ;
    END
  END fdm[404]
  PIN fdm[405]
    DIRECTION OUTPUT ;
    USE SIGNAL ;
    PORT
      LAYER M5 ;
        RECT  21.6 0 21.624 0.084 ;
    END
  END fdm[405]
  PIN fdm[406]
    DIRECTION OUTPUT ;
    USE SIGNAL ;
    PORT
      LAYER M5 ;
        RECT  21.408 0 21.432 0.084 ;
    END
  END fdm[406]
  PIN fdm[407]
    DIRECTION OUTPUT ;
    USE SIGNAL ;
    PORT
      LAYER M5 ;
        RECT  21.264 0 21.288 0.084 ;
    END
  END fdm[407]
  PIN fdm[408]
    DIRECTION OUTPUT ;
    USE SIGNAL ;
    PORT
      LAYER M5 ;
        RECT  21.072 0 21.096 0.084 ;
    END
  END fdm[408]
  PIN fdm[409]
    DIRECTION OUTPUT ;
    USE SIGNAL ;
    PORT
      LAYER M5 ;
        RECT  20.88 0 20.904 0.084 ;
    END
  END fdm[409]
  PIN fdm[40]
    DIRECTION OUTPUT ;
    USE SIGNAL ;
    PORT
      LAYER M5 ;
        RECT  137.088 0 137.112 0.084 ;
    END
  END fdm[40]
  PIN fdm[410]
    DIRECTION OUTPUT ;
    USE SIGNAL ;
    PORT
      LAYER M5 ;
        RECT  20.688 0 20.712 0.084 ;
    END
  END fdm[410]
  PIN fdm[411]
    DIRECTION OUTPUT ;
    USE SIGNAL ;
    PORT
      LAYER M5 ;
        RECT  20.544 0 20.568 0.084 ;
    END
  END fdm[411]
  PIN fdm[412]
    DIRECTION OUTPUT ;
    USE SIGNAL ;
    PORT
      LAYER M5 ;
        RECT  20.352 0 20.376 0.084 ;
    END
  END fdm[412]
  PIN fdm[413]
    DIRECTION OUTPUT ;
    USE SIGNAL ;
    PORT
      LAYER M5 ;
        RECT  20.16 0 20.184 0.084 ;
    END
  END fdm[413]
  PIN fdm[414]
    DIRECTION OUTPUT ;
    USE SIGNAL ;
    PORT
      LAYER M5 ;
        RECT  20.016 0 20.04 0.084 ;
    END
  END fdm[414]
  PIN fdm[415]
    DIRECTION OUTPUT ;
    USE SIGNAL ;
    PORT
      LAYER M5 ;
        RECT  19.824 0 19.848 0.084 ;
    END
  END fdm[415]
  PIN fdm[416]
    DIRECTION OUTPUT ;
    USE SIGNAL ;
    PORT
      LAYER M5 ;
        RECT  19.632 0 19.656 0.084 ;
    END
  END fdm[416]
  PIN fdm[417]
    DIRECTION OUTPUT ;
    USE SIGNAL ;
    PORT
      LAYER M5 ;
        RECT  19.44 0 19.464 0.084 ;
    END
  END fdm[417]
  PIN fdm[418]
    DIRECTION OUTPUT ;
    USE SIGNAL ;
    PORT
      LAYER M5 ;
        RECT  19.296 0 19.32 0.084 ;
    END
  END fdm[418]
  PIN fdm[419]
    DIRECTION OUTPUT ;
    USE SIGNAL ;
    PORT
      LAYER M5 ;
        RECT  19.104 0 19.128 0.084 ;
    END
  END fdm[419]
  PIN fdm[41]
    DIRECTION OUTPUT ;
    USE SIGNAL ;
    PORT
      LAYER M5 ;
        RECT  136.896 0 136.92 0.084 ;
    END
  END fdm[41]
  PIN fdm[420]
    DIRECTION OUTPUT ;
    USE SIGNAL ;
    PORT
      LAYER M5 ;
        RECT  18.912 0 18.936 0.084 ;
    END
  END fdm[420]
  PIN fdm[421]
    DIRECTION OUTPUT ;
    USE SIGNAL ;
    PORT
      LAYER M5 ;
        RECT  18.72 0 18.744 0.084 ;
    END
  END fdm[421]
  PIN fdm[422]
    DIRECTION OUTPUT ;
    USE SIGNAL ;
    PORT
      LAYER M5 ;
        RECT  18.576 0 18.6 0.084 ;
    END
  END fdm[422]
  PIN fdm[423]
    DIRECTION OUTPUT ;
    USE SIGNAL ;
    PORT
      LAYER M5 ;
        RECT  18.384 0 18.408 0.084 ;
    END
  END fdm[423]
  PIN fdm[424]
    DIRECTION OUTPUT ;
    USE SIGNAL ;
    PORT
      LAYER M5 ;
        RECT  18.192 0 18.216 0.084 ;
    END
  END fdm[424]
  PIN fdm[425]
    DIRECTION OUTPUT ;
    USE SIGNAL ;
    PORT
      LAYER M5 ;
        RECT  18 0 18.024 0.084 ;
    END
  END fdm[425]
  PIN fdm[426]
    DIRECTION OUTPUT ;
    USE SIGNAL ;
    PORT
      LAYER M5 ;
        RECT  17.856 0 17.88 0.084 ;
    END
  END fdm[426]
  PIN fdm[427]
    DIRECTION OUTPUT ;
    USE SIGNAL ;
    PORT
      LAYER M5 ;
        RECT  17.664 0 17.688 0.084 ;
    END
  END fdm[427]
  PIN fdm[428]
    DIRECTION OUTPUT ;
    USE SIGNAL ;
    PORT
      LAYER M5 ;
        RECT  17.472 0 17.496 0.084 ;
    END
  END fdm[428]
  PIN fdm[429]
    DIRECTION OUTPUT ;
    USE SIGNAL ;
    PORT
      LAYER M5 ;
        RECT  17.328 0 17.352 0.084 ;
    END
  END fdm[429]
  PIN fdm[42]
    DIRECTION OUTPUT ;
    USE SIGNAL ;
    PORT
      LAYER M5 ;
        RECT  136.704 0 136.728 0.084 ;
    END
  END fdm[42]
  PIN fdm[430]
    DIRECTION OUTPUT ;
    USE SIGNAL ;
    PORT
      LAYER M5 ;
        RECT  17.136 0 17.16 0.084 ;
    END
  END fdm[430]
  PIN fdm[431]
    DIRECTION OUTPUT ;
    USE SIGNAL ;
    PORT
      LAYER M5 ;
        RECT  16.944 0 16.968 0.084 ;
    END
  END fdm[431]
  PIN fdm[432]
    DIRECTION OUTPUT ;
    USE SIGNAL ;
    PORT
      LAYER M5 ;
        RECT  16.752 0 16.776 0.084 ;
    END
  END fdm[432]
  PIN fdm[433]
    DIRECTION OUTPUT ;
    USE SIGNAL ;
    PORT
      LAYER M5 ;
        RECT  16.608 0 16.632 0.084 ;
    END
  END fdm[433]
  PIN fdm[434]
    DIRECTION OUTPUT ;
    USE SIGNAL ;
    PORT
      LAYER M5 ;
        RECT  16.416 0 16.44 0.084 ;
    END
  END fdm[434]
  PIN fdm[435]
    DIRECTION OUTPUT ;
    USE SIGNAL ;
    PORT
      LAYER M5 ;
        RECT  16.224 0 16.248 0.084 ;
    END
  END fdm[435]
  PIN fdm[436]
    DIRECTION OUTPUT ;
    USE SIGNAL ;
    PORT
      LAYER M5 ;
        RECT  16.032 0 16.056 0.084 ;
    END
  END fdm[436]
  PIN fdm[437]
    DIRECTION OUTPUT ;
    USE SIGNAL ;
    PORT
      LAYER M5 ;
        RECT  15.888 0 15.912 0.084 ;
    END
  END fdm[437]
  PIN fdm[438]
    DIRECTION OUTPUT ;
    USE SIGNAL ;
    PORT
      LAYER M5 ;
        RECT  15.696 0 15.72 0.084 ;
    END
  END fdm[438]
  PIN fdm[439]
    DIRECTION OUTPUT ;
    USE SIGNAL ;
    PORT
      LAYER M5 ;
        RECT  15.504 0 15.528 0.084 ;
    END
  END fdm[439]
  PIN fdm[43]
    DIRECTION OUTPUT ;
    USE SIGNAL ;
    PORT
      LAYER M5 ;
        RECT  136.56 0 136.584 0.084 ;
    END
  END fdm[43]
  PIN fdm[440]
    DIRECTION OUTPUT ;
    USE SIGNAL ;
    PORT
      LAYER M5 ;
        RECT  15.312 0 15.336 0.084 ;
    END
  END fdm[440]
  PIN fdm[441]
    DIRECTION OUTPUT ;
    USE SIGNAL ;
    PORT
      LAYER M5 ;
        RECT  15.168 0 15.192 0.084 ;
    END
  END fdm[441]
  PIN fdm[442]
    DIRECTION OUTPUT ;
    USE SIGNAL ;
    PORT
      LAYER M5 ;
        RECT  14.976 0 15 0.084 ;
    END
  END fdm[442]
  PIN fdm[443]
    DIRECTION OUTPUT ;
    USE SIGNAL ;
    PORT
      LAYER M5 ;
        RECT  14.784 0 14.808 0.084 ;
    END
  END fdm[443]
  PIN fdm[444]
    DIRECTION OUTPUT ;
    USE SIGNAL ;
    PORT
      LAYER M5 ;
        RECT  14.592 0 14.616 0.084 ;
    END
  END fdm[444]
  PIN fdm[445]
    DIRECTION OUTPUT ;
    USE SIGNAL ;
    PORT
      LAYER M5 ;
        RECT  14.448 0 14.472 0.084 ;
    END
  END fdm[445]
  PIN fdm[446]
    DIRECTION OUTPUT ;
    USE SIGNAL ;
    PORT
      LAYER M5 ;
        RECT  14.256 0 14.28 0.084 ;
    END
  END fdm[446]
  PIN fdm[447]
    DIRECTION OUTPUT ;
    USE SIGNAL ;
    PORT
      LAYER M5 ;
        RECT  14.064 0 14.088 0.084 ;
    END
  END fdm[447]
  PIN fdm[448]
    DIRECTION OUTPUT ;
    USE SIGNAL ;
    PORT
      LAYER M5 ;
        RECT  13.92 0 13.944 0.084 ;
    END
  END fdm[448]
  PIN fdm[449]
    DIRECTION OUTPUT ;
    USE SIGNAL ;
    PORT
      LAYER M5 ;
        RECT  13.728 0 13.752 0.084 ;
    END
  END fdm[449]
  PIN fdm[44]
    DIRECTION OUTPUT ;
    USE SIGNAL ;
    PORT
      LAYER M5 ;
        RECT  136.368 0 136.392 0.084 ;
    END
  END fdm[44]
  PIN fdm[450]
    DIRECTION OUTPUT ;
    USE SIGNAL ;
    PORT
      LAYER M5 ;
        RECT  13.536 0 13.56 0.084 ;
    END
  END fdm[450]
  PIN fdm[451]
    DIRECTION OUTPUT ;
    USE SIGNAL ;
    PORT
      LAYER M5 ;
        RECT  13.344 0 13.368 0.084 ;
    END
  END fdm[451]
  PIN fdm[452]
    DIRECTION OUTPUT ;
    USE SIGNAL ;
    PORT
      LAYER M5 ;
        RECT  13.2 0 13.224 0.084 ;
    END
  END fdm[452]
  PIN fdm[453]
    DIRECTION OUTPUT ;
    USE SIGNAL ;
    PORT
      LAYER M5 ;
        RECT  13.008 0 13.032 0.084 ;
    END
  END fdm[453]
  PIN fdm[454]
    DIRECTION OUTPUT ;
    USE SIGNAL ;
    PORT
      LAYER M5 ;
        RECT  12.816 0 12.84 0.084 ;
    END
  END fdm[454]
  PIN fdm[455]
    DIRECTION OUTPUT ;
    USE SIGNAL ;
    PORT
      LAYER M5 ;
        RECT  12.624 0 12.648 0.084 ;
    END
  END fdm[455]
  PIN fdm[456]
    DIRECTION OUTPUT ;
    USE SIGNAL ;
    PORT
      LAYER M5 ;
        RECT  12.48 0 12.504 0.084 ;
    END
  END fdm[456]
  PIN fdm[457]
    DIRECTION OUTPUT ;
    USE SIGNAL ;
    PORT
      LAYER M5 ;
        RECT  12.288 0 12.312 0.084 ;
    END
  END fdm[457]
  PIN fdm[458]
    DIRECTION OUTPUT ;
    USE SIGNAL ;
    PORT
      LAYER M5 ;
        RECT  12.096 0 12.12 0.084 ;
    END
  END fdm[458]
  PIN fdm[459]
    DIRECTION OUTPUT ;
    USE SIGNAL ;
    PORT
      LAYER M5 ;
        RECT  11.904 0 11.928 0.084 ;
    END
  END fdm[459]
  PIN fdm[45]
    DIRECTION OUTPUT ;
    USE SIGNAL ;
    PORT
      LAYER M5 ;
        RECT  136.176 0 136.2 0.084 ;
    END
  END fdm[45]
  PIN fdm[460]
    DIRECTION OUTPUT ;
    USE SIGNAL ;
    PORT
      LAYER M5 ;
        RECT  11.76 0 11.784 0.084 ;
    END
  END fdm[460]
  PIN fdm[461]
    DIRECTION OUTPUT ;
    USE SIGNAL ;
    PORT
      LAYER M5 ;
        RECT  11.568 0 11.592 0.084 ;
    END
  END fdm[461]
  PIN fdm[462]
    DIRECTION OUTPUT ;
    USE SIGNAL ;
    PORT
      LAYER M5 ;
        RECT  11.376 0 11.4 0.084 ;
    END
  END fdm[462]
  PIN fdm[463]
    DIRECTION OUTPUT ;
    USE SIGNAL ;
    PORT
      LAYER M5 ;
        RECT  11.184 0 11.208 0.084 ;
    END
  END fdm[463]
  PIN fdm[464]
    DIRECTION OUTPUT ;
    USE SIGNAL ;
    PORT
      LAYER M5 ;
        RECT  11.04 0 11.064 0.084 ;
    END
  END fdm[464]
  PIN fdm[465]
    DIRECTION OUTPUT ;
    USE SIGNAL ;
    PORT
      LAYER M5 ;
        RECT  10.848 0 10.872 0.084 ;
    END
  END fdm[465]
  PIN fdm[466]
    DIRECTION OUTPUT ;
    USE SIGNAL ;
    PORT
      LAYER M5 ;
        RECT  10.656 0 10.68 0.084 ;
    END
  END fdm[466]
  PIN fdm[467]
    DIRECTION OUTPUT ;
    USE SIGNAL ;
    PORT
      LAYER M5 ;
        RECT  10.512 0 10.536 0.084 ;
    END
  END fdm[467]
  PIN fdm[468]
    DIRECTION OUTPUT ;
    USE SIGNAL ;
    PORT
      LAYER M5 ;
        RECT  10.32 0 10.344 0.084 ;
    END
  END fdm[468]
  PIN fdm[469]
    DIRECTION OUTPUT ;
    USE SIGNAL ;
    PORT
      LAYER M5 ;
        RECT  10.128 0 10.152 0.084 ;
    END
  END fdm[469]
  PIN fdm[46]
    DIRECTION OUTPUT ;
    USE SIGNAL ;
    PORT
      LAYER M5 ;
        RECT  136.032 0 136.056 0.084 ;
    END
  END fdm[46]
  PIN fdm[470]
    DIRECTION OUTPUT ;
    USE SIGNAL ;
    PORT
      LAYER M5 ;
        RECT  9.936 0 9.96 0.084 ;
    END
  END fdm[470]
  PIN fdm[471]
    DIRECTION OUTPUT ;
    USE SIGNAL ;
    PORT
      LAYER M5 ;
        RECT  9.792 0 9.816 0.084 ;
    END
  END fdm[471]
  PIN fdm[472]
    DIRECTION OUTPUT ;
    USE SIGNAL ;
    PORT
      LAYER M5 ;
        RECT  9.6 0 9.624 0.084 ;
    END
  END fdm[472]
  PIN fdm[473]
    DIRECTION OUTPUT ;
    USE SIGNAL ;
    PORT
      LAYER M5 ;
        RECT  9.408 0 9.432 0.084 ;
    END
  END fdm[473]
  PIN fdm[474]
    DIRECTION OUTPUT ;
    USE SIGNAL ;
    PORT
      LAYER M5 ;
        RECT  9.216 0 9.24 0.084 ;
    END
  END fdm[474]
  PIN fdm[475]
    DIRECTION OUTPUT ;
    USE SIGNAL ;
    PORT
      LAYER M5 ;
        RECT  9.072 0 9.096 0.084 ;
    END
  END fdm[475]
  PIN fdm[476]
    DIRECTION OUTPUT ;
    USE SIGNAL ;
    PORT
      LAYER M5 ;
        RECT  8.88 0 8.904 0.084 ;
    END
  END fdm[476]
  PIN fdm[477]
    DIRECTION OUTPUT ;
    USE SIGNAL ;
    PORT
      LAYER M5 ;
        RECT  8.688 0 8.712 0.084 ;
    END
  END fdm[477]
  PIN fdm[478]
    DIRECTION OUTPUT ;
    USE SIGNAL ;
    PORT
      LAYER M5 ;
        RECT  8.496 0 8.52 0.084 ;
    END
  END fdm[478]
  PIN fdm[479]
    DIRECTION OUTPUT ;
    USE SIGNAL ;
    PORT
      LAYER M5 ;
        RECT  8.352 0 8.376 0.084 ;
    END
  END fdm[479]
  PIN fdm[47]
    DIRECTION OUTPUT ;
    USE SIGNAL ;
    PORT
      LAYER M5 ;
        RECT  135.84 0 135.864 0.084 ;
    END
  END fdm[47]
  PIN fdm[480]
    DIRECTION OUTPUT ;
    USE SIGNAL ;
    PORT
      LAYER M5 ;
        RECT  8.16 0 8.184 0.084 ;
    END
  END fdm[480]
  PIN fdm[481]
    DIRECTION OUTPUT ;
    USE SIGNAL ;
    PORT
      LAYER M5 ;
        RECT  7.968 0 7.992 0.084 ;
    END
  END fdm[481]
  PIN fdm[482]
    DIRECTION OUTPUT ;
    USE SIGNAL ;
    PORT
      LAYER M5 ;
        RECT  7.776 0 7.8 0.084 ;
    END
  END fdm[482]
  PIN fdm[483]
    DIRECTION OUTPUT ;
    USE SIGNAL ;
    PORT
      LAYER M5 ;
        RECT  7.632 0 7.656 0.084 ;
    END
  END fdm[483]
  PIN fdm[484]
    DIRECTION OUTPUT ;
    USE SIGNAL ;
    PORT
      LAYER M5 ;
        RECT  7.44 0 7.464 0.084 ;
    END
  END fdm[484]
  PIN fdm[485]
    DIRECTION OUTPUT ;
    USE SIGNAL ;
    PORT
      LAYER M5 ;
        RECT  7.248 0 7.272 0.084 ;
    END
  END fdm[485]
  PIN fdm[486]
    DIRECTION OUTPUT ;
    USE SIGNAL ;
    PORT
      LAYER M5 ;
        RECT  7.104 0 7.128 0.084 ;
    END
  END fdm[486]
  PIN fdm[487]
    DIRECTION OUTPUT ;
    USE SIGNAL ;
    PORT
      LAYER M5 ;
        RECT  6.912 0 6.936 0.084 ;
    END
  END fdm[487]
  PIN fdm[488]
    DIRECTION OUTPUT ;
    USE SIGNAL ;
    PORT
      LAYER M5 ;
        RECT  6.72 0 6.744 0.084 ;
    END
  END fdm[488]
  PIN fdm[489]
    DIRECTION OUTPUT ;
    USE SIGNAL ;
    PORT
      LAYER M5 ;
        RECT  6.528 0 6.552 0.084 ;
    END
  END fdm[489]
  PIN fdm[48]
    DIRECTION OUTPUT ;
    USE SIGNAL ;
    PORT
      LAYER M5 ;
        RECT  135.648 0 135.672 0.084 ;
    END
  END fdm[48]
  PIN fdm[490]
    DIRECTION OUTPUT ;
    USE SIGNAL ;
    PORT
      LAYER M5 ;
        RECT  6.384 0 6.408 0.084 ;
    END
  END fdm[490]
  PIN fdm[491]
    DIRECTION OUTPUT ;
    USE SIGNAL ;
    PORT
      LAYER M5 ;
        RECT  6.192 0 6.216 0.084 ;
    END
  END fdm[491]
  PIN fdm[492]
    DIRECTION OUTPUT ;
    USE SIGNAL ;
    PORT
      LAYER M5 ;
        RECT  6 0 6.024 0.084 ;
    END
  END fdm[492]
  PIN fdm[493]
    DIRECTION OUTPUT ;
    USE SIGNAL ;
    PORT
      LAYER M5 ;
        RECT  5.808 0 5.832 0.084 ;
    END
  END fdm[493]
  PIN fdm[494]
    DIRECTION OUTPUT ;
    USE SIGNAL ;
    PORT
      LAYER M5 ;
        RECT  5.664 0 5.688 0.084 ;
    END
  END fdm[494]
  PIN fdm[495]
    DIRECTION OUTPUT ;
    USE SIGNAL ;
    PORT
      LAYER M5 ;
        RECT  5.472 0 5.496 0.084 ;
    END
  END fdm[495]
  PIN fdm[496]
    DIRECTION OUTPUT ;
    USE SIGNAL ;
    PORT
      LAYER M5 ;
        RECT  5.28 0 5.304 0.084 ;
    END
  END fdm[496]
  PIN fdm[497]
    DIRECTION OUTPUT ;
    USE SIGNAL ;
    PORT
      LAYER M5 ;
        RECT  5.088 0 5.112 0.084 ;
    END
  END fdm[497]
  PIN fdm[498]
    DIRECTION OUTPUT ;
    USE SIGNAL ;
    PORT
      LAYER M5 ;
        RECT  4.944 0 4.968 0.084 ;
    END
  END fdm[498]
  PIN fdm[499]
    DIRECTION OUTPUT ;
    USE SIGNAL ;
    PORT
      LAYER M5 ;
        RECT  4.752 0 4.776 0.084 ;
    END
  END fdm[499]
  PIN fdm[49]
    DIRECTION OUTPUT ;
    USE SIGNAL ;
    PORT
      LAYER M5 ;
        RECT  135.456 0 135.48 0.084 ;
    END
  END fdm[49]
  PIN fdm[4]
    DIRECTION OUTPUT ;
    USE SIGNAL ;
    PORT
      LAYER M5 ;
        RECT  143.52 0 143.544 0.084 ;
    END
  END fdm[4]
  PIN fdm[500]
    DIRECTION OUTPUT ;
    USE SIGNAL ;
    PORT
      LAYER M5 ;
        RECT  4.56 0 4.584 0.084 ;
    END
  END fdm[500]
  PIN fdm[501]
    DIRECTION OUTPUT ;
    USE SIGNAL ;
    PORT
      LAYER M5 ;
        RECT  4.368 0 4.392 0.084 ;
    END
  END fdm[501]
  PIN fdm[502]
    DIRECTION OUTPUT ;
    USE SIGNAL ;
    PORT
      LAYER M5 ;
        RECT  4.224 0 4.248 0.084 ;
    END
  END fdm[502]
  PIN fdm[503]
    DIRECTION OUTPUT ;
    USE SIGNAL ;
    PORT
      LAYER M5 ;
        RECT  4.032 0 4.056 0.084 ;
    END
  END fdm[503]
  PIN fdm[504]
    DIRECTION OUTPUT ;
    USE SIGNAL ;
    PORT
      LAYER M5 ;
        RECT  3.84 0 3.864 0.084 ;
    END
  END fdm[504]
  PIN fdm[505]
    DIRECTION OUTPUT ;
    USE SIGNAL ;
    PORT
      LAYER M5 ;
        RECT  3.696 0 3.72 0.084 ;
    END
  END fdm[505]
  PIN fdm[506]
    DIRECTION OUTPUT ;
    USE SIGNAL ;
    PORT
      LAYER M5 ;
        RECT  3.504 0 3.528 0.084 ;
    END
  END fdm[506]
  PIN fdm[507]
    DIRECTION OUTPUT ;
    USE SIGNAL ;
    PORT
      LAYER M5 ;
        RECT  3.312 0 3.336 0.084 ;
    END
  END fdm[507]
  PIN fdm[508]
    DIRECTION OUTPUT ;
    USE SIGNAL ;
    PORT
      LAYER M5 ;
        RECT  3.12 0 3.144 0.084 ;
    END
  END fdm[508]
  PIN fdm[509]
    DIRECTION OUTPUT ;
    USE SIGNAL ;
    PORT
      LAYER M5 ;
        RECT  2.976 0 3 0.084 ;
    END
  END fdm[509]
  PIN fdm[50]
    DIRECTION OUTPUT ;
    USE SIGNAL ;
    PORT
      LAYER M5 ;
        RECT  135.312 0 135.336 0.084 ;
    END
  END fdm[50]
  PIN fdm[510]
    DIRECTION OUTPUT ;
    USE SIGNAL ;
    PORT
      LAYER M5 ;
        RECT  2.784 0 2.808 0.084 ;
    END
  END fdm[510]
  PIN fdm[511]
    DIRECTION OUTPUT ;
    USE SIGNAL ;
    PORT
      LAYER M5 ;
        RECT  2.592 0 2.616 0.084 ;
    END
  END fdm[511]
  PIN fdm[512]
    DIRECTION OUTPUT ;
    USE SIGNAL ;
    PORT
      LAYER M5 ;
        RECT  2.4 0 2.424 0.084 ;
    END
  END fdm[512]
  PIN fdm[513]
    DIRECTION OUTPUT ;
    USE SIGNAL ;
    PORT
      LAYER M5 ;
        RECT  2.256 0 2.28 0.084 ;
    END
  END fdm[513]
  PIN fdm[514]
    DIRECTION OUTPUT ;
    USE SIGNAL ;
    PORT
      LAYER M5 ;
        RECT  2.064 0 2.088 0.084 ;
    END
  END fdm[514]
  PIN fdm[515]
    DIRECTION OUTPUT ;
    USE SIGNAL ;
    PORT
      LAYER M5 ;
        RECT  1.872 0 1.896 0.084 ;
    END
  END fdm[515]
  PIN fdm[516]
    DIRECTION OUTPUT ;
    USE SIGNAL ;
    PORT
      LAYER M5 ;
        RECT  1.68 0 1.704 0.084 ;
    END
  END fdm[516]
  PIN fdm[517]
    DIRECTION OUTPUT ;
    USE SIGNAL ;
    PORT
      LAYER M5 ;
        RECT  1.536 0 1.56 0.084 ;
    END
  END fdm[517]
  PIN fdm[518]
    DIRECTION OUTPUT ;
    USE SIGNAL ;
    PORT
      LAYER M5 ;
        RECT  1.344 0 1.368 0.084 ;
    END
  END fdm[518]
  PIN fdm[519]
    DIRECTION OUTPUT ;
    USE SIGNAL ;
    PORT
      LAYER M5 ;
        RECT  1.152 0 1.176 0.084 ;
    END
  END fdm[519]
  PIN fdm[51]
    DIRECTION OUTPUT ;
    USE SIGNAL ;
    PORT
      LAYER M5 ;
        RECT  135.12 0 135.144 0.084 ;
    END
  END fdm[51]
  PIN fdm[520]
    DIRECTION OUTPUT ;
    USE SIGNAL ;
    PORT
      LAYER M5 ;
        RECT  1.008 0 1.032 0.084 ;
    END
  END fdm[520]
  PIN fdm[52]
    DIRECTION OUTPUT ;
    USE SIGNAL ;
    PORT
      LAYER M5 ;
        RECT  134.928 0 134.952 0.084 ;
    END
  END fdm[52]
  PIN fdm[53]
    DIRECTION OUTPUT ;
    USE SIGNAL ;
    PORT
      LAYER M5 ;
        RECT  134.736 0 134.76 0.084 ;
    END
  END fdm[53]
  PIN fdm[54]
    DIRECTION OUTPUT ;
    USE SIGNAL ;
    PORT
      LAYER M5 ;
        RECT  134.592 0 134.616 0.084 ;
    END
  END fdm[54]
  PIN fdm[55]
    DIRECTION OUTPUT ;
    USE SIGNAL ;
    PORT
      LAYER M5 ;
        RECT  134.4 0 134.424 0.084 ;
    END
  END fdm[55]
  PIN fdm[56]
    DIRECTION OUTPUT ;
    USE SIGNAL ;
    PORT
      LAYER M5 ;
        RECT  134.208 0 134.232 0.084 ;
    END
  END fdm[56]
  PIN fdm[57]
    DIRECTION OUTPUT ;
    USE SIGNAL ;
    PORT
      LAYER M5 ;
        RECT  134.016 0 134.04 0.084 ;
    END
  END fdm[57]
  PIN fdm[58]
    DIRECTION OUTPUT ;
    USE SIGNAL ;
    PORT
      LAYER M5 ;
        RECT  133.872 0 133.896 0.084 ;
    END
  END fdm[58]
  PIN fdm[59]
    DIRECTION OUTPUT ;
    USE SIGNAL ;
    PORT
      LAYER M5 ;
        RECT  133.68 0 133.704 0.084 ;
    END
  END fdm[59]
  PIN fdm[5]
    DIRECTION OUTPUT ;
    USE SIGNAL ;
    PORT
      LAYER M5 ;
        RECT  143.376 0 143.4 0.084 ;
    END
  END fdm[5]
  PIN fdm[60]
    DIRECTION OUTPUT ;
    USE SIGNAL ;
    PORT
      LAYER M5 ;
        RECT  133.488 0 133.512 0.084 ;
    END
  END fdm[60]
  PIN fdm[61]
    DIRECTION OUTPUT ;
    USE SIGNAL ;
    PORT
      LAYER M5 ;
        RECT  133.296 0 133.32 0.084 ;
    END
  END fdm[61]
  PIN fdm[62]
    DIRECTION OUTPUT ;
    USE SIGNAL ;
    PORT
      LAYER M5 ;
        RECT  133.152 0 133.176 0.084 ;
    END
  END fdm[62]
  PIN fdm[63]
    DIRECTION OUTPUT ;
    USE SIGNAL ;
    PORT
      LAYER M5 ;
        RECT  132.96 0 132.984 0.084 ;
    END
  END fdm[63]
  PIN fdm[64]
    DIRECTION OUTPUT ;
    USE SIGNAL ;
    PORT
      LAYER M5 ;
        RECT  132.768 0 132.792 0.084 ;
    END
  END fdm[64]
  PIN fdm[65]
    DIRECTION OUTPUT ;
    USE SIGNAL ;
    PORT
      LAYER M5 ;
        RECT  132.624 0 132.648 0.084 ;
    END
  END fdm[65]
  PIN fdm[66]
    DIRECTION OUTPUT ;
    USE SIGNAL ;
    PORT
      LAYER M5 ;
        RECT  132.432 0 132.456 0.084 ;
    END
  END fdm[66]
  PIN fdm[67]
    DIRECTION OUTPUT ;
    USE SIGNAL ;
    PORT
      LAYER M5 ;
        RECT  132.24 0 132.264 0.084 ;
    END
  END fdm[67]
  PIN fdm[68]
    DIRECTION OUTPUT ;
    USE SIGNAL ;
    PORT
      LAYER M5 ;
        RECT  132.048 0 132.072 0.084 ;
    END
  END fdm[68]
  PIN fdm[69]
    DIRECTION OUTPUT ;
    USE SIGNAL ;
    PORT
      LAYER M5 ;
        RECT  131.904 0 131.928 0.084 ;
    END
  END fdm[69]
  PIN fdm[6]
    DIRECTION OUTPUT ;
    USE SIGNAL ;
    PORT
      LAYER M5 ;
        RECT  143.184 0 143.208 0.084 ;
    END
  END fdm[6]
  PIN fdm[70]
    DIRECTION OUTPUT ;
    USE SIGNAL ;
    PORT
      LAYER M5 ;
        RECT  131.712 0 131.736 0.084 ;
    END
  END fdm[70]
  PIN fdm[71]
    DIRECTION OUTPUT ;
    USE SIGNAL ;
    PORT
      LAYER M5 ;
        RECT  131.52 0 131.544 0.084 ;
    END
  END fdm[71]
  PIN fdm[72]
    DIRECTION OUTPUT ;
    USE SIGNAL ;
    PORT
      LAYER M5 ;
        RECT  131.328 0 131.352 0.084 ;
    END
  END fdm[72]
  PIN fdm[73]
    DIRECTION OUTPUT ;
    USE SIGNAL ;
    PORT
      LAYER M5 ;
        RECT  131.184 0 131.208 0.084 ;
    END
  END fdm[73]
  PIN fdm[74]
    DIRECTION OUTPUT ;
    USE SIGNAL ;
    PORT
      LAYER M5 ;
        RECT  130.992 0 131.016 0.084 ;
    END
  END fdm[74]
  PIN fdm[75]
    DIRECTION OUTPUT ;
    USE SIGNAL ;
    PORT
      LAYER M5 ;
        RECT  130.8 0 130.824 0.084 ;
    END
  END fdm[75]
  PIN fdm[76]
    DIRECTION OUTPUT ;
    USE SIGNAL ;
    PORT
      LAYER M5 ;
        RECT  130.608 0 130.632 0.084 ;
    END
  END fdm[76]
  PIN fdm[77]
    DIRECTION OUTPUT ;
    USE SIGNAL ;
    PORT
      LAYER M5 ;
        RECT  130.464 0 130.488 0.084 ;
    END
  END fdm[77]
  PIN fdm[78]
    DIRECTION OUTPUT ;
    USE SIGNAL ;
    PORT
      LAYER M5 ;
        RECT  130.272 0 130.296 0.084 ;
    END
  END fdm[78]
  PIN fdm[79]
    DIRECTION OUTPUT ;
    USE SIGNAL ;
    PORT
      LAYER M5 ;
        RECT  130.08 0 130.104 0.084 ;
    END
  END fdm[79]
  PIN fdm[7]
    DIRECTION OUTPUT ;
    USE SIGNAL ;
    PORT
      LAYER M5 ;
        RECT  142.992 0 143.016 0.084 ;
    END
  END fdm[7]
  PIN fdm[80]
    DIRECTION OUTPUT ;
    USE SIGNAL ;
    PORT
      LAYER M5 ;
        RECT  129.888 0 129.912 0.084 ;
    END
  END fdm[80]
  PIN fdm[81]
    DIRECTION OUTPUT ;
    USE SIGNAL ;
    PORT
      LAYER M5 ;
        RECT  129.744 0 129.768 0.084 ;
    END
  END fdm[81]
  PIN fdm[82]
    DIRECTION OUTPUT ;
    USE SIGNAL ;
    PORT
      LAYER M5 ;
        RECT  129.552 0 129.576 0.084 ;
    END
  END fdm[82]
  PIN fdm[83]
    DIRECTION OUTPUT ;
    USE SIGNAL ;
    PORT
      LAYER M5 ;
        RECT  129.36 0 129.384 0.084 ;
    END
  END fdm[83]
  PIN fdm[84]
    DIRECTION OUTPUT ;
    USE SIGNAL ;
    PORT
      LAYER M5 ;
        RECT  129.216 0 129.24 0.084 ;
    END
  END fdm[84]
  PIN fdm[85]
    DIRECTION OUTPUT ;
    USE SIGNAL ;
    PORT
      LAYER M5 ;
        RECT  129.024 0 129.048 0.084 ;
    END
  END fdm[85]
  PIN fdm[86]
    DIRECTION OUTPUT ;
    USE SIGNAL ;
    PORT
      LAYER M5 ;
        RECT  128.832 0 128.856 0.084 ;
    END
  END fdm[86]
  PIN fdm[87]
    DIRECTION OUTPUT ;
    USE SIGNAL ;
    PORT
      LAYER M5 ;
        RECT  128.64 0 128.664 0.084 ;
    END
  END fdm[87]
  PIN fdm[88]
    DIRECTION OUTPUT ;
    USE SIGNAL ;
    PORT
      LAYER M5 ;
        RECT  128.496 0 128.52 0.084 ;
    END
  END fdm[88]
  PIN fdm[89]
    DIRECTION OUTPUT ;
    USE SIGNAL ;
    PORT
      LAYER M5 ;
        RECT  128.304 0 128.328 0.084 ;
    END
  END fdm[89]
  PIN fdm[8]
    DIRECTION OUTPUT ;
    USE SIGNAL ;
    PORT
      LAYER M5 ;
        RECT  142.8 0 142.824 0.084 ;
    END
  END fdm[8]
  PIN fdm[90]
    DIRECTION OUTPUT ;
    USE SIGNAL ;
    PORT
      LAYER M5 ;
        RECT  128.112 0 128.136 0.084 ;
    END
  END fdm[90]
  PIN fdm[91]
    DIRECTION OUTPUT ;
    USE SIGNAL ;
    PORT
      LAYER M5 ;
        RECT  127.92 0 127.944 0.084 ;
    END
  END fdm[91]
  PIN fdm[92]
    DIRECTION OUTPUT ;
    USE SIGNAL ;
    PORT
      LAYER M5 ;
        RECT  127.776 0 127.8 0.084 ;
    END
  END fdm[92]
  PIN fdm[93]
    DIRECTION OUTPUT ;
    USE SIGNAL ;
    PORT
      LAYER M5 ;
        RECT  127.584 0 127.608 0.084 ;
    END
  END fdm[93]
  PIN fdm[94]
    DIRECTION OUTPUT ;
    USE SIGNAL ;
    PORT
      LAYER M5 ;
        RECT  127.392 0 127.416 0.084 ;
    END
  END fdm[94]
  PIN fdm[95]
    DIRECTION OUTPUT ;
    USE SIGNAL ;
    PORT
      LAYER M5 ;
        RECT  127.2 0 127.224 0.084 ;
    END
  END fdm[95]
  PIN fdm[96]
    DIRECTION OUTPUT ;
    USE SIGNAL ;
    PORT
      LAYER M5 ;
        RECT  127.056 0 127.08 0.084 ;
    END
  END fdm[96]
  PIN fdm[97]
    DIRECTION OUTPUT ;
    USE SIGNAL ;
    PORT
      LAYER M5 ;
        RECT  126.864 0 126.888 0.084 ;
    END
  END fdm[97]
  PIN fdm[98]
    DIRECTION OUTPUT ;
    USE SIGNAL ;
    PORT
      LAYER M5 ;
        RECT  126.672 0 126.696 0.084 ;
    END
  END fdm[98]
  PIN fdm[99]
    DIRECTION OUTPUT ;
    USE SIGNAL ;
    PORT
      LAYER M5 ;
        RECT  126.48 0 126.504 0.084 ;
    END
  END fdm[99]
  PIN fdm[9]
    DIRECTION OUTPUT ;
    USE SIGNAL ;
    PORT
      LAYER M5 ;
        RECT  142.656 0 142.68 0.084 ;
    END
  END fdm[9]
  PIN VDD
    DIRECTION INOUT ;
    USE POWER ;
    PORT
      LAYER M5 ;
        RECT  137.592 2.151 137.712 23.769 ;
        RECT  132.192 2.151 132.312 23.769 ;
        RECT  126.792 2.151 126.912 23.769 ;
        RECT  121.392 2.151 121.512 23.769 ;
        RECT  115.992 2.151 116.112 23.769 ;
        RECT  110.592 2.151 110.712 23.769 ;
        RECT  105.192 2.151 105.312 23.769 ;
        RECT  99.792 2.151 99.912 23.769 ;
        RECT  94.392 2.151 94.512 23.769 ;
        RECT  88.992 2.151 89.112 23.769 ;
        RECT  83.592 2.151 83.712 23.769 ;
        RECT  78.192 2.151 78.312 23.769 ;
        RECT  72.792 2.151 72.912 23.769 ;
        RECT  67.392 2.151 67.512 23.769 ;
        RECT  61.992 2.151 62.112 23.769 ;
        RECT  56.592 2.151 56.712 23.769 ;
        RECT  51.192 2.151 51.312 23.769 ;
        RECT  45.792 2.151 45.912 23.769 ;
        RECT  40.392 2.151 40.512 23.769 ;
        RECT  34.992 2.151 35.112 23.769 ;
        RECT  29.592 2.151 29.712 23.769 ;
        RECT  24.192 2.151 24.312 23.769 ;
        RECT  18.792 2.151 18.912 23.769 ;
        RECT  13.392 2.151 13.512 23.769 ;
        RECT  7.992 2.151 8.112 23.769 ;
        RECT  2.592 2.151 2.712 23.769 ;
    END
  END VDD
  PIN VSS
    DIRECTION INOUT ;
    USE GROUND ;
    PORT
      LAYER M5 ;
        RECT  137.4 2.137 137.52 23.783 ;
        RECT  132 2.137 132.12 23.783 ;
        RECT  126.6 2.137 126.72 23.783 ;
        RECT  121.2 2.137 121.32 23.783 ;
        RECT  115.8 2.137 115.92 23.783 ;
        RECT  110.4 2.137 110.52 23.783 ;
        RECT  105 2.137 105.12 23.783 ;
        RECT  99.6 2.137 99.72 23.783 ;
        RECT  94.2 2.137 94.32 23.783 ;
        RECT  88.8 2.137 88.92 23.783 ;
        RECT  83.4 2.137 83.52 23.783 ;
        RECT  78 2.137 78.12 23.783 ;
        RECT  72.6 2.137 72.72 23.783 ;
        RECT  67.2 2.137 67.32 23.783 ;
        RECT  61.8 2.137 61.92 23.783 ;
        RECT  56.4 2.137 56.52 23.783 ;
        RECT  51 2.137 51.12 23.783 ;
        RECT  45.6 2.137 45.72 23.783 ;
        RECT  40.2 2.137 40.32 23.783 ;
        RECT  34.8 2.137 34.92 23.783 ;
        RECT  29.4 2.137 29.52 23.783 ;
        RECT  24 2.137 24.12 23.783 ;
        RECT  18.6 2.137 18.72 23.783 ;
        RECT  13.2 2.137 13.32 23.783 ;
        RECT  7.8 2.137 7.92 23.783 ;
        RECT  2.4 2.137 2.52 23.783 ;
    END
  END VSS
  OBS
    LAYER RVTN ;
     RECT  2.16 2.16 142.128 2.295 ;
     RECT  2.16 2.565 142.128 2.835 ;
     RECT  2.16 3.105 142.128 3.375 ;
     RECT  2.16 3.645 142.128 3.915 ;
     RECT  2.16 4.185 142.128 4.455 ;
     RECT  2.16 4.725 142.128 4.995 ;
     RECT  2.16 5.265 142.128 5.535 ;
     RECT  2.16 5.805 142.128 6.075 ;
     RECT  2.16 6.345 142.128 6.615 ;
     RECT  2.16 6.885 142.128 7.155 ;
     RECT  2.16 7.425 142.128 7.695 ;
     RECT  2.16 7.965 142.128 8.235 ;
     RECT  2.16 8.505 142.128 8.775 ;
     RECT  2.16 9.045 142.128 9.315 ;
     RECT  2.16 9.585 142.128 9.855 ;
     RECT  2.16 10.125 142.128 10.395 ;
     RECT  2.16 10.665 142.128 10.935 ;
     RECT  2.16 11.205 142.128 11.475 ;
     RECT  2.16 11.745 142.128 12.015 ;
     RECT  2.16 12.285 142.128 12.555 ;
     RECT  2.16 12.825 142.128 13.095 ;
     RECT  2.16 13.365 142.128 13.635 ;
     RECT  2.16 13.905 142.128 14.175 ;
     RECT  2.16 14.445 142.128 14.715 ;
     RECT  2.16 14.985 142.128 15.255 ;
     RECT  2.16 15.525 142.128 15.795 ;
     RECT  2.16 16.065 142.128 16.335 ;
     RECT  2.16 16.605 142.128 16.875 ;
     RECT  2.16 17.145 142.128 17.415 ;
     RECT  2.16 17.685 142.128 17.955 ;
     RECT  2.16 18.225 142.128 18.495 ;
     RECT  2.16 18.765 142.128 19.035 ;
     RECT  2.16 19.305 142.128 19.575 ;
     RECT  2.16 19.845 142.128 20.115 ;
     RECT  2.16 20.385 142.128 20.655 ;
     RECT  2.16 20.925 142.128 21.195 ;
     RECT  2.16 21.465 142.128 21.735 ;
     RECT  2.16 22.005 142.128 22.275 ;
     RECT  2.16 22.545 142.128 22.815 ;
     RECT  2.16 23.085 142.128 23.355 ;
     RECT  2.16 23.625 142.128 23.76 ;
    LAYER RVTP ;
     RECT  2.16 2.295 142.128 2.565 ;
     RECT  2.16 2.835 142.128 3.105 ;
     RECT  2.16 3.375 142.128 3.645 ;
     RECT  2.16 3.915 142.128 4.185 ;
     RECT  2.16 4.455 142.128 4.725 ;
     RECT  2.16 4.995 142.128 5.265 ;
     RECT  2.16 5.535 142.128 5.805 ;
     RECT  2.16 6.075 142.128 6.345 ;
     RECT  2.16 6.615 142.128 6.885 ;
     RECT  2.16 7.155 142.128 7.425 ;
     RECT  2.16 7.695 142.128 7.965 ;
     RECT  2.16 8.235 142.128 8.505 ;
     RECT  2.16 8.775 142.128 9.045 ;
     RECT  2.16 9.315 142.128 9.585 ;
     RECT  2.16 9.855 142.128 10.125 ;
     RECT  2.16 10.395 142.128 10.665 ;
     RECT  2.16 10.935 142.128 11.205 ;
     RECT  2.16 11.475 142.128 11.745 ;
     RECT  2.16 12.015 142.128 12.285 ;
     RECT  2.16 12.555 142.128 12.825 ;
     RECT  2.16 13.095 142.128 13.365 ;
     RECT  2.16 13.635 142.128 13.905 ;
     RECT  2.16 14.175 142.128 14.445 ;
     RECT  2.16 14.715 142.128 14.985 ;
     RECT  2.16 15.255 142.128 15.525 ;
     RECT  2.16 15.795 142.128 16.065 ;
     RECT  2.16 16.335 142.128 16.605 ;
     RECT  2.16 16.875 142.128 17.145 ;
     RECT  2.16 17.415 142.128 17.685 ;
     RECT  2.16 17.955 142.128 18.225 ;
     RECT  2.16 18.495 142.128 18.765 ;
     RECT  2.16 19.035 142.128 19.305 ;
     RECT  2.16 19.575 142.128 19.845 ;
     RECT  2.16 20.115 142.128 20.385 ;
     RECT  2.16 20.655 142.128 20.925 ;
     RECT  2.16 21.195 142.128 21.465 ;
     RECT  2.16 21.735 142.128 22.005 ;
     RECT  2.16 22.275 142.128 22.545 ;
     RECT  2.16 22.815 142.128 23.085 ;
     RECT  2.16 23.355 142.128 23.625 ;
    LAYER M1 ;
     RECT  2.16 2.151 142.128 23.769 ;
    LAYER M2 ;
     RECT  1.039 2.034 1.903 2.052 ;
     RECT  1.903 2.034 2.083 2.124 ;
     RECT  1.363 3.186 2.083 3.204 ;
     RECT  2.083 2.034 2.16 3.204 ;
     RECT  1.687 22.518 2.16 22.536 ;
     RECT  2.16 2.034 4.163 23.769 ;
     RECT  4.163 2.151 6.223 23.769 ;
     RECT  6.223 2.106 6.611 23.769 ;
     RECT  6.611 2.151 9.103 23.769 ;
     RECT  9.103 2.106 9.419 23.769 ;
     RECT  9.419 2.151 10.363 23.769 ;
     RECT  10.363 2.106 11.147 23.769 ;
     RECT  11.147 2.151 11.911 23.769 ;
     RECT  11.911 2.106 13.379 23.769 ;
     RECT  13.379 2.151 14.539 23.769 ;
     RECT  14.539 2.106 15.827 23.769 ;
     RECT  15.827 2.151 19.327 23.769 ;
     RECT  19.327 2.106 19.787 23.769 ;
     RECT  19.787 2.151 22.711 23.769 ;
     RECT  22.711 2.106 23.963 23.769 ;
     RECT  24.871 1.152 25.007 1.17 ;
     RECT  23.963 2.151 25.015 23.769 ;
     RECT  25.015 2.106 25.439 23.769 ;
     RECT  25.439 2.151 27.715 23.769 ;
     RECT  27.715 2.106 28.319 23.769 ;
     RECT  28.319 2.151 29.551 23.769 ;
     RECT  29.551 2.106 29.867 23.769 ;
     RECT  29.867 2.151 31.135 23.769 ;
     RECT  31.135 2.106 31.595 23.769 ;
     RECT  31.595 2.151 32.359 23.769 ;
     RECT  32.359 2.106 32.999 23.769 ;
     RECT  32.999 2.151 34.195 23.769 ;
     RECT  34.195 2.034 34.483 23.769 ;
     RECT  34.483 1.962 35.087 23.769 ;
     RECT  35.087 2.106 39.011 23.769 ;
     RECT  39.011 2.151 88.303 23.769 ;
     RECT  88.303 2.106 88.411 23.769 ;
     RECT  88.411 2.034 88.799 23.769 ;
     RECT  88.799 2.07 89.051 23.769 ;
     RECT  89.051 2.151 91.291 23.769 ;
     RECT  91.291 2.106 93.227 23.769 ;
     RECT  93.227 2.151 95.395 23.769 ;
     RECT  95.395 2.106 96.503 23.769 ;
     RECT  96.503 2.151 100.867 23.769 ;
     RECT  100.867 2.106 101.219 23.769 ;
     RECT  101.219 2.151 102.091 23.769 ;
     RECT  102.091 2.106 104.567 23.769 ;
     RECT  104.567 2.151 105.907 23.769 ;
     RECT  105.907 2.106 106.439 23.769 ;
     RECT  106.439 2.151 111.991 23.769 ;
     RECT  111.991 2.106 112.703 23.769 ;
     RECT  112.703 2.151 115.591 23.769 ;
     RECT  115.591 2.106 116.051 23.769 ;
     RECT  116.051 2.151 117.895 23.769 ;
     RECT  117.895 2.106 118.211 23.769 ;
     RECT  118.211 2.151 120.055 23.769 ;
     RECT  120.055 2.106 120.695 23.769 ;
     RECT  120.695 2.151 123.475 23.769 ;
     RECT  123.475 2.106 124.583 23.769 ;
     RECT  124.583 2.151 125.815 23.769 ;
     RECT  125.815 2.106 126.311 23.769 ;
     RECT  126.311 2.151 128.119 23.769 ;
     RECT  128.119 2.106 128.471 23.769 ;
     RECT  128.471 2.151 129.235 23.769 ;
     RECT  129.235 2.106 129.767 23.769 ;
     RECT  129.767 2.151 133.519 23.769 ;
     RECT  133.519 2.106 134.627 23.769 ;
     RECT  134.627 2.151 136.723 23.769 ;
     RECT  136.723 2.106 137.803 23.769 ;
     RECT  137.803 1.962 139.343 23.769 ;
     RECT  140.467 1.152 140.567 1.17 ;
     RECT  139.343 2.034 141.251 23.769 ;
     RECT  141.251 2.07 141.971 23.769 ;
     RECT  141.971 2.106 142.128 23.769 ;
     RECT  142.128 2.106 142.151 9.774 ;
     RECT  142.128 22.626 142.151 22.644 ;
     RECT  142.151 5.616 142.187 5.634 ;
     RECT  142.151 6.426 142.187 9.774 ;
     RECT  142.151 2.106 142.223 3.978 ;
     RECT  142.187 8.784 142.223 9.774 ;
     RECT  142.151 4.806 142.259 4.824 ;
     RECT  142.187 6.426 142.259 7.416 ;
     RECT  142.223 8.784 142.259 9.072 ;
     RECT  142.259 6.426 142.331 6.444 ;
     RECT  142.259 8.784 142.331 8.802 ;
     RECT  142.128 18.396 142.331 21.528 ;
     RECT  142.223 2.106 142.511 3.744 ;
     RECT  142.511 2.34 142.655 3.744 ;
     RECT  142.331 18.396 143.051 19.098 ;
     RECT  142.331 19.89 143.231 21.528 ;
     RECT  142.655 2.376 143.375 3.744 ;
     RECT  143.051 19.08 143.411 19.098 ;
     RECT  143.231 19.89 143.627 20.718 ;
     RECT  143.627 20.358 143.771 20.718 ;
     RECT  143.375 3.006 143.915 3.744 ;
     RECT  143.915 3.726 144.095 3.744 ;
     RECT  143.231 21.51 144.131 21.528 ;
     RECT  143.771 20.358 144.275 20.376 ;
    LAYER M3 ;
     RECT  140.472 0.043 140.49 0.091 ;
     RECT  11.16 0.091 11.178 0.139 ;
     RECT  11.952 0.091 12.978 0.139 ;
     RECT  20.52 0.091 20.97 0.139 ;
     RECT  95.724 0.091 95.742 0.139 ;
     RECT  111.024 0.091 111.582 0.139 ;
     RECT  119.016 0.091 119.754 0.139 ;
     RECT  133.272 0.091 133.29 0.139 ;
     RECT  136.944 0.091 136.962 0.139 ;
     RECT  139.968 0.091 141.282 0.139 ;
     RECT  103.5 0.091 103.914 0.187 ;
     RECT  100.152 0.091 100.494 0.523 ;
     RECT  103.5 0.187 103.95 0.523 ;
     RECT  136.944 0.139 137.178 0.523 ;
     RECT  138.132 0.091 138.69 0.523 ;
     RECT  139.968 0.139 141.498 0.523 ;
     RECT  142.488 0.091 142.506 0.523 ;
     RECT  143.352 0.139 143.37 0.523 ;
     RECT  2.736 0.091 2.754 0.571 ;
     RECT  19.476 0.091 19.494 0.571 ;
     RECT  27.144 0.091 27.702 0.571 ;
     RECT  30.024 0.091 30.042 0.571 ;
     RECT  35.928 0.091 35.946 0.571 ;
     RECT  93.348 0.091 94.554 0.571 ;
     RECT  98.964 0.091 98.982 0.571 ;
     RECT  115.02 0.091 115.038 0.571 ;
     RECT  115.956 0.091 115.974 0.571 ;
     RECT  138.132 0.523 141.498 0.571 ;
     RECT  142.416 0.523 144.09 0.571 ;
     RECT  2.304 0.571 2.754 0.619 ;
     RECT  5.976 0.091 6.714 1.099 ;
     RECT  35.244 0.571 35.946 1.099 ;
     RECT  113.868 0.091 113.886 1.099 ;
     RECT  115.02 0.571 115.974 1.099 ;
     RECT  119.016 0.139 119.862 1.099 ;
     RECT  3.672 0.091 3.69 1.147 ;
     RECT  20.34 0.139 20.97 1.147 ;
     RECT  30.024 0.571 30.474 1.147 ;
     RECT  110.952 0.139 111.582 1.147 ;
     RECT  106.056 0.523 106.074 1.675 ;
     RECT  2.304 0.619 2.79 1.723 ;
     RECT  3.672 1.147 4.05 1.723 ;
     RECT  5.976 1.099 7.002 1.723 ;
     RECT  7.776 0.091 7.794 1.723 ;
     RECT  9.288 0.091 9.954 1.723 ;
     RECT  11.16 0.139 12.978 1.723 ;
     RECT  16.416 0.571 16.434 1.723 ;
     RECT  19.44 0.571 19.494 1.723 ;
     RECT  20.34 1.147 21.258 1.723 ;
     RECT  22.068 0.091 23.562 1.723 ;
     RECT  24.336 0.091 25.542 1.723 ;
     RECT  26.676 0.571 27.702 1.723 ;
     RECT  28.62 0.091 28.638 1.723 ;
     RECT  29.376 1.147 30.474 1.723 ;
     RECT  31.212 0.091 31.23 1.723 ;
     RECT  32.868 0.571 32.886 1.723 ;
     RECT  35.244 1.099 36.162 1.723 ;
     RECT  38.196 0.091 38.214 1.723 ;
     RECT  87.984 0.091 88.002 1.723 ;
     RECT  89.136 0.091 89.154 1.723 ;
     RECT  90.324 0.091 91.206 1.723 ;
     RECT  93.24 0.571 94.554 1.723 ;
     RECT  95.724 0.139 96.03 1.723 ;
     RECT  96.948 0.091 96.966 1.723 ;
     RECT  98.928 0.571 98.982 1.723 ;
     RECT  100.116 0.523 100.494 1.723 ;
     RECT  101.232 0.091 102.51 1.723 ;
     RECT  103.5 0.523 103.986 1.723 ;
     RECT  106.056 1.675 106.614 1.723 ;
     RECT  107.46 0.091 107.478 1.723 ;
     RECT  108.216 0.091 108.234 1.723 ;
     RECT  109.188 0.091 109.782 1.723 ;
     RECT  110.952 1.147 112.122 1.723 ;
     RECT  113.004 0.091 113.022 1.723 ;
     RECT  113.868 1.099 115.974 1.723 ;
     RECT  116.856 0.091 117.882 1.723 ;
     RECT  119.016 1.099 119.97 1.723 ;
     RECT  122.832 0.091 122.85 1.723 ;
     RECT  123.984 0.091 124.542 1.723 ;
     RECT  125.748 0.091 127.602 1.723 ;
     RECT  128.412 0.091 128.43 1.723 ;
     RECT  129.816 0.091 130.302 1.723 ;
     RECT  131.544 0.091 131.742 1.723 ;
     RECT  133.164 0.139 133.29 1.723 ;
     RECT  134.244 0.091 135.99 1.723 ;
     RECT  136.944 0.523 137.394 1.723 ;
     RECT  138.132 0.571 144.09 1.723 ;
     RECT  4.968 1.723 38.214 1.771 ;
     RECT  87.984 1.723 120.078 1.819 ;
     RECT  120.816 1.723 144.09 1.819 ;
     RECT  1.908 1.723 4.05 2.029 ;
     RECT  1.044 1.723 1.062 2.057 ;
     RECT  4.968 1.771 38.25 2.101 ;
     RECT  39.096 1.723 39.114 2.101 ;
     RECT  1.908 2.029 4.158 2.129 ;
     RECT  2.088 2.129 4.158 2.155 ;
     RECT  4.968 2.101 39.114 2.155 ;
     RECT  2.088 2.155 39.114 2.263 ;
     RECT  40.215 2.143 40.305 2.413 ;
     RECT  45.615 2.143 45.705 2.413 ;
     RECT  51.015 2.143 51.105 2.413 ;
     RECT  56.415 2.143 56.505 2.413 ;
     RECT  61.815 2.143 61.905 2.413 ;
     RECT  67.215 2.143 67.305 2.413 ;
     RECT  72.615 2.143 72.705 2.413 ;
     RECT  78.015 2.143 78.105 2.413 ;
     RECT  83.415 2.143 83.505 2.413 ;
     RECT  87.984 1.819 144.09 2.641 ;
     RECT  2.088 2.263 39.33 2.669 ;
     RECT  1.368 2.875 1.386 3.209 ;
     RECT  2.268 2.669 39.33 3.299 ;
     RECT  87.84 2.641 144.09 3.451 ;
     RECT  87.552 3.451 144.09 3.569 ;
     RECT  143.496 3.569 144.09 3.677 ;
     RECT  144.072 3.677 144.09 3.749 ;
     RECT  2.268 3.299 39.222 3.869 ;
     RECT  2.304 3.869 39.222 4.379 ;
     RECT  2.304 4.379 39.114 4.415 ;
     RECT  2.304 4.415 39.078 4.649 ;
     RECT  87.552 3.569 142.218 4.801 ;
     RECT  87.552 4.801 142.254 5.029 ;
     RECT  87.516 5.029 142.254 5.069 ;
     RECT  2.304 4.649 38.754 5.639 ;
     RECT  87.552 5.069 142.254 6.421 ;
     RECT  87.552 6.421 142.326 6.719 ;
     RECT  99.576 6.719 142.326 7.079 ;
     RECT  2.304 5.639 38.502 7.385 ;
     RECT  87.552 6.719 98.802 7.421 ;
     RECT  102.096 7.079 142.326 7.421 ;
     RECT  12.708 7.385 38.502 8.159 ;
     RECT  87.552 7.421 97.398 8.159 ;
     RECT  88.272 8.159 97.398 8.275 ;
     RECT  98.136 7.421 98.802 8.275 ;
     RECT  99.576 7.079 101.214 8.275 ;
     RECT  102.096 7.421 134.694 8.275 ;
     RECT  135.468 7.421 142.326 8.275 ;
     RECT  17.1 8.159 38.502 8.429 ;
     RECT  88.272 8.275 98.802 8.429 ;
     RECT  2.304 7.385 11.79 8.509 ;
     RECT  88.524 8.429 98.802 8.539 ;
     RECT  99.54 8.275 101.214 8.539 ;
     RECT  102.096 8.275 142.326 8.539 ;
     RECT  17.1 8.429 38.286 8.699 ;
     RECT  88.524 8.539 142.326 8.807 ;
     RECT  88.524 8.807 142.254 9.077 ;
     RECT  12.708 8.159 16.29 9.085 ;
     RECT  17.1 8.699 38.214 9.085 ;
     RECT  2.304 8.509 11.97 9.115 ;
     RECT  12.708 9.085 38.214 9.115 ;
     RECT  88.524 9.077 142.218 9.779 ;
     RECT  88.524 9.779 141.966 9.851 ;
     RECT  88.524 9.851 141.786 10.319 ;
     RECT  2.304 9.115 38.214 10.589 ;
     RECT  88.524 10.319 141.678 10.859 ;
     RECT  2.415 10.589 38.214 12.451 ;
     RECT  2.415 12.451 38.394 12.559 ;
     RECT  73.62 12.571 73.638 12.857 ;
     RECT  2.415 12.559 38.466 12.901 ;
     RECT  72.615 2.413 72.897 12.901 ;
     RECT  72.072 12.901 72.897 13.085 ;
     RECT  88.524 10.859 141.642 13.703 ;
     RECT  88.596 13.703 141.642 14.989 ;
     RECT  2.415 12.901 38.718 15.359 ;
     RECT  2.415 15.359 24.894 15.961 ;
     RECT  2.34 15.961 24.894 16.259 ;
     RECT  88.596 14.989 141.678 16.267 ;
     RECT  9.396 16.259 24.894 16.537 ;
     RECT  25.632 15.359 38.718 16.537 ;
     RECT  88.596 16.267 141.966 16.799 ;
     RECT  114.588 16.799 141.966 16.951 ;
     RECT  2.34 16.259 8.658 17.113 ;
     RECT  9.396 16.537 38.718 17.113 ;
     RECT  2.34 17.113 38.718 17.339 ;
     RECT  2.34 17.339 38.646 17.879 ;
     RECT  88.596 16.799 113.778 17.995 ;
     RECT  114.588 16.951 142.074 17.995 ;
     RECT  88.596 17.995 142.074 18.419 ;
     RECT  88.596 18.419 123.606 18.455 ;
     RECT  143.028 18.391 143.046 19.075 ;
     RECT  2.34 17.879 11.97 19.237 ;
     RECT  2.196 19.237 11.97 19.543 ;
     RECT  12.708 17.879 38.646 19.543 ;
     RECT  124.344 18.419 142.074 19.543 ;
     RECT  143.028 19.075 143.406 19.543 ;
     RECT  124.344 19.543 143.406 19.885 ;
     RECT  88.74 18.455 123.606 19.921 ;
     RECT  124.344 19.885 143.622 19.921 ;
     RECT  88.74 19.921 143.622 20.353 ;
     RECT  88.74 20.353 144.27 20.683 ;
     RECT  88.272 20.683 144.27 20.821 ;
     RECT  2.196 19.543 38.646 22.199 ;
     RECT  2.196 22.199 38.502 22.513 ;
     RECT  1.692 22.513 38.502 22.589 ;
     RECT  87.732 20.821 144.27 22.649 ;
     RECT  2.232 22.589 38.502 23.009 ;
     RECT  2.232 23.009 38.394 23.279 ;
     RECT  87.84 22.649 144.27 23.501 ;
     RECT  40.215 2.413 40.497 23.507 ;
     RECT  45.615 2.413 45.897 23.507 ;
     RECT  51.015 2.413 51.297 23.507 ;
     RECT  56.415 2.413 56.697 23.507 ;
     RECT  61.815 2.413 62.097 23.507 ;
     RECT  67.215 2.413 67.497 23.507 ;
     RECT  72.615 13.085 72.897 23.507 ;
     RECT  78.015 2.413 78.297 23.507 ;
     RECT  83.415 2.413 83.697 23.507 ;
     RECT  2.232 23.279 38.178 23.549 ;
     RECT  87.84 23.501 106.758 23.549 ;
     RECT  107.568 23.501 144.27 23.549 ;
     RECT  34.092 23.549 38.178 23.585 ;
     RECT  2.232 23.549 33.354 23.621 ;
     RECT  117.216 23.549 131.274 23.621 ;
     RECT  4.032 23.621 33.354 23.657 ;
     RECT  107.568 23.549 116.154 23.657 ;
     RECT  117.792 23.621 131.274 23.657 ;
     RECT  132.015 23.549 144.27 23.657 ;
     RECT  87.84 23.549 87.858 23.665 ;
     RECT  4.032 23.657 31.266 23.693 ;
     RECT  132.015 23.657 140.526 23.693 ;
     RECT  2.232 23.621 3.294 23.729 ;
     RECT  4.032 23.693 15.174 23.729 ;
     RECT  15.948 23.693 20.79 23.729 ;
     RECT  32.004 23.657 33.354 23.729 ;
     RECT  34.092 23.585 37.962 23.729 ;
     RECT  91.26 23.549 93.474 23.729 ;
     RECT  96.3 23.549 100.854 23.729 ;
     RECT  107.676 23.657 116.154 23.729 ;
     RECT  117.792 23.657 124.398 23.729 ;
     RECT  125.208 23.657 129.87 23.729 ;
     RECT  40.215 23.507 40.305 23.777 ;
     RECT  45.615 23.507 45.705 23.777 ;
     RECT  51.015 23.507 51.105 23.777 ;
     RECT  56.415 23.507 56.505 23.777 ;
     RECT  61.815 23.507 61.905 23.777 ;
     RECT  67.215 23.507 67.305 23.777 ;
     RECT  72.615 23.507 72.705 23.777 ;
     RECT  78.015 23.507 78.105 23.777 ;
     RECT  83.415 23.507 83.505 23.777 ;
     RECT  94.215 23.549 95.526 23.777 ;
     RECT  98.424 23.729 100.854 23.777 ;
     RECT  121.215 23.729 123.21 23.777 ;
     RECT  126.615 23.729 129.87 23.777 ;
     RECT  132.015 23.693 132.354 23.777 ;
     RECT  21.744 23.693 31.266 23.837 ;
     RECT  21.744 23.837 22.842 23.885 ;
     RECT  32.004 23.729 32.238 23.885 ;
     RECT  88.596 23.549 90.486 23.885 ;
     RECT  93.024 23.729 93.474 23.885 ;
     RECT  2.304 23.729 3.186 23.933 ;
     RECT  4.032 23.729 10.962 23.933 ;
     RECT  11.808 23.729 15.174 23.933 ;
     RECT  17.64 23.729 20.79 23.933 ;
     RECT  21.852 23.885 22.842 23.933 ;
     RECT  23.58 23.837 31.266 23.933 ;
     RECT  32.112 23.885 32.238 23.933 ;
     RECT  34.092 23.729 35.154 23.933 ;
     RECT  35.892 23.729 37.962 23.933 ;
     RECT  87.516 23.665 87.858 23.933 ;
     RECT  91.296 23.729 92.286 23.933 ;
     RECT  93.24 23.885 93.474 23.933 ;
     RECT  94.5 23.777 95.526 23.933 ;
     RECT  96.3 23.729 97.686 23.933 ;
     RECT  98.424 23.777 99.594 23.933 ;
     RECT  101.772 23.549 106.614 23.933 ;
     RECT  111.6 23.729 116.154 23.933 ;
     RECT  117.792 23.729 120.366 23.933 ;
     RECT  121.644 23.777 123.21 23.933 ;
     RECT  125.208 23.729 125.658 23.933 ;
     RECT  126.756 23.777 129.87 23.933 ;
     RECT  130.824 23.657 131.274 23.933 ;
     RECT  133.092 23.693 140.526 23.933 ;
     RECT  4.284 23.933 4.986 23.981 ;
     RECT  5.796 23.933 5.814 23.981 ;
     RECT  14.004 23.933 14.202 23.981 ;
     RECT  25.416 23.933 31.266 23.981 ;
     RECT  34.092 23.933 34.974 23.981 ;
     RECT  94.536 23.933 95.202 23.981 ;
     RECT  96.3 23.933 96.75 23.981 ;
     RECT  115.776 23.933 115.794 23.981 ;
     RECT  121.788 23.933 123.21 23.981 ;
     RECT  127.836 23.933 129.222 23.981 ;
     RECT  133.092 23.933 135.162 23.981 ;
     RECT  17.64 23.933 18.378 24.029 ;
     RECT  110.34 23.729 110.574 24.029 ;
     RECT  122.652 23.981 122.67 24.029 ;
     RECT  6.732 23.933 8.442 24.461 ;
     RECT  19.368 23.933 20.502 24.461 ;
     RECT  6.732 24.461 8.226 24.509 ;
     RECT  17.64 24.029 17.658 24.509 ;
     RECT  19.368 24.461 19.386 24.509 ;
     RECT  32.22 23.933 32.238 24.509 ;
     RECT  107.676 23.729 109.602 24.509 ;
     RECT  110.556 24.029 110.574 24.509 ;
     RECT  131.004 23.933 131.274 24.509 ;
     RECT  133.092 23.981 134.262 24.509 ;
     RECT  6.732 24.509 7.434 24.557 ;
     RECT  11.808 23.933 11.826 24.557 ;
     RECT  15.948 23.729 16.902 24.557 ;
     RECT  20.376 24.461 20.502 24.557 ;
     RECT  22.644 23.933 22.662 24.557 ;
     RECT  25.416 23.981 26.874 24.557 ;
     RECT  27.684 23.981 31.266 24.557 ;
     RECT  33.336 23.729 33.354 24.557 ;
     RECT  34.956 23.981 34.974 24.557 ;
     RECT  88.632 23.885 90.486 24.557 ;
     RECT  94.536 23.981 94.662 24.557 ;
     RECT  96.3 23.981 96.318 24.557 ;
     RECT  99.576 23.933 99.594 24.557 ;
     RECT  102.348 23.933 104.85 24.557 ;
     RECT  108.9 24.509 109.602 24.557 ;
     RECT  111.816 23.933 114.858 24.557 ;
     RECT  117.9 23.933 118.026 24.557 ;
     RECT  119.052 23.933 120.078 24.557 ;
     RECT  121.788 23.981 121.806 24.557 ;
     RECT  124.164 23.729 124.398 24.557 ;
     RECT  127.008 23.933 127.026 24.557 ;
     RECT  136.188 23.933 137.034 24.557 ;
     RECT  27.684 24.557 30.006 24.605 ;
     RECT  89.82 24.557 89.838 24.605 ;
     RECT  113.976 24.557 114.462 24.605 ;
     RECT  117.9 24.557 117.918 24.605 ;
     RECT  119.052 24.557 119.898 24.605 ;
     RECT  124.164 24.557 124.182 24.605 ;
     RECT  136.188 24.557 136.854 24.605 ;
     RECT  28.62 24.605 29.646 24.653 ;
     RECT  29.556 24.653 29.646 24.989 ;
     RECT  131.004 24.509 131.094 24.989 ;
     RECT  23.796 23.933 24.534 25.037 ;
     RECT  16.452 24.557 16.902 25.085 ;
     RECT  29.556 24.989 29.574 25.085 ;
     RECT  30.816 24.557 31.266 25.085 ;
     RECT  88.632 24.557 88.794 25.085 ;
     RECT  93.384 23.933 93.474 25.085 ;
     RECT  106.596 23.933 106.614 25.085 ;
     RECT  108.9 24.557 108.918 25.085 ;
     RECT  113.976 24.605 113.994 25.085 ;
     RECT  125.208 23.933 125.334 25.085 ;
     RECT  131.004 24.989 131.058 25.085 ;
     RECT  132.228 23.777 132.354 25.085 ;
     RECT  133.092 24.509 133.254 25.085 ;
     RECT  137.952 23.933 138.15 25.085 ;
     RECT  7.416 24.557 7.434 25.133 ;
     RECT  14.184 23.981 14.202 25.133 ;
     RECT  20.484 24.557 20.502 25.133 ;
     RECT  23.832 25.037 24.534 25.133 ;
     RECT  25.416 24.557 26.082 25.133 ;
     RECT  35.892 23.933 36.486 25.133 ;
     RECT  88.632 25.085 88.65 25.133 ;
     RECT  92.16 23.933 92.286 25.133 ;
     RECT  93.384 25.085 93.402 25.133 ;
     RECT  94.536 24.557 94.554 25.133 ;
     RECT  97.668 23.933 97.686 25.133 ;
     RECT  98.424 23.933 98.586 25.133 ;
     RECT  100.332 23.777 100.854 25.133 ;
     RECT  102.996 24.557 103.734 25.133 ;
     RECT  104.832 24.557 104.85 25.133 ;
     RECT  111.816 24.557 112.05 25.133 ;
     RECT  125.208 25.085 125.226 25.133 ;
     RECT  127.836 23.981 127.854 25.133 ;
     RECT  132.336 25.085 132.354 25.133 ;
     RECT  133.128 25.085 133.254 25.133 ;
     RECT  133.992 24.509 134.262 25.133 ;
     RECT  137.952 25.085 137.97 25.133 ;
     RECT  139.104 23.933 140.526 25.133 ;
     RECT  92.268 25.133 92.286 25.181 ;
     RECT  139.104 25.133 139.482 25.181 ;
     RECT  135.144 23.981 135.162 25.661 ;
     RECT  25.416 25.133 25.722 25.757 ;
     RECT  2.844 23.933 2.862 25.805 ;
     RECT  4.968 23.981 4.986 25.805 ;
     RECT  8.208 24.509 8.226 25.805 ;
     RECT  24.516 25.133 24.534 25.805 ;
     RECT  25.416 25.757 25.434 25.805 ;
     RECT  26.856 24.557 26.874 25.805 ;
     RECT  27.684 24.605 27.702 25.805 ;
     RECT  28.62 24.653 28.638 25.805 ;
     RECT  30.816 25.085 30.834 25.805 ;
     RECT  87.516 23.933 87.534 25.805 ;
     RECT  98.568 25.133 98.586 25.805 ;
     RECT  100.332 25.133 100.35 25.805 ;
     RECT  107.676 24.509 107.694 25.805 ;
     RECT  111.816 25.133 111.834 25.805 ;
     RECT  113.22 24.557 113.238 25.805 ;
     RECT  119.052 24.605 119.07 25.805 ;
     RECT  119.88 24.605 119.898 25.805 ;
     RECT  128.772 23.981 129.222 25.805 ;
     RECT  131.004 25.085 131.022 25.805 ;
     RECT  133.128 25.133 133.146 25.805 ;
     RECT  134.244 25.133 134.262 25.805 ;
     RECT  136.188 24.605 136.602 25.805 ;
     RECT  139.104 25.181 139.122 25.805 ;
     RECT  140.508 25.133 140.526 25.805 ;
     RECT  141.444 23.657 144.27 25.805 ;
     RECT  72.144 25.099 72.162 25.901 ;
    LAYER M4 ;
     RECT  1.313 2.88 1.397 2.904 ;
     RECT  1.333 21.792 1.525 21.816 ;
     RECT  1.141 0.624 1.669 0.648 ;
     RECT  1.141 20.736 1.861 20.76 ;
     RECT  1.525 21.792 1.861 22.584 ;
     RECT  1.861 20.736 2.053 22.584 ;
     RECT  2.053 20.736 2.245 22.632 ;
     RECT  0.997 23.904 2.245 23.928 ;
     RECT  1.525 3.408 2.257 3.432 ;
     RECT  1.669 25.776 2.293 25.8 ;
     RECT  0.989 1.728 2.389 1.752 ;
     RECT  2.389 1.728 2.408 1.8 ;
     RECT  2.257 3.408 2.408 3.864 ;
     RECT  2.365 5.184 2.408 5.208 ;
     RECT  2.293 6.576 2.408 6.6 ;
     RECT  2.365 8.016 2.408 8.04 ;
     RECT  2.365 17.472 2.408 17.496 ;
     RECT  2.365 18.528 2.408 18.552 ;
     RECT  2.245 20.736 2.408 23.928 ;
     RECT  1.669 0.576 2.581 0.648 ;
     RECT  2.408 1.728 2.704 23.928 ;
     RECT  2.293 25.728 2.773 25.8 ;
     RECT  2.581 0.096 2.801 0.648 ;
     RECT  2.704 20.4 2.801 23.928 ;
     RECT  2.704 5.04 2.819 8.568 ;
     RECT  2.704 16.272 2.819 19.416 ;
     RECT  2.819 16.272 2.867 17.496 ;
     RECT  2.801 20.448 2.867 23.928 ;
     RECT  2.773 25.632 2.873 25.8 ;
     RECT  2.867 20.448 2.915 21.432 ;
     RECT  2.819 8.016 3.089 8.568 ;
     RECT  2.867 22.704 3.169 23.928 ;
     RECT  2.873 25.632 3.395 25.656 ;
     RECT  2.704 1.728 3.443 3.96 ;
     RECT  2.867 16.272 3.485 16.536 ;
     RECT  3.169 22.752 3.539 23.928 ;
     RECT  3.089 8.544 3.601 8.568 ;
     RECT  2.819 5.04 3.629 6.984 ;
     RECT  3.443 1.728 3.673 3.432 ;
     RECT  3.485 16.512 3.673 16.536 ;
     RECT  2.801 0.096 3.701 0.12 ;
     RECT  2.819 18.528 3.869 19.416 ;
     RECT  2.915 20.448 3.869 21.144 ;
     RECT  2.704 11.904 3.923 12.552 ;
     RECT  2.704 10.272 3.953 10.296 ;
     RECT  3.673 1.728 4.021 2.904 ;
     RECT  3.923 11.904 4.021 12.024 ;
     RECT  4.021 1.152 4.105 2.904 ;
     RECT  4.021 11.856 4.165 12.024 ;
     RECT  4.165 11.52 4.273 12.024 ;
     RECT  3.539 23.376 4.273 23.928 ;
     RECT  4.273 23.376 4.3 23.976 ;
     RECT  3.869 18.528 4.309 21.144 ;
     RECT  4.273 11.424 4.381 12.024 ;
     RECT  4.3 23.904 4.429 23.976 ;
     RECT  4.381 10.848 4.465 12.024 ;
     RECT  4.309 17.616 4.525 21.144 ;
     RECT  4.489 22.224 4.525 22.248 ;
     RECT  4.525 17.616 4.601 22.248 ;
     RECT  4.601 18.528 4.633 22.248 ;
     RECT  4.633 18.528 4.643 22.296 ;
     RECT  4.105 1.728 4.709 2.904 ;
     RECT  4.597 25.728 4.787 25.752 ;
     RECT  3.629 5.088 4.817 6.984 ;
     RECT  4.817 5.088 4.961 6.84 ;
     RECT  4.465 11.52 4.993 12.024 ;
     RECT  4.913 25.776 4.997 25.8 ;
     RECT  4.961 5.088 5.029 6.6 ;
     RECT  4.643 21.12 5.101 22.296 ;
     RECT  5.101 21.12 5.105 22.776 ;
     RECT  5.029 4.944 5.141 6.6 ;
     RECT  4.993 11.52 5.141 12.552 ;
     RECT  4.709 2.88 5.209 2.904 ;
     RECT  5.105 21.12 5.249 21.672 ;
     RECT  5.141 11.52 5.315 11.544 ;
     RECT  5.209 2.88 5.317 3.336 ;
     RECT  4.643 18.528 5.346 20.04 ;
     RECT  5.276 16.992 5.363 17.016 ;
     RECT  5.141 12.528 5.411 12.552 ;
     RECT  5.317 2.88 5.429 3.864 ;
     RECT  5.346 18.528 5.429 19.992 ;
     RECT  5.429 18.528 5.501 19.608 ;
     RECT  5.501 18.816 5.507 19.608 ;
     RECT  4.429 23.952 5.533 23.976 ;
     RECT  5.507 19.344 5.537 19.608 ;
     RECT  4.709 1.728 5.573 1.848 ;
     RECT  5.249 21.12 5.605 21.144 ;
     RECT  5.429 3.312 5.641 3.864 ;
     RECT  5.105 22.656 5.641 22.776 ;
     RECT  5.533 23.904 5.641 23.976 ;
     RECT  5.605 21.024 5.645 21.144 ;
     RECT  5.537 19.344 6.149 19.368 ;
     RECT  5.645 21.024 6.365 21.048 ;
     RECT  5.641 22.656 6.365 23.976 ;
     RECT  5.641 3.312 6.401 3.96 ;
     RECT  6.365 23.376 6.563 23.976 ;
     RECT  6.517 7.44 6.689 7.464 ;
     RECT  6.541 19.392 6.716 19.416 ;
     RECT  5.141 5.184 6.829 6.312 ;
     RECT  5.573 1.728 6.973 1.8 ;
     RECT  6.401 3.84 7.009 3.96 ;
     RECT  6.829 5.184 7.009 6.936 ;
     RECT  6.973 1.104 7.139 1.8 ;
     RECT  7.139 1.728 7.189 1.8 ;
     RECT  6.721 24.528 7.388 24.552 ;
     RECT  7.388 24.528 7.475 25.128 ;
     RECT  7.009 3.84 7.549 6.936 ;
     RECT  6.716 19.392 7.585 19.704 ;
     RECT  6.757 20.832 7.585 20.952 ;
     RECT  7.513 9.12 7.621 9.144 ;
     RECT  7.189 1.728 7.693 2.76 ;
     RECT  7.549 3.744 7.693 6.936 ;
     RECT  6.563 23.376 7.765 23.496 ;
     RECT  5.077 0.096 7.805 0.12 ;
     RECT  7.693 1.728 7.808 6.936 ;
     RECT  7.621 8.544 7.808 9.144 ;
     RECT  7.585 19.392 7.808 20.952 ;
     RECT  6.685 22.176 7.808 22.2 ;
     RECT  7.765 23.376 7.808 24.504 ;
     RECT  7.808 1.728 8.104 24.504 ;
     RECT  8.104 20.688 8.201 22.872 ;
     RECT  8.201 20.688 8.273 22.728 ;
     RECT  8.104 1.728 8.309 6.936 ;
     RECT  8.309 1.728 8.387 6.312 ;
     RECT  8.104 23.904 8.387 24.504 ;
     RECT  8.387 1.728 8.425 5.736 ;
     RECT  8.387 23.904 8.453 24.456 ;
     RECT  8.273 22.704 8.489 22.728 ;
     RECT  8.425 1.728 9.101 2.28 ;
     RECT  8.149 25.776 9.107 25.8 ;
     RECT  8.453 23.904 9.197 23.928 ;
     RECT  9.197 23.856 9.673 23.928 ;
     RECT  8.425 3.408 9.677 5.736 ;
     RECT  9.673 23.376 9.817 23.928 ;
     RECT  9.677 4.128 9.889 5.736 ;
     RECT  9.385 6.96 9.889 6.984 ;
     RECT  8.273 20.688 9.925 21.672 ;
     RECT  9.817 22.704 9.925 23.928 ;
     RECT  9.925 20.688 10.213 23.928 ;
     RECT  9.889 4.128 10.3 6.984 ;
     RECT  8.104 19.2 10.501 19.224 ;
     RECT  10.213 20.448 10.501 23.928 ;
     RECT  10.501 19.2 10.505 23.928 ;
     RECT  10.505 19.2 10.685 22.248 ;
     RECT  10.3 4.128 10.885 4.152 ;
     RECT  10.885 3.744 10.972 4.152 ;
     RECT  10.685 19.2 11.006 21.72 ;
     RECT  11.006 19.2 11.009 21.672 ;
     RECT  9.205 0.096 11.029 0.12 ;
     RECT  10.885 8.544 11.045 8.568 ;
     RECT  11.029 0.096 11.513 0.168 ;
     RECT  10.972 3.984 11.797 4.152 ;
     RECT  10.3 5.184 11.797 6.264 ;
     RECT  10.505 23.376 11.797 23.928 ;
     RECT  11.797 3.984 11.833 6.264 ;
     RECT  11.833 3.984 11.837 6.888 ;
     RECT  11.009 20.016 11.977 21.672 ;
     RECT  11.437 2.832 12.013 2.856 ;
     RECT  9.101 1.728 12.277 1.848 ;
     RECT  12.013 2.832 12.277 3.528 ;
     RECT  11.797 23.376 12.323 24.552 ;
     RECT  12.323 23.376 12.337 23.928 ;
     RECT  11.837 4.512 12.553 6.888 ;
     RECT  11.977 19.968 12.769 21.672 ;
     RECT  12.337 22.704 12.769 23.928 ;
     RECT  11.513 0.096 12.989 0.12 ;
     RECT  12.769 19.968 13.045 23.928 ;
     RECT  12.277 1.728 13.093 3.528 ;
     RECT  12.553 4.512 13.093 6.936 ;
     RECT  13.093 1.728 13.208 6.936 ;
     RECT  12.805 7.968 13.208 7.992 ;
     RECT  12.509 9.12 13.208 9.144 ;
     RECT  13.093 12 13.208 12.024 ;
     RECT  13.045 19.632 13.208 23.928 ;
     RECT  13.208 1.728 13.504 23.928 ;
     RECT  13.504 12 13.565 12.024 ;
     RECT  13.504 5.088 13.601 5.832 ;
     RECT  13.333 0.144 13.619 0.168 ;
     RECT  13.189 25.728 13.619 25.752 ;
     RECT  13.504 3.456 13.645 3.48 ;
     RECT  13.504 18.768 13.667 23.928 ;
     RECT  13.667 23.232 13.709 23.928 ;
     RECT  13.504 1.728 13.961 2.376 ;
     RECT  13.709 23.376 13.993 23.928 ;
     RECT  13.667 18.768 14.141 22.104 ;
     RECT  14.141 19.104 14.177 22.104 ;
     RECT  14.177 20.832 14.213 21 ;
     RECT  13.993 23.376 14.291 23.976 ;
     RECT  13.601 5.088 14.581 5.736 ;
     RECT  13.504 7.056 14.581 7.08 ;
     RECT  14.173 25.104 14.819 25.128 ;
     RECT  14.177 19.104 14.897 19.656 ;
     RECT  13.961 1.728 15.001 2.28 ;
     RECT  14.897 19.104 15.257 19.368 ;
     RECT  14.213 20.832 15.361 20.856 ;
     RECT  14.581 5.088 15.365 7.08 ;
     RECT  15.001 1.728 15.437 2.904 ;
     RECT  15.365 5.088 15.761 6.312 ;
     RECT  14.291 23.376 15.937 23.928 ;
     RECT  15.037 3.936 16.021 3.96 ;
     RECT  15.937 23.376 16.067 24.552 ;
     RECT  16.213 0.576 16.445 0.6 ;
     RECT  16.021 3.408 16.553 3.96 ;
     RECT  15.437 1.728 16.621 2.328 ;
     RECT  15.761 5.088 16.94 5.784 ;
     RECT  16.621 1.728 16.985 2.952 ;
     RECT  16.985 2.88 16.993 2.952 ;
     RECT  16.94 5.088 17.027 6.312 ;
     RECT  16.441 25.056 17.171 25.08 ;
     RECT  16.993 2.928 17.237 2.952 ;
     RECT  15.257 19.344 17.269 19.368 ;
     RECT  15.361 20.496 17.269 20.856 ;
     RECT  14.177 22.08 17.269 22.104 ;
     RECT  17.269 19.344 17.315 22.104 ;
     RECT  16.553 3.936 17.516 3.96 ;
     RECT  17.315 20.16 17.525 22.104 ;
     RECT  17.516 3.36 17.603 3.96 ;
     RECT  16.067 23.376 17.629 23.928 ;
     RECT  17.629 23.376 17.713 24.504 ;
     RECT  17.603 3.408 17.881 3.96 ;
     RECT  17.027 5.088 17.881 5.832 ;
     RECT  16.985 1.728 17.989 1.8 ;
     RECT  17.989 1.728 18.241 2.184 ;
     RECT  17.713 23.376 18.277 24.024 ;
     RECT  17.881 3.408 18.469 5.832 ;
     RECT  18.241 1.728 18.608 2.28 ;
     RECT  18.469 3.408 18.608 6.264 ;
     RECT  17.525 20.16 18.608 21.528 ;
     RECT  18.277 22.56 18.608 24.024 ;
     RECT  18.608 1.728 18.904 24.024 ;
     RECT  18.904 5.04 19.001 5.832 ;
     RECT  18.904 2.88 19.109 3.96 ;
     RECT  19.001 5.04 19.145 5.784 ;
     RECT  18.904 22.56 19.325 24.024 ;
     RECT  19.325 23.376 19.357 24.024 ;
     RECT  18.904 1.728 19.397 1.848 ;
     RECT  18.904 6.864 19.397 6.888 ;
     RECT  18.709 0.096 19.429 0.12 ;
     RECT  19.429 0.096 19.513 0.6 ;
     RECT  19.357 23.376 19.649 24.504 ;
     RECT  19.109 2.88 19.829 2.904 ;
     RECT  19.717 25.776 19.859 25.8 ;
     RECT  19.145 5.088 20.221 5.784 ;
     RECT  19.649 23.904 20.365 24.504 ;
     RECT  19.513 0.096 20.369 0.168 ;
     RECT  19.109 3.936 20.437 3.96 ;
     RECT  20.365 23.904 20.473 24.552 ;
     RECT  19.397 1.728 20.533 1.752 ;
     RECT  20.473 23.904 20.579 25.128 ;
     RECT  18.904 19.92 20.585 21.528 ;
     RECT  20.579 23.904 20.723 24.552 ;
     RECT  20.221 5.088 20.765 6.456 ;
     RECT  20.369 0.096 20.981 0.12 ;
     RECT  20.723 23.904 21.013 23.928 ;
     RECT  20.533 1.728 21.05 1.8 ;
     RECT  21.013 23.424 21.085 23.928 ;
     RECT  21.05 1.728 21.229 1.752 ;
     RECT  21.229 1.152 21.313 1.752 ;
     RECT  20.585 19.92 21.521 21.144 ;
     RECT  20.437 3.696 21.557 3.96 ;
     RECT  20.725 22.176 21.661 22.2 ;
     RECT  21.085 23.376 21.661 23.928 ;
     RECT  21.557 3.936 21.809 3.96 ;
     RECT  20.765 5.328 22.057 6.456 ;
     RECT  21.661 22.176 22.163 23.928 ;
     RECT  21.521 20.496 22.597 21.144 ;
     RECT  22.163 23.376 22.633 23.928 ;
     RECT  22.597 19.968 22.637 21.144 ;
     RECT  22.604 17.088 22.691 17.112 ;
     RECT  22.645 18.816 22.805 18.84 ;
     RECT  22.637 19.968 22.805 19.992 ;
     RECT  22.501 2.88 22.849 2.904 ;
     RECT  22.777 3.936 22.849 3.96 ;
     RECT  22.637 21.12 22.849 21.144 ;
     RECT  22.163 22.176 22.849 22.2 ;
     RECT  22.805 18.816 22.853 19.992 ;
     RECT  22.633 23.376 22.883 24.552 ;
     RECT  22.853 19.344 22.889 19.992 ;
     RECT  22.849 21.12 22.889 22.2 ;
     RECT  22.057 5.328 23.137 6.696 ;
     RECT  22.849 2.88 23.209 3.96 ;
     RECT  23.137 5.328 23.209 6.84 ;
     RECT  21.313 1.728 23.557 1.752 ;
     RECT  22.889 19.968 23.641 19.992 ;
     RECT  22.889 21.12 23.641 21.672 ;
     RECT  23.785 25.008 23.821 25.032 ;
     RECT  23.821 25.008 23.987 25.128 ;
     RECT  23.557 1.728 24.008 1.8 ;
     RECT  23.209 2.88 24.008 6.84 ;
     RECT  23.029 9.696 24.008 9.72 ;
     RECT  23.641 19.968 24.008 21.672 ;
     RECT  22.883 23.376 24.008 23.928 ;
     RECT  23.987 25.104 24.131 25.128 ;
     RECT  24.008 1.728 24.304 23.928 ;
     RECT  24.304 20.544 24.419 23.928 ;
     RECT  24.419 22.752 24.653 23.928 ;
     RECT  21.973 0.096 24.661 0.12 ;
     RECT  24.304 3.792 24.797 3.864 ;
     RECT  24.304 5.376 25.091 7.464 ;
     RECT  24.304 1.728 25.121 2.76 ;
     RECT  24.653 22.752 25.235 22.776 ;
     RECT  24.653 23.904 25.427 23.928 ;
     RECT  24.661 0.096 25.517 0.216 ;
     RECT  24.277 25.776 25.525 25.8 ;
     RECT  25.517 0.096 25.553 0.12 ;
     RECT  25.091 5.712 25.661 6.84 ;
     RECT  24.419 20.544 25.693 21.672 ;
     RECT  25.693 19.776 25.841 21.672 ;
     RECT  25.657 24.528 26.053 24.552 ;
     RECT  25.525 25.728 26.053 25.8 ;
     RECT  24.797 3.792 26.125 3.816 ;
     RECT  25.837 23.376 26.147 23.4 ;
     RECT  25.121 1.728 26.233 2.28 ;
     RECT  26.125 3.408 26.233 3.816 ;
     RECT  26.233 1.728 26.345 3.816 ;
     RECT  26.053 24.528 26.483 25.8 ;
     RECT  26.345 3.168 26.701 3.816 ;
     RECT  26.621 0.576 26.705 0.6 ;
     RECT  26.701 3.168 26.741 4.296 ;
     RECT  25.841 19.776 26.813 21.144 ;
     RECT  26.483 24.528 26.917 24.552 ;
     RECT  26.917 23.904 27.011 24.552 ;
     RECT  26.813 19.824 27.205 21.144 ;
     RECT  27.011 23.904 27.241 23.976 ;
     RECT  27.205 19.824 27.317 21.72 ;
     RECT  26.345 1.728 27.493 1.8 ;
     RECT  25.661 6.288 27.497 6.84 ;
     RECT  26.741 3.168 27.781 3.192 ;
     RECT  26.741 4.272 27.781 4.296 ;
     RECT  27.781 3.168 27.817 4.296 ;
     RECT  27.817 2.832 27.821 4.296 ;
     RECT  27.821 2.832 27.929 4.152 ;
     RECT  27.317 19.824 27.965 19.944 ;
     RECT  27.493 1.728 28.069 1.848 ;
     RECT  27.997 17.088 28.081 17.112 ;
     RECT  27.241 23.376 28.177 23.976 ;
     RECT  28.021 18.816 28.325 18.84 ;
     RECT  26.965 0.096 28.649 0.12 ;
     RECT  26.483 25.776 28.649 25.8 ;
     RECT  27.497 6.288 28.861 6.648 ;
     RECT  28.177 23.376 29.005 24.6 ;
     RECT  28.861 6.288 29.036 7.032 ;
     RECT  27.317 21.12 29.041 21.72 ;
     RECT  29.005 23.376 29.041 24.648 ;
     RECT  29.041 21.12 29.185 24.648 ;
     RECT  27.965 19.824 29.249 19.848 ;
     RECT  29.185 20.976 29.249 24.648 ;
     RECT  28.069 1.728 29.317 1.896 ;
     RECT  29.317 1.152 29.329 1.896 ;
     RECT  27.929 2.928 29.329 2.952 ;
     RECT  29.329 1.152 29.405 2.952 ;
     RECT  29.405 1.728 29.408 2.952 ;
     RECT  27.929 4.128 29.408 4.152 ;
     RECT  29.036 5.328 29.408 7.032 ;
     RECT  29.249 19.824 29.408 24.648 ;
     RECT  29.408 1.728 29.545 24.648 ;
     RECT  29.545 1.728 29.704 25.08 ;
     RECT  29.704 19.824 29.801 25.08 ;
     RECT  29.704 9.12 29.845 9.144 ;
     RECT  29.801 22.176 29.891 25.08 ;
     RECT  29.704 3.36 29.987 5.16 ;
     RECT  29.987 3.36 30.035 4.152 ;
     RECT  29.891 22.176 30.083 24.6 ;
     RECT  30.083 22.176 30.125 22.488 ;
     RECT  29.653 0.096 30.229 0.12 ;
     RECT  29.987 5.136 30.233 5.16 ;
     RECT  30.229 0.096 30.485 0.6 ;
     RECT  29.704 1.728 30.737 1.848 ;
     RECT  29.801 19.824 30.755 21.144 ;
     RECT  30.757 25.728 30.805 25.752 ;
     RECT  30.083 23.568 30.947 24.6 ;
     RECT  29.704 6.528 31.021 6.888 ;
     RECT  30.947 23.568 31.139 23.928 ;
     RECT  31.139 23.568 31.165 23.88 ;
     RECT  30.035 3.696 31.201 4.152 ;
     RECT  30.805 25.728 31.237 25.8 ;
     RECT  30.485 0.096 31.241 0.12 ;
     RECT  30.125 22.176 31.273 22.2 ;
     RECT  31.165 23.376 31.273 23.88 ;
     RECT  31.201 3.696 31.333 4.632 ;
     RECT  31.333 3.696 31.379 5.448 ;
     RECT  31.379 3.696 31.385 4.152 ;
     RECT  31.273 22.176 31.385 23.88 ;
     RECT  31.379 5.184 31.429 5.448 ;
     RECT  31.021 6.528 31.429 7.224 ;
     RECT  31.429 5.184 31.475 7.224 ;
     RECT  31.237 25.056 31.523 25.8 ;
     RECT  31.523 25.056 31.667 25.08 ;
     RECT  31.385 22.416 31.925 23.88 ;
     RECT  30.755 20.448 31.985 21.144 ;
     RECT  31.985 20.448 32.005 21.192 ;
     RECT  31.925 22.8 32.101 23.88 ;
     RECT  32.101 22.8 32.209 23.928 ;
     RECT  32.209 22.8 32.387 24.504 ;
     RECT  32.005 19.92 32.425 21.192 ;
     RECT  31.475 5.424 32.485 7.224 ;
     RECT  32.485 5.424 32.573 7.464 ;
     RECT  32.387 24.48 32.579 24.504 ;
     RECT  32.425 19.92 32.609 21.672 ;
     RECT  30.737 1.728 32.725 1.8 ;
     RECT  31.921 2.88 32.725 2.904 ;
     RECT  32.533 0.576 32.897 0.6 ;
     RECT  32.609 20.592 33.073 21.672 ;
     RECT  32.387 22.8 33.073 23.448 ;
     RECT  33.073 20.592 33.113 23.448 ;
     RECT  31.385 4.128 33.157 4.152 ;
     RECT  32.573 5.424 33.157 7.176 ;
     RECT  32.725 1.728 33.293 2.904 ;
     RECT  33.325 24.528 33.683 24.552 ;
     RECT  33.157 4.128 33.685 7.176 ;
     RECT  33.685 3.936 33.829 7.176 ;
     RECT  33.113 22.176 34.081 23.448 ;
     RECT  33.829 3.888 34.364 7.176 ;
     RECT  33.293 1.728 34.553 2.28 ;
     RECT  34.553 1.824 34.693 2.28 ;
     RECT  34.364 3.36 34.693 7.176 ;
     RECT  34.693 1.824 34.808 7.176 ;
     RECT  34.189 8.544 34.808 8.568 ;
     RECT  33.113 20.592 34.808 21.144 ;
     RECT  34.081 22.176 34.808 23.976 ;
     RECT  34.808 1.824 34.945 23.976 ;
     RECT  34.945 1.824 35.104 24.552 ;
     RECT  35.104 8.544 35.245 8.568 ;
     RECT  35.104 23.376 35.267 24.552 ;
     RECT  35.029 0.576 35.273 0.6 ;
     RECT  35.104 5.76 35.353 7.176 ;
     RECT  35.267 24.528 35.459 24.552 ;
     RECT  35.104 1.824 35.489 4.536 ;
     RECT  35.489 3.024 35.525 4.536 ;
     RECT  35.353 5.76 35.525 5.784 ;
     RECT  35.605 0.096 35.957 0.12 ;
     RECT  35.104 20.592 36.035 22.2 ;
     RECT  35.729 1.728 36.092 1.752 ;
     RECT  36.092 1.104 36.179 1.752 ;
     RECT  35.267 23.376 36.349 23.4 ;
     RECT  36.179 1.728 36.469 1.752 ;
     RECT  36.349 23.376 36.515 23.976 ;
     RECT  36.035 20.592 36.641 21.144 ;
     RECT  35.881 25.104 36.707 25.128 ;
     RECT  35.353 7.152 36.755 7.176 ;
     RECT  36.641 20.592 36.755 20.616 ;
     RECT  36.035 22.176 36.785 22.2 ;
     RECT  36.709 12.528 36.908 12.552 ;
     RECT  36.709 13.632 36.908 13.656 ;
     RECT  35.525 3.552 36.961 4.536 ;
     RECT  36.469 1.728 37.001 1.848 ;
     RECT  36.961 3.312 37.005 4.536 ;
     RECT  37.005 3.312 37.091 5.208 ;
     RECT  36.908 12.528 37.109 13.656 ;
     RECT  37.091 3.312 37.177 3.96 ;
     RECT  37.109 12.528 37.361 12.84 ;
     RECT  37.177 2.832 37.397 3.96 ;
     RECT  36.515 23.376 37.429 23.928 ;
     RECT  37.429 22.8 37.541 23.928 ;
     RECT  37.541 23.376 37.619 23.928 ;
     RECT  37.619 23.904 37.973 23.928 ;
     RECT  37.397 3.936 38.009 3.96 ;
     RECT  37.397 2.832 38.045 2.856 ;
     RECT  37.069 21.648 38.117 21.672 ;
     RECT  37.573 0.096 38.225 0.12 ;
     RECT  37.001 1.728 38.261 1.8 ;
     RECT  37.091 5.184 38.581 5.208 ;
     RECT  38.581 5.184 38.621 5.592 ;
     RECT  38.621 5.568 38.693 5.592 ;
     RECT  38.261 1.728 39.125 1.752 ;
     RECT  37.361 12.816 40.208 12.84 ;
     RECT  40.208 2.148 40.312 23.772 ;
     RECT  40.312 2.418 40.504 23.502 ;
     RECT  40.504 12.816 45.608 12.84 ;
     RECT  45.608 2.148 45.712 23.772 ;
     RECT  45.712 2.418 45.904 23.502 ;
     RECT  45.904 12.816 51.008 12.84 ;
     RECT  51.008 2.148 51.112 23.772 ;
     RECT  51.112 2.418 51.304 23.502 ;
     RECT  51.304 12.816 56.408 12.84 ;
     RECT  56.408 2.148 56.512 23.772 ;
     RECT  56.512 2.418 56.704 23.502 ;
     RECT  56.704 12.816 61.808 12.84 ;
     RECT  61.808 2.148 61.912 23.772 ;
     RECT  61.912 2.418 62.104 23.502 ;
     RECT  62.104 12.816 67.208 12.84 ;
     RECT  67.208 2.148 67.312 23.772 ;
     RECT  67.312 2.418 67.504 23.502 ;
     RECT  67.504 12.816 72.061 12.84 ;
     RECT  71.989 25.104 72.173 25.128 ;
     RECT  72.061 12.816 72.608 13.08 ;
     RECT  71.989 22.8 72.608 22.824 ;
     RECT  72.608 2.148 72.712 23.772 ;
     RECT  72.712 2.418 72.904 23.502 ;
     RECT  72.904 12.576 73.649 12.84 ;
     RECT  73.649 12.576 78.008 12.6 ;
     RECT  78.008 2.148 78.112 23.772 ;
     RECT  78.112 2.418 78.304 23.502 ;
     RECT  78.304 12.576 83.408 12.6 ;
     RECT  83.408 2.148 83.512 23.772 ;
     RECT  83.512 2.418 83.704 23.502 ;
     RECT  87.505 5.04 87.781 5.064 ;
     RECT  87.781 4.56 87.827 5.736 ;
     RECT  87.827 4.56 87.829 4.584 ;
     RECT  87.505 25.776 88.163 25.8 ;
     RECT  88.117 20.976 88.261 21 ;
     RECT  88.117 1.824 88.297 1.848 ;
     RECT  87.829 23.904 88.453 23.928 ;
     RECT  88.621 25.104 88.765 25.128 ;
     RECT  88.297 1.728 88.808 1.848 ;
     RECT  88.433 2.88 88.808 2.904 ;
     RECT  87.829 3.936 88.808 4.584 ;
     RECT  87.827 5.712 88.808 5.736 ;
     RECT  83.704 12.576 88.808 12.6 ;
     RECT  88.261 20.688 88.808 21 ;
     RECT  88.729 22.224 88.808 22.248 ;
     RECT  88.453 23.712 88.808 23.928 ;
     RECT  88.808 1.728 88.912 23.928 ;
     RECT  88.765 25.056 89.075 25.128 ;
     RECT  88.912 1.728 89.104 23.502 ;
     RECT  87.973 0.096 89.165 0.12 ;
     RECT  89.075 25.056 89.219 25.08 ;
     RECT  89.104 20.688 89.597 21.192 ;
     RECT  89.104 4.848 89.699 5.208 ;
     RECT  89.104 23.376 89.741 23.448 ;
     RECT  89.104 6.288 89.813 6.312 ;
     RECT  89.377 24.528 89.881 24.6 ;
     RECT  89.104 2.88 89.993 3.768 ;
     RECT  89.104 1.728 90.085 1.752 ;
     RECT  89.993 3.744 90.101 3.768 ;
     RECT  89.881 24.48 90.131 24.6 ;
     RECT  89.597 20.688 90.277 21.144 ;
     RECT  89.699 5.184 90.457 5.208 ;
     RECT  90.131 24.48 90.659 24.552 ;
     RECT  90.659 24.48 90.851 24.504 ;
     RECT  90.085 1.152 90.956 1.752 ;
     RECT  90.956 1.104 91.043 1.752 ;
     RECT  90.457 5.184 91.1 5.496 ;
     RECT  91.1 5.088 91.141 5.496 ;
     RECT  90.269 0.096 91.217 0.12 ;
     RECT  89.104 22.224 91.217 22.248 ;
     RECT  89.741 23.376 91.285 23.4 ;
     RECT  90.241 3.936 91.361 3.96 ;
     RECT  91.141 5.088 91.397 6.312 ;
     RECT  91.043 1.728 91.525 1.752 ;
     RECT  91.465 2.928 91.825 2.952 ;
     RECT  91.825 2.88 91.933 2.952 ;
     RECT  91.933 2.88 91.937 3.432 ;
     RECT  90.277 20.016 91.964 21.144 ;
     RECT  91.964 19.92 92.051 21.144 ;
     RECT  92.149 25.104 92.257 25.128 ;
     RECT  91.525 1.728 92.261 1.848 ;
     RECT  91.937 3.408 92.329 3.432 ;
     RECT  91.397 5.088 92.329 6.072 ;
     RECT  92.051 20.016 92.369 21.144 ;
     RECT  92.369 20.592 92.401 21.144 ;
     RECT  92.257 25.104 92.483 25.176 ;
     RECT  92.261 1.728 92.729 1.8 ;
     RECT  91.285 23.376 92.819 23.928 ;
     RECT  92.329 3.408 92.945 6.072 ;
     RECT  92.965 0.576 93.157 0.6 ;
     RECT  92.945 3.408 93.157 3.96 ;
     RECT  93.157 0.096 93.269 0.6 ;
     RECT  92.819 23.856 93.347 23.928 ;
     RECT  92.483 25.104 93.445 25.128 ;
     RECT  92.945 5.088 93.553 6.072 ;
     RECT  93.269 0.096 93.686 0.168 ;
     RECT  92.729 1.728 93.829 1.752 ;
     RECT  93.157 2.88 94.021 3.96 ;
     RECT  93.553 5.088 94.021 6.312 ;
     RECT  93.788 23.376 94.021 23.772 ;
     RECT  94.021 2.88 94.069 6.312 ;
     RECT  93.445 25.056 94.069 25.128 ;
     RECT  93.829 1.728 94.208 1.8 ;
     RECT  94.069 2.88 94.208 6.36 ;
     RECT  89.104 12.576 94.208 12.6 ;
     RECT  92.401 20.592 94.208 21.528 ;
     RECT  94.021 22.512 94.208 23.772 ;
     RECT  94.069 25.056 94.259 25.752 ;
     RECT  94.208 1.728 94.405 23.772 ;
     RECT  94.405 1.728 94.504 23.928 ;
     RECT  94.504 3.696 94.601 3.96 ;
     RECT  94.504 22.752 94.633 23.928 ;
     RECT  94.259 25.056 94.633 25.128 ;
     RECT  94.504 5.04 94.673 6.936 ;
     RECT  94.504 20.208 94.691 21.672 ;
     RECT  94.633 22.752 94.787 25.128 ;
     RECT  93.686 0.096 95.125 0.12 ;
     RECT  94.787 22.752 95.171 24.552 ;
     RECT  94.691 20.592 95.569 21.672 ;
     RECT  95.171 22.752 95.569 23.976 ;
     RECT  94.601 3.696 95.573 3.72 ;
     RECT  95.569 20.592 95.609 23.976 ;
     RECT  94.504 1.728 95.612 1.8 ;
     RECT  95.125 0.096 95.753 0.168 ;
     RECT  94.673 5.664 95.795 6.936 ;
     RECT  95.612 1.728 95.857 2.28 ;
     RECT  95.795 5.664 95.996 6.552 ;
     RECT  95.753 0.144 96.041 0.168 ;
     RECT  95.996 5.616 96.085 6.552 ;
     RECT  95.857 1.728 96.113 2.952 ;
     RECT  95.609 22.464 96.289 23.976 ;
     RECT  96.289 22.464 96.419 24.552 ;
     RECT  96.113 1.728 96.581 2.328 ;
     RECT  95.609 20.592 96.62 21.144 ;
     RECT  96.085 5.088 96.689 6.552 ;
     RECT  96.62 19.68 96.707 21.144 ;
     RECT  96.419 22.464 97.139 23.976 ;
     RECT  96.649 3.744 97.585 3.768 ;
     RECT  96.689 5.088 97.585 5.112 ;
     RECT  97.139 22.464 97.693 23.4 ;
     RECT  97.585 3.744 97.717 5.112 ;
     RECT  96.707 20.544 97.717 21.144 ;
     RECT  97.693 22.176 97.733 23.4 ;
     RECT  96.893 0.096 97.763 0.12 ;
     RECT  97.717 3.744 97.765 5.16 ;
     RECT  97.765 2.976 97.769 5.16 ;
     RECT  97.717 20.208 97.804 21.144 ;
     RECT  97.769 4.944 97.805 5.16 ;
     RECT  97.769 2.976 97.813 3.96 ;
     RECT  97.813 2.88 97.985 3.96 ;
     RECT  97.901 8.544 97.985 8.568 ;
     RECT  96.581 1.728 98.149 1.848 ;
     RECT  98.233 9.12 98.317 9.144 ;
     RECT  97.733 23.376 98.387 23.4 ;
     RECT  97.805 4.944 98.453 5.112 ;
     RECT  97.657 25.104 98.513 25.128 ;
     RECT  97.804 20.592 98.521 21.144 ;
     RECT  97.733 22.176 98.521 22.2 ;
     RECT  98.513 25.104 98.597 25.8 ;
     RECT  98.597 25.104 98.723 25.128 ;
     RECT  97.985 3.84 98.845 3.96 ;
     RECT  98.453 4.944 98.845 5.064 ;
     RECT  98.677 0.576 98.869 0.6 ;
     RECT  98.521 20.592 98.917 22.2 ;
     RECT  98.869 0.096 98.957 0.6 ;
     RECT  98.149 1.728 99.385 2.328 ;
     RECT  98.845 3.84 99.385 5.064 ;
     RECT  99.313 9.12 99.385 9.144 ;
     RECT  98.869 23.904 99.397 23.928 ;
     RECT  99.397 23.856 99.493 23.928 ;
     RECT  99.493 23.664 99.565 23.928 ;
     RECT  99.385 1.728 99.608 5.064 ;
     RECT  96.689 6.144 99.608 6.552 ;
     RECT  99.385 8.544 99.608 9.144 ;
     RECT  94.504 12.576 99.608 12.6 ;
     RECT  98.917 19.872 99.608 22.2 ;
     RECT  99.565 23.664 99.608 24.552 ;
     RECT  99.608 1.728 99.827 24.552 ;
     RECT  99.827 1.728 99.904 23.976 ;
     RECT  99.904 19.872 100.037 22.152 ;
     RECT  98.957 0.096 100.076 0.12 ;
     RECT  100.076 0.096 100.163 0.552 ;
     RECT  100.277 25.776 100.361 25.8 ;
     RECT  99.904 23.376 100.691 23.976 ;
     RECT  99.904 1.728 100.757 6.888 ;
     RECT  100.757 1.728 100.901 6.504 ;
     RECT  100.037 20.448 100.973 22.152 ;
     RECT  100.901 2.88 101.027 6.504 ;
     RECT  100.825 25.104 101.075 25.128 ;
     RECT  101.027 2.88 101.081 6.168 ;
     RECT  101.221 8.544 101.477 8.568 ;
     RECT  100.973 20.592 102.161 22.152 ;
     RECT  102.161 20.592 102.337 21.24 ;
     RECT  100.691 23.376 102.337 23.928 ;
     RECT  101.081 2.88 102.409 2.904 ;
     RECT  101.081 3.888 102.409 6.168 ;
     RECT  100.901 1.728 102.469 1.752 ;
     RECT  102.409 2.88 102.469 6.168 ;
     RECT  102.337 20.544 102.565 21.24 ;
     RECT  102.337 23.376 102.985 24.552 ;
     RECT  102.985 23.376 103.043 25.128 ;
     RECT  102.469 1.728 103.139 6.168 ;
     RECT  103.139 1.728 103.169 2.28 ;
     RECT  103.139 3.408 103.169 6.168 ;
     RECT  103.169 3.408 103.177 6.072 ;
     RECT  103.177 3.552 103.205 6.072 ;
     RECT  102.565 19.92 103.237 21.24 ;
     RECT  103.205 4.56 103.673 6.072 ;
     RECT  100.163 0.096 103.717 0.12 ;
     RECT  103.043 23.808 103.763 25.128 ;
     RECT  103.717 0.096 103.957 0.216 ;
     RECT  103.237 19.92 103.993 21.384 ;
     RECT  103.763 23.808 104.053 24.552 ;
     RECT  103.957 0.096 104.099 0.552 ;
     RECT  103.205 3.552 104.245 3.576 ;
     RECT  103.673 5.184 104.281 6.072 ;
     RECT  103.169 1.728 104.437 1.8 ;
     RECT  104.053 23.376 104.483 24.552 ;
     RECT  104.245 3.552 104.629 3.96 ;
     RECT  104.281 5.184 104.713 6.84 ;
     RECT  103.993 19.92 104.785 22.344 ;
     RECT  104.629 3.408 104.849 3.96 ;
     RECT  104.785 19.536 104.869 22.344 ;
     RECT  104.483 23.376 104.869 23.928 ;
     RECT  104.437 1.728 104.929 2.328 ;
     RECT  104.849 3.408 104.929 4.008 ;
     RECT  104.929 1.728 105.008 4.008 ;
     RECT  104.713 5.136 105.008 6.84 ;
     RECT  104.497 7.968 105.008 7.992 ;
     RECT  99.904 12.576 105.008 12.6 ;
     RECT  104.869 19.536 105.008 23.928 ;
     RECT  104.821 25.104 105.011 25.128 ;
     RECT  105.008 1.728 105.304 23.928 ;
     RECT  105.304 17.088 105.365 17.112 ;
     RECT  104.099 0.096 105.395 0.12 ;
     RECT  105.304 1.728 105.443 6.84 ;
     RECT  105.304 20.592 105.443 22.344 ;
     RECT  105.443 3.408 106.049 6.84 ;
     RECT  106.028 0.528 106.115 0.552 ;
     RECT  105.443 1.728 106.121 2.184 ;
     RECT  105.304 23.376 106.451 23.928 ;
     RECT  105.443 20.592 106.481 21.96 ;
     RECT  106.049 3.408 106.517 6.744 ;
     RECT  106.121 1.728 106.585 1.752 ;
     RECT  106.213 25.728 106.585 25.752 ;
     RECT  105.304 19.536 106.625 19.56 ;
     RECT  106.585 1.68 106.669 1.752 ;
     RECT  106.585 25.056 106.669 25.752 ;
     RECT  106.585 3.072 106.697 3.096 ;
     RECT  105.304 12.576 107.129 12.6 ;
     RECT  106.517 4.224 107.201 6.744 ;
     RECT  106.451 23.376 107.233 23.448 ;
     RECT  106.669 1.728 107.317 1.752 ;
     RECT  107.233 23.232 107.42 23.448 ;
     RECT  107.42 23.232 107.489 23.496 ;
     RECT  107.413 11.904 107.497 12.024 ;
     RECT  107.317 1.728 107.525 2.328 ;
     RECT  107.497 12 107.533 12.024 ;
     RECT  107.201 4.224 107.557 6.312 ;
     RECT  106.481 20.592 107.557 21.144 ;
     RECT  107.557 20.592 107.665 21.528 ;
     RECT  106.933 25.776 107.705 25.8 ;
     RECT  108.133 7.44 108.323 7.464 ;
     RECT  108.241 24.48 108.419 24.504 ;
     RECT  107.489 23.376 108.457 23.496 ;
     RECT  107.665 20.304 108.637 21.528 ;
     RECT  108.637 20.304 108.641 21.672 ;
     RECT  107.557 3.84 108.853 6.312 ;
     RECT  108.853 3.84 109.109 6.936 ;
     RECT  109.109 3.84 109.289 6.888 ;
     RECT  108.641 20.4 109.397 21.672 ;
     RECT  108.457 23.376 109.573 23.928 ;
     RECT  108.889 25.056 109.573 25.08 ;
     RECT  106.741 0.096 109.58 0.12 ;
     RECT  109.58 0.096 109.667 0.552 ;
     RECT  109.573 22.656 109.667 25.08 ;
     RECT  109.667 0.096 109.793 0.12 ;
     RECT  107.525 1.728 109.897 2.184 ;
     RECT  109.667 22.656 110.051 24.552 ;
     RECT  109.897 1.728 110.149 2.856 ;
     RECT  109.289 3.84 110.149 3.96 ;
     RECT  110.149 1.728 110.408 3.96 ;
     RECT  109.289 5.04 110.408 6.888 ;
     RECT  110.185 8.544 110.408 8.568 ;
     RECT  109.397 20.4 110.408 20.712 ;
     RECT  110.051 22.656 110.408 24.504 ;
     RECT  110.408 1.728 110.579 24.504 ;
     RECT  110.579 1.728 110.704 23.502 ;
     RECT  110.579 24.48 110.771 24.504 ;
     RECT  110.704 5.04 110.801 6.552 ;
     RECT  110.725 0.144 110.869 0.168 ;
     RECT  110.869 0.096 110.981 0.168 ;
     RECT  110.704 19.92 111.233 21.144 ;
     RECT  110.801 5.04 111.377 5.352 ;
     RECT  111.233 19.92 111.521 20.856 ;
     RECT  110.704 23.376 111.589 23.502 ;
     RECT  110.981 0.096 111.593 0.12 ;
     RECT  110.704 1.728 111.781 1.848 ;
     RECT  111.377 5.136 111.829 5.352 ;
     RECT  110.801 6.528 111.829 6.552 ;
     RECT  111.761 25.776 111.845 25.8 ;
     RECT  111.805 22.128 111.877 22.152 ;
     RECT  111.589 23.376 112.019 23.928 ;
     RECT  111.781 1.152 112.133 1.848 ;
     RECT  112.021 25.104 112.355 25.128 ;
     RECT  111.521 20.16 112.417 20.856 ;
     RECT  111.829 5.136 112.453 6.552 ;
     RECT  111.877 22.128 112.637 22.2 ;
     RECT  112.019 23.376 112.739 23.496 ;
     RECT  112.453 5.088 112.925 6.552 ;
     RECT  112.637 22.128 112.925 22.152 ;
     RECT  112.705 24.528 112.931 24.552 ;
     RECT  110.704 3.84 113.101 3.864 ;
     RECT  113.029 9.696 113.113 9.72 ;
     RECT  112.925 5.136 113.461 6.552 ;
     RECT  113.461 8.544 113.545 8.568 ;
     RECT  113.461 5.136 113.603 6.84 ;
     RECT  112.993 23.856 113.795 23.928 ;
     RECT  112.133 1.728 113.821 1.848 ;
     RECT  113.101 3.84 113.965 3.96 ;
     RECT  113.603 5.136 113.965 6.552 ;
     RECT  112.417 20.16 113.965 21.144 ;
     RECT  113.929 24.528 113.965 24.552 ;
     RECT  113.209 25.776 113.965 25.8 ;
     RECT  113.821 1.728 113.987 2.28 ;
     RECT  113.965 24.528 113.987 25.8 ;
     RECT  113.965 3.84 114.077 6.552 ;
     RECT  113.987 24.528 114.179 25.08 ;
     RECT  113.987 1.728 114.325 1.8 ;
     RECT  114.325 1.104 114.515 1.8 ;
     RECT  113.965 20.064 114.613 21.672 ;
     RECT  114.077 4.56 114.689 6.552 ;
     RECT  114.179 24.528 114.899 24.6 ;
     RECT  114.428 23.376 114.997 23.4 ;
     RECT  114.899 24.528 114.997 24.552 ;
     RECT  114.689 4.56 115.117 4.584 ;
     RECT  114.997 23.376 115.235 24.552 ;
     RECT  115.117 3.936 115.253 4.584 ;
     RECT  112.885 0.096 115.381 0.12 ;
     RECT  114.613 20.064 115.549 22.296 ;
     RECT  115.235 23.376 115.549 23.976 ;
     RECT  114.515 1.728 115.621 1.8 ;
     RECT  115.225 2.832 115.621 2.856 ;
     RECT  114.689 5.568 115.693 6.552 ;
     RECT  115.381 0.096 115.805 0.6 ;
     RECT  115.549 20.064 115.805 23.976 ;
     RECT  115.621 1.728 115.808 2.856 ;
     RECT  115.253 3.888 115.808 4.584 ;
     RECT  115.693 5.568 115.808 6.648 ;
     RECT  115.285 8.544 115.808 8.568 ;
     RECT  115.805 20.064 115.808 23.928 ;
     RECT  115.808 1.728 116.104 23.928 ;
     RECT  116.104 23.376 116.165 23.928 ;
     RECT  116.104 1.728 116.243 3.96 ;
     RECT  116.104 7.968 116.243 7.992 ;
     RECT  116.243 1.728 116.273 2.616 ;
     RECT  116.104 20.592 117.205 20.952 ;
     RECT  116.104 22.176 117.205 22.2 ;
     RECT  116.104 5.568 117.241 6.744 ;
     RECT  116.243 3.792 117.26 3.96 ;
     RECT  117.241 5.136 117.26 6.888 ;
     RECT  117.205 20.592 117.281 22.2 ;
     RECT  117.26 3.792 117.325 6.888 ;
     RECT  116.273 1.728 117.457 1.848 ;
     RECT  117.457 1.728 117.529 2.808 ;
     RECT  117.325 3.792 117.529 6.264 ;
     RECT  116.165 23.376 117.685 23.448 ;
     RECT  117.685 23.376 117.889 23.928 ;
     RECT  117.529 1.728 117.971 6.264 ;
     RECT  117.281 20.592 118.037 21.432 ;
     RECT  117.889 23.376 118.115 24.6 ;
     RECT  117.971 5.136 118.145 6.264 ;
     RECT  117.971 1.728 118.397 3.96 ;
     RECT  118.397 1.728 118.451 3.816 ;
     RECT  115.805 0.096 118.981 0.12 ;
     RECT  118.94 17.472 119.027 17.496 ;
     RECT  118.981 18.816 119.18 18.84 ;
     RECT  119.041 19.872 119.213 19.896 ;
     RECT  118.037 20.928 119.213 21.432 ;
     RECT  119.18 18.192 119.324 18.84 ;
     RECT  119.213 19.872 119.324 21.432 ;
     RECT  118.451 2.784 119.477 3.816 ;
     RECT  118.145 5.184 119.477 6.264 ;
     RECT  118.451 1.728 119.509 1.8 ;
     RECT  119.477 2.784 119.509 2.808 ;
     RECT  119.324 18.192 119.509 21.432 ;
     RECT  119.509 18.192 119.555 21.672 ;
     RECT  118.115 23.376 119.555 24.552 ;
     RECT  119.555 23.904 119.617 24.552 ;
     RECT  118.981 0.096 119.765 0.168 ;
     RECT  119.555 19.872 119.837 21.672 ;
     RECT  119.765 0.144 119.873 0.168 ;
     RECT  119.041 25.776 119.909 25.8 ;
     RECT  119.509 1.728 119.941 2.808 ;
     RECT  119.555 18.192 119.989 18.216 ;
     RECT  119.837 19.872 120.017 21.144 ;
     RECT  119.941 1.104 120.275 2.808 ;
     RECT  119.617 23.904 120.275 24.6 ;
     RECT  120.275 23.904 120.419 24.552 ;
     RECT  120.419 23.904 120.611 23.928 ;
     RECT  120.275 1.728 120.661 2.808 ;
     RECT  119.477 3.792 120.661 3.816 ;
     RECT  120.017 19.872 121.004 19.896 ;
     RECT  120.017 20.928 121.004 21.144 ;
     RECT  120.661 1.728 121.208 3.96 ;
     RECT  119.477 5.184 121.208 6.12 ;
     RECT  120.997 9.12 121.208 9.144 ;
     RECT  121.004 19.872 121.208 21.144 ;
     RECT  121.093 22.224 121.208 22.248 ;
     RECT  120.697 23.376 121.208 23.772 ;
     RECT  121.045 25.728 121.477 25.752 ;
     RECT  121.208 1.728 121.504 23.772 ;
     RECT  121.504 19.872 121.565 21.144 ;
     RECT  121.565 19.872 121.601 20.952 ;
     RECT  121.477 25.728 121.619 25.8 ;
     RECT  121.504 22.128 121.633 23.772 ;
     RECT  121.633 22.128 121.634 23.928 ;
     RECT  121.634 22.176 121.717 23.928 ;
     RECT  121.717 22.8 121.777 23.928 ;
     RECT  121.777 22.8 121.781 24.552 ;
     RECT  121.504 1.728 121.889 6.12 ;
     RECT  121.781 23.376 122.051 24.552 ;
     RECT  121.889 1.728 122.213 4.68 ;
     RECT  121.601 19.872 122.321 20.856 ;
     RECT  121.619 25.728 122.435 25.752 ;
     RECT  122.213 3.84 122.537 4.68 ;
     RECT  122.321 20.016 122.636 20.856 ;
     RECT  122.537 3.84 122.717 3.96 ;
     RECT  122.636 20.016 122.723 21.624 ;
     RECT  121.093 0.096 122.861 0.12 ;
     RECT  122.213 1.728 122.963 2.712 ;
     RECT  121.889 6 123.061 6.12 ;
     RECT  122.717 3.936 123.107 3.96 ;
     RECT  122.051 23.376 123.181 24.024 ;
     RECT  123.061 5.136 123.325 6.12 ;
     RECT  123.325 5.136 123.649 6.552 ;
     RECT  122.963 1.728 123.653 1.848 ;
     RECT  123.181 22.704 124.019 24.024 ;
     RECT  124.019 22.704 124.049 23.448 ;
     RECT  124.049 23.376 124.265 23.448 ;
     RECT  123.253 2.88 124.301 2.904 ;
     RECT  123.649 5.136 124.409 6.84 ;
     RECT  124.409 5.136 124.445 6.552 ;
     RECT  122.723 20.016 124.585 21.144 ;
     RECT  124.405 4.128 124.873 4.152 ;
     RECT  124.445 5.136 124.873 6.312 ;
     RECT  124.873 4.128 124.877 6.312 ;
     RECT  124.585 20.016 124.877 22.056 ;
     RECT  124.153 24.528 124.931 24.6 ;
     RECT  123.653 1.728 125.077 1.8 ;
     RECT  124.877 20.016 125.089 20.856 ;
     RECT  125.18 25.056 125.306 25.128 ;
     RECT  125.089 19.872 125.365 20.856 ;
     RECT  125.306 25.056 125.459 25.08 ;
     RECT  124.877 4.896 125.485 6.312 ;
     RECT  124.265 23.376 125.585 23.4 ;
     RECT  125.585 23.376 125.669 23.928 ;
     RECT  125.917 3.648 125.941 3.672 ;
     RECT  125.485 4.896 125.941 6.84 ;
     RECT  125.941 3.648 126.313 6.84 ;
     RECT  125.365 18.96 126.325 20.856 ;
     RECT  126.313 3.12 126.469 6.84 ;
     RECT  125.077 1.728 126.608 1.848 ;
     RECT  126.469 2.88 126.608 6.84 ;
     RECT  126.325 18.96 126.608 21 ;
     RECT  124.877 22.032 126.608 22.056 ;
     RECT  125.669 23.376 126.608 23.772 ;
     RECT  126.608 1.728 126.661 23.772 ;
     RECT  126.661 1.728 126.904 23.928 ;
     RECT  126.904 23.376 126.997 23.928 ;
     RECT  126.904 1.728 127.091 6.84 ;
     RECT  127.091 4.416 127.132 6.84 ;
     RECT  127.132 4.512 127.181 6.84 ;
     RECT  127.189 25.776 127.331 25.8 ;
     RECT  126.904 18.96 127.333 22.056 ;
     RECT  126.997 23.376 127.619 24.552 ;
     RECT  127.333 18.96 127.667 20.952 ;
     RECT  127.091 1.728 127.721 2.904 ;
     RECT  127.765 25.008 127.955 25.128 ;
     RECT  127.181 4.512 128.113 6.168 ;
     RECT  127.333 21.936 128.329 22.056 ;
     RECT  127.619 23.376 128.329 23.976 ;
     RECT  128.329 21.936 128.339 23.976 ;
     RECT  128.329 9.696 128.389 9.72 ;
     RECT  128.389 9.12 128.413 9.72 ;
     RECT  123.973 0.096 128.441 0.12 ;
     RECT  128.339 21.936 128.441 23.928 ;
     RECT  128.413 9.12 128.477 9.144 ;
     RECT  128.113 3.312 128.585 6.168 ;
     RECT  127.667 20.496 128.617 20.952 ;
     RECT  128.441 21.936 128.617 22.056 ;
     RECT  128.617 20.496 128.729 22.056 ;
     RECT  127.667 18.96 128.761 18.984 ;
     RECT  128.729 20.496 128.761 21.96 ;
     RECT  127.721 1.728 128.789 2.184 ;
     RECT  128.789 1.728 128.873 2.328 ;
     RECT  128.761 18.96 128.945 21.96 ;
     RECT  128.585 4.272 129.157 6.168 ;
     RECT  129.157 4.272 129.225 6.312 ;
     RECT  128.873 1.728 129.395 2.28 ;
     RECT  128.761 25.776 129.779 25.8 ;
     RECT  128.945 18.96 129.809 21.672 ;
     RECT  129.809 21.648 130.025 21.672 ;
     RECT  129.395 1.728 130.061 2.184 ;
     RECT  129.225 4.272 130.237 5.112 ;
     RECT  129.225 6.144 130.237 6.312 ;
     RECT  130.237 3.696 130.597 5.112 ;
     RECT  130.237 6.144 130.597 6.84 ;
     RECT  130.597 3.696 130.643 6.84 ;
     RECT  129.809 18.96 130.745 20.616 ;
     RECT  128.441 23.376 130.853 23.928 ;
     RECT  130.949 25.776 131.029 25.8 ;
     RECT  131.029 25.056 131.033 25.8 ;
     RECT  131.033 25.056 131.065 25.752 ;
     RECT  131.065 24.96 131.245 25.752 ;
     RECT  130.643 3.696 131.281 4.536 ;
     RECT  130.061 1.728 131.509 1.8 ;
     RECT  131.281 2.832 131.509 4.536 ;
     RECT  130.745 20.544 131.653 20.616 ;
     RECT  129.541 0.096 131.753 0.12 ;
     RECT  131.749 8.544 131.821 8.568 ;
     RECT  130.745 18.96 131.893 19.368 ;
     RECT  131.653 20.544 131.893 20.664 ;
     RECT  131.845 21.792 131.893 21.816 ;
     RECT  131.245 24.48 131.939 25.752 ;
     RECT  131.893 18.96 131.965 21.816 ;
     RECT  131.509 1.728 132.008 4.536 ;
     RECT  130.643 5.712 132.008 6.84 ;
     RECT  131.821 8.544 132.008 8.664 ;
     RECT  131.165 9.696 132.008 9.72 ;
     RECT  131.965 18.96 132.008 22.056 ;
     RECT  130.853 23.376 132.008 23.4 ;
     RECT  132.008 1.728 132.112 23.772 ;
     RECT  132.112 1.728 132.304 23.502 ;
     RECT  132.304 3.984 132.419 6.888 ;
     RECT  132.304 20.16 132.509 22.056 ;
     RECT  132.509 20.64 132.617 22.056 ;
     RECT  132.419 5.472 132.653 6.888 ;
     RECT  132.304 1.728 132.905 2.28 ;
     RECT  131.939 25.056 132.949 25.752 ;
     RECT  132.617 21.552 133.049 22.056 ;
     RECT  132.229 0.144 133.141 0.168 ;
     RECT  132.949 25.056 133.157 25.8 ;
     RECT  132.304 23.376 133.187 23.502 ;
     RECT  133.141 0.096 133.193 0.168 ;
     RECT  133.441 2.88 133.477 2.904 ;
     RECT  132.419 3.984 133.477 4.44 ;
     RECT  133.477 2.88 133.484 4.44 ;
     RECT  132.653 5.472 133.484 6.84 ;
     RECT  133.484 2.88 133.741 6.84 ;
     RECT  133.253 23.904 133.837 23.928 ;
     RECT  133.157 25.056 133.837 25.128 ;
     RECT  133.837 23.904 134.051 25.128 ;
     RECT  133.741 3.696 134.161 6.84 ;
     RECT  134.051 25.104 134.189 25.128 ;
     RECT  134.161 3.696 134.245 6.888 ;
     RECT  134.189 25.104 134.273 25.8 ;
     RECT  133.693 20.16 134.305 20.184 ;
     RECT  133.049 21.552 134.305 21.912 ;
     RECT  134.305 20.16 134.345 21.912 ;
     RECT  134.273 25.104 134.435 25.752 ;
     RECT  133.193 0.096 134.581 0.12 ;
     RECT  134.051 23.904 134.629 23.976 ;
     RECT  134.345 20.16 134.773 21.672 ;
     RECT  134.581 0.096 134.957 0.168 ;
     RECT  134.629 23.376 134.963 23.976 ;
     RECT  134.435 25.632 135.173 25.752 ;
     RECT  132.304 18.96 135.205 18.984 ;
     RECT  134.773 20.016 135.205 21.672 ;
     RECT  135.205 18.96 135.217 21.672 ;
     RECT  135.217 18.96 135.245 21.576 ;
     RECT  135.205 12 135.289 12.024 ;
     RECT  132.905 1.728 135.301 1.752 ;
     RECT  134.245 3.696 135.301 6.84 ;
     RECT  135.301 1.728 135.445 1.8 ;
     RECT  134.963 23.376 135.457 23.928 ;
     RECT  135.457 22.704 135.491 23.928 ;
     RECT  135.301 3.696 135.565 7.752 ;
     RECT  135.245 18.96 135.587 20.472 ;
     RECT  135.173 25.728 135.637 25.752 ;
     RECT  135.565 2.832 135.649 7.752 ;
     RECT  135.491 22.704 135.785 22.728 ;
     RECT  135.587 18.96 135.857 19.416 ;
     RECT  135.853 22.656 136.145 22.68 ;
     RECT  134.957 0.096 136.165 0.12 ;
     RECT  135.637 25.728 136.211 25.8 ;
     RECT  135.245 21.552 136.213 21.576 ;
     RECT  135.649 3.696 136.259 7.752 ;
     RECT  135.445 1.728 136.549 1.848 ;
     RECT  136.211 25.776 136.613 25.8 ;
     RECT  136.213 21.504 136.717 21.576 ;
     RECT  136.549 1.728 136.757 2.232 ;
     RECT  136.757 1.824 136.793 2.232 ;
     RECT  135.491 23.904 136.825 23.928 ;
     RECT  136.259 5.136 136.885 7.752 ;
     RECT  135.587 20.448 136.885 20.472 ;
     RECT  136.717 21.504 136.885 21.96 ;
     RECT  135.857 18.96 136.933 19.224 ;
     RECT  136.885 20.448 136.933 21.96 ;
     RECT  136.793 2.148 137.077 2.232 ;
     RECT  136.259 3.696 137.077 4.152 ;
     RECT  136.933 18.768 137.257 21.96 ;
     RECT  136.165 0.096 137.365 0.216 ;
     RECT  137.077 2.148 137.401 4.152 ;
     RECT  136.885 5.136 137.401 8.568 ;
     RECT  137.401 2.148 137.408 8.568 ;
     RECT  137.257 18.768 137.408 22.776 ;
     RECT  136.825 23.904 137.408 24.6 ;
     RECT  137.365 0.096 137.459 0.552 ;
     RECT  137.408 2.148 137.459 24.6 ;
     RECT  137.459 2.148 137.704 23.928 ;
     RECT  137.704 18.048 137.881 23.928 ;
     RECT  137.881 18.192 138.017 23.928 ;
     RECT  137.941 25.056 138.161 25.128 ;
     RECT  138.161 25.104 138.179 25.128 ;
     RECT  137.704 11.424 138.277 11.448 ;
     RECT  138.017 18.192 138.665 22.824 ;
     RECT  138.665 18.192 138.673 21.096 ;
     RECT  137.459 0.096 138.701 0.168 ;
     RECT  138.017 23.904 138.781 23.928 ;
     RECT  138.673 18.192 138.803 20.568 ;
     RECT  137.704 2.832 138.877 9.144 ;
     RECT  138.665 22.176 138.995 22.824 ;
     RECT  138.803 18.672 138.997 20.568 ;
     RECT  138.517 25.776 139.133 25.8 ;
     RECT  139.189 25.728 139.427 25.752 ;
     RECT  139.309 17.088 139.525 17.112 ;
     RECT  137.797 1.728 139.573 1.8 ;
     RECT  138.877 2.832 139.573 9.24 ;
     RECT  139.129 10.848 139.597 10.872 ;
     RECT  139.597 10.848 139.681 11.448 ;
     RECT  138.997 18.768 139.705 20.568 ;
     RECT  138.995 22.176 139.705 22.296 ;
     RECT  139.453 25.152 139.724 25.176 ;
     RECT  139.705 18.768 139.745 22.296 ;
     RECT  139.237 0.528 139.765 0.6 ;
     RECT  139.681 10.848 139.861 10.872 ;
     RECT  139.525 17.088 139.957 17.592 ;
     RECT  139.861 10.32 139.961 10.872 ;
     RECT  139.196 23.376 140.003 23.4 ;
     RECT  139.573 1.728 140.029 9.24 ;
     RECT  139.961 10.8 140.105 10.872 ;
     RECT  140.273 23.904 140.357 23.928 ;
     RECT  140.348 11.952 140.435 11.976 ;
     RECT  139.724 25.104 140.453 25.176 ;
     RECT  139.765 0.096 140.461 0.6 ;
     RECT  140.029 1.728 140.501 9.72 ;
     RECT  139.957 16.512 140.789 17.592 ;
     RECT  139.745 18.96 140.821 22.296 ;
     RECT  140.821 18.912 140.825 22.296 ;
     RECT  140.825 18.912 140.929 22.2 ;
     RECT  140.501 2.736 141.041 9.72 ;
     RECT  140.789 16.512 141.077 17.112 ;
     RECT  141.077 17.088 141.107 17.112 ;
     RECT  141.041 2.736 141.113 7.08 ;
     RECT  140.929 18.672 141.113 22.2 ;
     RECT  141.041 8.544 141.173 9.72 ;
     RECT  140.105 10.848 141.173 10.872 ;
     RECT  141.113 18.672 141.251 20.52 ;
     RECT  141.113 22.176 141.257 22.2 ;
     RECT  141.173 8.544 141.289 10.872 ;
     RECT  141.251 18.672 141.293 19.848 ;
     RECT  141.289 8.544 141.301 11.448 ;
     RECT  141.301 9.12 141.329 11.448 ;
     RECT  141.113 2.736 141.347 6.936 ;
     RECT  141.347 6.24 141.365 6.936 ;
     RECT  141.329 9.696 141.373 11.448 ;
     RECT  141.347 2.736 141.491 5.112 ;
     RECT  141.491 5.088 141.539 5.112 ;
     RECT  141.491 2.736 141.545 3.336 ;
     RECT  141.293 18.672 141.545 19.752 ;
     RECT  141.365 6.24 141.581 6.264 ;
     RECT  141.373 9.696 141.581 10.824 ;
     RECT  141.545 19.728 141.581 19.752 ;
     RECT  141.545 2.736 141.731 2.856 ;
     RECT  141.581 9.696 141.761 10.296 ;
     RECT  140.453 25.104 141.779 25.8 ;
     RECT  141.731 2.736 141.827 2.76 ;
     RECT  141.761 10.272 141.841 10.296 ;
     RECT  141.545 18.672 141.905 18.696 ;
     RECT  141.397 23.376 141.937 23.4 ;
     RECT  140.501 1.728 142.163 1.752 ;
     RECT  141.937 22.8 142.163 23.4 ;
     RECT  140.461 0.048 142.261 0.6 ;
     RECT  142.163 23.376 142.499 23.4 ;
     RECT  142.261 0.048 142.705 1.176 ;
     RECT  141.779 25.776 142.873 25.8 ;
     RECT  142.705 0.048 143.065 0.6 ;
     RECT  142.873 25.152 143.593 25.8 ;
     RECT  143.065 0.048 143.843 0.552 ;
     RECT  143.593 25.104 143.939 25.8 ;
     RECT  143.843 0.096 144.131 0.552 ;
     RECT  144.131 0.096 144.275 0.12 ;
     RECT  143.939 25.776 144.281 25.8 ;
    LAYER M5 ;
     RECT  88.128 0.016 144.264 0.131 ;
     RECT  88.128 0.131 144.12 0.563 ;
     RECT  88.128 0.563 143.016 0.611 ;
     RECT  88.128 0.611 142.68 1.187 ;
     RECT  1.008 0.016 37.944 1.763 ;
     RECT  88.128 1.187 142.152 1.763 ;
     RECT  1.344 1.763 5.832 1.811 ;
     RECT  6.912 1.763 8.904 1.811 ;
     RECT  9.936 1.763 20.568 1.811 ;
     RECT  22.512 1.763 24.312 1.811 ;
     RECT  25.392 1.763 28.248 1.811 ;
     RECT  29.4 1.763 35.448 1.811 ;
     RECT  36.48 1.763 37.416 1.811 ;
     RECT  91.536 1.763 92.472 1.811 ;
     RECT  93.84 1.763 101.4 1.811 ;
     RECT  102.48 1.763 103.416 1.811 ;
     RECT  104.448 1.763 111.48 1.811 ;
     RECT  112.512 1.763 114.168 1.811 ;
     RECT  115.2 1.763 126.912 1.811 ;
     RECT  127.92 1.763 133.704 1.811 ;
     RECT  135.312 1.763 140.328 1.811 ;
     RECT  1.344 1.811 5.304 1.859 ;
     RECT  7.8 1.811 8.904 1.859 ;
     RECT  9.936 1.811 14.472 1.859 ;
     RECT  25.728 1.811 26.136 1.859 ;
     RECT  27.504 1.811 28.248 1.859 ;
     RECT  29.4 1.811 30.408 1.859 ;
     RECT  36.48 1.811 36.504 1.859 ;
     RECT  88.128 1.763 89.928 1.859 ;
     RECT  91.536 1.811 92.088 1.859 ;
     RECT  95.664 1.811 101.4 1.859 ;
     RECT  108.768 1.811 111.48 1.859 ;
     RECT  112.512 1.811 113.976 1.859 ;
     RECT  115.8 1.811 118.44 1.859 ;
     RECT  119.52 1.811 123.48 1.859 ;
     RECT  125.088 1.811 126.912 1.859 ;
     RECT  135.456 1.811 138.168 1.859 ;
     RECT  11.376 1.859 14.472 1.907 ;
     RECT  28.08 1.859 28.104 1.907 ;
     RECT  32.736 1.811 35.448 1.907 ;
     RECT  11.376 1.907 14.28 1.955 ;
     RECT  40.2 2.137 40.32 2.151 ;
     RECT  45.6 2.137 45.72 2.151 ;
     RECT  51 2.137 51.12 2.151 ;
     RECT  56.4 2.137 56.52 2.151 ;
     RECT  61.8 2.137 61.92 2.151 ;
     RECT  67.2 2.137 67.32 2.151 ;
     RECT  72.6 2.137 72.72 2.151 ;
     RECT  78 2.137 78.12 2.151 ;
     RECT  83.4 2.137 83.52 2.151 ;
     RECT  1.344 1.859 4.392 2.195 ;
     RECT  32.736 1.907 32.76 2.195 ;
     RECT  33.984 1.907 35.448 2.195 ;
     RECT  97.728 1.859 98.568 2.195 ;
     RECT  102.48 1.811 102.696 2.195 ;
     RECT  104.448 1.811 107.688 2.195 ;
     RECT  108.768 1.859 110.712 2.195 ;
     RECT  119.52 1.859 119.544 2.195 ;
     RECT  128.64 1.811 129.912 2.195 ;
     RECT  131.52 1.811 133.704 2.195 ;
     RECT  99.6 1.859 101.4 2.243 ;
     RECT  136.56 1.859 138.168 2.243 ;
     RECT  7.8 1.859 8.712 2.291 ;
     RECT  11.376 1.955 14.088 2.291 ;
     RECT  26.112 1.859 26.136 2.291 ;
     RECT  34.176 2.195 35.448 2.291 ;
     RECT  95.664 1.859 96.408 2.291 ;
     RECT  102.672 2.195 102.696 2.291 ;
     RECT  113.952 1.859 113.976 2.291 ;
     RECT  118.08 1.859 118.44 2.291 ;
     RECT  120.576 1.859 123.288 2.291 ;
     RECT  128.832 2.195 129.384 2.291 ;
     RECT  11.376 2.291 13.752 2.339 ;
     RECT  15.504 1.811 19.656 2.339 ;
     RECT  96 2.291 96.408 2.339 ;
     RECT  97.728 2.195 98.184 2.339 ;
     RECT  104.448 2.195 107.352 2.339 ;
     RECT  118.08 2.291 118.104 2.339 ;
     RECT  120.96 2.291 122.04 2.339 ;
     RECT  128.832 2.291 128.856 2.339 ;
     RECT  12.672 2.339 13.752 2.387 ;
     RECT  139.584 1.811 140.328 2.773 ;
     RECT  141.792 2.725 141.816 2.773 ;
     RECT  139.584 2.773 141.816 2.821 ;
     RECT  1.344 2.195 4.248 2.915 ;
     RECT  16.032 2.339 19.656 2.915 ;
     RECT  22.512 1.811 22.872 2.915 ;
     RECT  88.464 1.859 89.928 2.915 ;
     RECT  101.376 2.243 101.4 2.915 ;
     RECT  121.2 2.339 122.04 2.915 ;
     RECT  123.264 2.291 123.288 2.915 ;
     RECT  126.48 1.859 126.912 2.915 ;
     RECT  132 2.195 133.704 2.915 ;
     RECT  137.28 2.243 138.168 2.915 ;
     RECT  137.4 2.915 138.168 3.301 ;
     RECT  139.248 2.821 141.816 3.301 ;
     RECT  29.4 1.859 29.712 3.349 ;
     RECT  34.8 2.291 35.448 3.349 ;
     RECT  115.8 1.859 116.112 3.349 ;
     RECT  1.536 2.915 3.624 3.443 ;
     RECT  16.032 2.915 16.44 3.443 ;
     RECT  17.568 2.915 18.912 3.443 ;
     RECT  34.416 3.349 35.448 3.443 ;
     RECT  103.104 3.109 103.128 3.443 ;
     RECT  104.64 2.339 106.44 3.443 ;
     RECT  12.672 2.387 13.608 3.491 ;
     RECT  126.6 2.915 126.912 3.685 ;
     RECT  7.8 2.291 8.376 3.733 ;
     RECT  11.376 2.339 11.4 3.733 ;
     RECT  97.728 2.339 97.848 3.733 ;
     RECT  132 2.915 132.6 3.733 ;
     RECT  16.032 3.443 16.056 3.827 ;
     RECT  34.416 3.443 35.304 3.877 ;
     RECT  99.6 2.243 99.912 3.877 ;
     RECT  115.8 3.349 116.232 3.877 ;
     RECT  137.4 3.301 141.816 3.877 ;
     RECT  24 1.811 24.312 3.925 ;
     RECT  97.728 3.733 97.944 3.925 ;
     RECT  99.36 3.877 100.872 3.925 ;
     RECT  104.64 3.443 105.432 3.925 ;
     RECT  121.2 2.915 121.608 3.925 ;
     RECT  128.256 3.733 128.28 3.925 ;
     RECT  131.856 3.733 132.6 3.925 ;
     RECT  10.896 3.733 11.4 4.019 ;
     RECT  31.344 3.685 31.368 4.117 ;
     RECT  94.2 1.811 94.512 4.117 ;
     RECT  10.896 4.019 10.92 4.261 ;
     RECT  117.312 3.925 117.336 4.261 ;
     RECT  128.256 3.925 128.424 4.261 ;
     RECT  102.624 3.541 102.648 4.355 ;
     RECT  131.76 3.925 132.6 4.405 ;
     RECT  7.632 3.733 8.376 4.453 ;
     RECT  131.76 4.405 133.56 4.453 ;
     RECT  6.528 3.925 6.552 4.501 ;
     RECT  7.536 4.453 8.376 4.501 ;
     RECT  12.672 3.491 13.512 4.501 ;
     RECT  126.6 3.685 127.08 4.501 ;
     RECT  128.256 4.261 128.76 4.501 ;
     RECT  131.184 4.453 133.56 4.501 ;
     RECT  135.6 2.821 135.624 4.501 ;
     RECT  136.896 3.877 141.816 4.501 ;
     RECT  126.6 4.501 128.76 4.549 ;
     RECT  117.312 4.261 117.96 4.643 ;
     RECT  104.544 3.925 105.432 4.883 ;
     RECT  121.008 3.925 121.608 4.883 ;
     RECT  17.568 3.443 17.592 4.933 ;
     RECT  18.6 3.443 18.912 4.933 ;
     RECT  2.4 3.443 3.624 5.077 ;
     RECT  125.952 4.549 128.76 5.077 ;
     RECT  17.568 4.933 18.912 5.123 ;
     RECT  20.544 3.685 20.568 5.123 ;
     RECT  29.4 3.349 30.024 5.171 ;
     RECT  97.728 3.925 98.28 5.171 ;
     RECT  123.072 3.925 123.096 5.171 ;
     RECT  6.528 4.501 8.376 5.173 ;
     RECT  121.008 4.883 121.512 5.173 ;
     RECT  37.056 4.501 37.08 5.219 ;
     RECT  92.304 3.397 92.328 5.219 ;
     RECT  117.936 4.643 117.96 5.219 ;
     RECT  135.6 4.501 141.816 5.219 ;
     RECT  29.4 5.171 29.832 5.317 ;
     RECT  23.04 3.925 24.312 5.365 ;
     RECT  135.6 5.219 135.624 5.365 ;
     RECT  31.344 4.117 31.464 5.413 ;
     RECT  33.168 4.261 33.192 5.413 ;
     RECT  31.344 5.413 33.192 5.459 ;
     RECT  125.952 5.077 129.192 5.459 ;
     RECT  113.568 3.925 114.024 5.461 ;
     RECT  130.608 4.501 133.56 5.461 ;
     RECT  12.624 4.501 13.512 5.557 ;
     RECT  113.472 5.461 114.024 5.557 ;
     RECT  115.296 3.877 116.232 5.557 ;
     RECT  14.832 5.077 14.856 5.605 ;
     RECT  96.096 5.077 96.12 5.605 ;
     RECT  113.472 5.557 116.232 5.605 ;
     RECT  113.04 5.605 116.232 5.699 ;
     RECT  5.664 5.173 8.376 5.747 ;
     RECT  12.528 5.557 13.512 5.747 ;
     RECT  31.44 5.459 32.52 5.747 ;
     RECT  87.792 4.549 87.816 5.747 ;
     RECT  111.84 5.173 111.864 5.747 ;
     RECT  120.48 5.173 121.512 5.747 ;
     RECT  130.608 5.461 134.232 5.747 ;
     RECT  18.48 5.123 18.912 5.749 ;
     RECT  94.032 4.117 94.512 5.843 ;
     RECT  125.952 5.459 128.424 5.939 ;
     RECT  123.696 5.365 123.72 6.083 ;
     RECT  107.472 6.037 107.496 6.085 ;
     RECT  108.864 4.213 108.888 6.085 ;
     RECT  34.224 3.877 35.304 6.227 ;
     RECT  18.48 5.749 19.368 6.275 ;
     RECT  6.528 5.747 8.376 6.323 ;
     RECT  14.592 5.605 14.856 6.323 ;
     RECT  16.992 5.461 17.016 6.323 ;
     RECT  88.8 2.915 89.688 6.323 ;
     RECT  91.152 5.077 91.176 6.323 ;
     RECT  94.08 5.843 94.512 6.371 ;
     RECT  96.048 5.605 96.12 6.373 ;
     RECT  97.92 5.171 98.28 6.373 ;
     RECT  99.36 3.925 101.256 6.373 ;
     RECT  95.76 6.373 96.12 6.419 ;
     RECT  2.4 5.077 4.2 6.469 ;
     RECT  31.44 5.747 31.464 6.563 ;
     RECT  97.92 6.373 101.256 6.563 ;
     RECT  32.496 5.747 32.52 6.709 ;
     RECT  2.4 6.469 4.68 6.803 ;
     RECT  12.576 5.747 13.512 6.805 ;
     RECT  113.04 5.699 113.592 6.851 ;
     RECT  125.952 5.939 126.912 6.851 ;
     RECT  131.184 5.747 134.232 6.851 ;
     RECT  18.6 6.275 19.368 6.899 ;
     RECT  99.36 6.563 101.256 6.899 ;
     RECT  110.016 2.195 110.712 6.899 ;
     RECT  117.264 6.037 117.288 6.899 ;
     RECT  131.184 6.851 132.6 6.899 ;
     RECT  134.208 6.851 134.232 6.899 ;
     RECT  135.216 5.365 135.624 6.899 ;
     RECT  6.528 6.323 8.112 6.947 ;
     RECT  95.76 6.419 95.784 6.947 ;
     RECT  107.472 6.085 108.888 6.947 ;
     RECT  10.224 4.261 10.92 6.995 ;
     RECT  29.088 5.317 29.832 7.043 ;
     RECT  14.832 6.323 14.856 7.091 ;
     RECT  31.872 6.709 32.52 7.187 ;
     RECT  6.528 6.947 6.552 7.475 ;
     RECT  23.04 5.365 25.08 7.475 ;
     RECT  32.496 7.187 32.52 7.475 ;
     RECT  107.472 6.947 108.312 7.475 ;
     RECT  135.216 6.899 135.336 7.763 ;
     RECT  104.544 4.883 105.312 8.003 ;
     RECT  115.296 5.699 116.232 8.003 ;
     RECT  10.896 6.995 10.92 8.579 ;
     RECT  34.224 6.227 35.208 8.579 ;
     RECT  97.92 6.563 98.28 8.579 ;
     RECT  101.232 6.899 101.256 8.579 ;
     RECT  110.208 6.899 110.712 8.579 ;
     RECT  113.04 6.851 113.496 8.579 ;
     RECT  115.296 8.003 116.112 8.579 ;
     RECT  136.896 5.219 141.816 8.579 ;
     RECT  7.536 6.947 8.112 9.155 ;
     RECT  12.528 6.805 13.512 9.155 ;
     RECT  29.4 7.043 29.832 9.155 ;
     RECT  98.256 8.579 98.28 9.155 ;
     RECT  99.36 6.899 99.912 9.155 ;
     RECT  121.008 5.747 121.512 9.155 ;
     RECT  128.352 5.939 128.424 9.155 ;
     RECT  23.04 7.475 24.312 9.731 ;
     RECT  113.04 8.579 113.064 9.731 ;
     RECT  128.352 9.155 128.376 9.731 ;
     RECT  131.184 6.899 132.312 9.731 ;
     RECT  2.4 6.803 4.632 10.307 ;
     RECT  137.4 8.579 141.816 10.307 ;
     RECT  137.4 10.307 141.336 10.883 ;
     RECT  137.4 10.883 138.264 11.459 ;
     RECT  139.632 10.883 139.656 11.459 ;
     RECT  141.312 10.883 141.336 11.459 ;
     RECT  4.176 10.307 4.632 11.509 ;
     RECT  4.176 11.509 5.304 11.845 ;
     RECT  2.4 10.307 2.712 11.893 ;
     RECT  4.032 11.845 5.304 11.893 ;
     RECT  107.472 7.475 107.496 11.893 ;
     RECT  2.4 11.893 5.304 12.035 ;
     RECT  13.104 9.155 13.512 12.035 ;
     RECT  107.424 11.893 107.496 12.035 ;
     RECT  135.216 7.763 135.24 12.035 ;
     RECT  5.28 12.035 5.304 12.517 ;
     RECT  36.72 7.141 36.744 12.517 ;
     RECT  36.72 12.517 36.984 12.563 ;
     RECT  72.6 2.151 72.912 13.045 ;
     RECT  36.96 12.563 36.984 13.283 ;
     RECT  140.4 11.941 140.424 16.981 ;
     RECT  140.208 16.981 141 17.077 ;
     RECT  137.4 11.459 137.712 18.037 ;
     RECT  118.992 17.461 119.016 18.181 ;
     RECT  137.4 18.037 137.832 18.181 ;
     RECT  137.4 18.181 138.792 18.661 ;
     RECT  137.4 18.661 138.984 18.803 ;
     RECT  5.28 12.517 5.4 18.805 ;
     RECT  22.656 17.077 22.68 18.851 ;
     RECT  28.032 17.077 28.056 18.851 ;
     RECT  118.992 18.181 119.976 18.851 ;
     RECT  140.208 17.077 141.096 18.851 ;
     RECT  13.2 12.035 13.512 19.093 ;
     RECT  132 9.731 132.312 19.333 ;
     RECT  5.28 18.805 5.496 19.379 ;
     RECT  13.2 19.093 13.704 19.621 ;
     RECT  6.768 19.669 6.792 19.909 ;
     RECT  7.8 9.155 8.112 19.909 ;
     RECT  126.6 6.851 126.912 19.909 ;
     RECT  129.072 19.333 129.096 19.955 ;
     RECT  2.4 12.035 4.056 20.003 ;
     RECT  5.28 19.379 5.4 20.003 ;
     RECT  13.056 19.621 13.704 20.003 ;
     RECT  22.848 19.333 22.872 20.003 ;
     RECT  119.232 18.851 119.976 20.003 ;
     RECT  5.28 20.003 5.304 20.051 ;
     RECT  94.2 6.371 94.512 20.197 ;
     RECT  105 8.003 105.312 20.197 ;
     RECT  10.848 20.005 10.872 20.437 ;
     RECT  29.4 9.155 29.712 20.437 ;
     RECT  121.2 9.155 121.512 20.437 ;
     RECT  138.768 18.803 138.984 20.437 ;
     RECT  135.552 19.141 135.576 20.483 ;
     RECT  125.376 18.949 125.4 20.485 ;
     RECT  126.6 19.909 127.656 20.485 ;
     RECT  140.208 18.851 141 20.485 ;
     RECT  13.2 20.003 13.704 20.579 ;
     RECT  20.544 19.909 20.568 20.579 ;
     RECT  102.576 19.909 102.6 20.579 ;
     RECT  110.4 8.579 110.712 20.581 ;
     RECT  36.72 13.621 36.744 20.627 ;
     RECT  92.016 19.909 92.04 20.627 ;
     RECT  107.424 12.035 107.448 20.627 ;
     RECT  131.664 19.333 132.312 20.675 ;
     RECT  6.768 19.909 8.112 20.723 ;
     RECT  30.72 19.813 30.744 20.723 ;
     RECT  121.056 20.437 121.512 20.725 ;
     RECT  6.768 20.723 6.792 20.867 ;
     RECT  125.376 20.485 125.448 20.867 ;
     RECT  18.6 6.899 18.912 20.965 ;
     RECT  94.2 20.197 94.68 20.965 ;
     RECT  125.424 20.867 125.448 20.965 ;
     RECT  126.6 20.485 127.944 20.965 ;
     RECT  2.4 20.003 3.624 21.061 ;
     RECT  7.8 20.723 8.112 21.061 ;
     RECT  137.4 18.803 137.712 21.061 ;
     RECT  138.768 20.437 139.224 21.061 ;
     RECT  2.304 21.061 3.624 21.155 ;
     RECT  94.08 20.965 94.68 21.155 ;
     RECT  96.672 19.669 96.696 21.155 ;
     RECT  97.728 20.197 97.752 21.155 ;
     RECT  110.4 20.581 111.192 21.155 ;
     RECT  32.016 19.909 32.04 21.203 ;
     RECT  137.4 21.061 139.224 21.253 ;
     RECT  10.512 20.437 10.872 21.395 ;
     RECT  17.28 19.333 17.304 21.395 ;
     RECT  1.152 20.725 1.176 21.541 ;
     RECT  2.304 21.155 3.384 21.541 ;
     RECT  4.608 20.437 4.632 21.541 ;
     RECT  29.28 20.437 29.712 21.541 ;
     RECT  34.8 8.579 35.112 21.541 ;
     RECT  104.88 20.197 105.312 21.541 ;
     RECT  136.896 21.253 139.224 21.541 ;
     RECT  121.056 20.725 122.712 21.635 ;
     RECT  99.6 9.155 99.912 21.637 ;
     RECT  131.904 20.675 132.312 21.637 ;
     RECT  134.592 21.541 134.616 21.637 ;
     RECT  135.984 21.541 139.224 21.637 ;
     RECT  11.904 20.725 11.928 21.683 ;
     RECT  119.52 20.003 119.544 21.683 ;
     RECT  13.2 20.579 13.512 21.685 ;
     RECT  131.904 21.637 132.792 21.781 ;
     RECT  125.424 20.965 127.944 22.067 ;
     RECT  24 9.731 24.312 22.165 ;
     RECT  34.8 21.541 36.024 22.211 ;
     RECT  88.8 6.323 89.112 22.213 ;
     RECT  140.208 20.485 141.24 22.259 ;
     RECT  104.88 21.541 106.392 22.355 ;
     RECT  94.08 21.155 94.512 22.501 ;
     RECT  1.152 21.541 3.384 22.741 ;
     RECT  4.608 21.541 5.112 22.741 ;
     RECT  24 22.165 24.408 22.741 ;
     RECT  34.8 22.211 35.112 22.789 ;
     RECT  72.096 13.045 72.912 22.789 ;
     RECT  140.688 22.259 141.24 22.789 ;
     RECT  13.2 21.685 13.656 22.885 ;
     RECT  1.152 22.741 3.528 23.365 ;
     RECT  4.608 22.741 5.496 23.365 ;
     RECT  7.8 21.061 8.808 23.365 ;
     RECT  10.512 21.395 10.536 23.365 ;
     RECT  13.104 22.885 13.656 23.365 ;
     RECT  18.6 20.965 19.752 23.365 ;
     RECT  22.128 22.597 22.152 23.365 ;
     RECT  24 22.741 25.224 23.365 ;
     RECT  26.64 20.965 26.664 23.365 ;
     RECT  29.184 21.541 29.712 23.365 ;
     RECT  33.984 22.789 35.112 23.365 ;
     RECT  88.8 22.213 89.4 23.365 ;
     RECT  94.032 22.501 94.512 23.365 ;
     RECT  96 22.741 96.024 23.365 ;
     RECT  99.264 21.637 99.912 23.365 ;
     RECT  104.88 22.355 105.312 23.365 ;
     RECT  106.368 22.355 106.392 23.365 ;
     RECT  110.4 21.155 110.712 23.365 ;
     RECT  115.8 8.579 116.112 23.365 ;
     RECT  121.056 21.635 122.184 23.365 ;
     RECT  126.336 22.067 127.944 23.365 ;
     RECT  131.856 21.781 132.792 23.365 ;
     RECT  134.592 21.637 139.224 23.365 ;
     RECT  140.688 22.789 142.152 23.365 ;
     RECT  21.408 23.365 26.664 23.413 ;
     RECT  27.696 23.365 30.072 23.413 ;
     RECT  112.704 23.365 112.728 23.413 ;
     RECT  120.768 23.365 125.112 23.413 ;
     RECT  126.144 23.365 133.176 23.413 ;
     RECT  15.696 23.365 15.912 23.461 ;
     RECT  104.064 23.365 111.48 23.461 ;
     RECT  112.512 23.413 112.728 23.461 ;
     RECT  21.072 23.413 30.072 23.557 ;
     RECT  31.296 23.365 37.608 23.557 ;
     RECT  88.8 23.365 92.808 23.701 ;
     RECT  40.2 2.151 40.512 23.769 ;
     RECT  45.6 2.151 45.912 23.769 ;
     RECT  51 2.151 51.312 23.769 ;
     RECT  56.4 2.151 56.712 23.769 ;
     RECT  61.8 2.151 62.112 23.769 ;
     RECT  67.2 2.151 67.512 23.769 ;
     RECT  72 22.789 72.912 23.769 ;
     RECT  78 2.151 78.312 23.769 ;
     RECT  83.4 2.151 83.712 23.769 ;
     RECT  40.2 23.769 40.32 23.783 ;
     RECT  45.6 23.769 45.72 23.783 ;
     RECT  51 23.769 51.12 23.783 ;
     RECT  56.4 23.769 56.52 23.783 ;
     RECT  61.8 23.769 61.92 23.783 ;
     RECT  67.2 23.769 67.32 23.783 ;
     RECT  72 23.769 72.72 23.783 ;
     RECT  78 23.769 78.12 23.783 ;
     RECT  83.4 23.769 83.52 23.783 ;
     RECT  93.84 23.365 103.032 23.797 ;
     RECT  104.064 23.461 112.728 23.797 ;
     RECT  114.48 23.365 118.44 23.797 ;
     RECT  119.52 23.365 119.544 23.797 ;
     RECT  1.152 23.365 8.808 23.845 ;
     RECT  9.936 23.365 14.472 23.845 ;
     RECT  15.504 23.461 15.912 23.845 ;
     RECT  16.944 23.365 19.752 23.845 ;
     RECT  88.464 23.701 92.808 23.845 ;
     RECT  93.84 23.797 112.728 23.845 ;
     RECT  114.48 23.797 119.544 23.845 ;
     RECT  1.152 23.845 19.752 23.893 ;
     RECT  21.072 23.557 37.608 23.893 ;
     RECT  88.464 23.845 119.544 23.893 ;
     RECT  120.768 23.413 133.176 23.893 ;
     RECT  134.592 23.365 142.488 23.893 ;
     RECT  72 23.783 72.024 25.139 ;
     RECT  143.904 25.093 143.928 25.141 ;
     RECT  88.32 23.893 142.488 25.765 ;
     RECT  143.52 25.141 143.928 25.765 ;
     RECT  1.008 23.893 37.944 25.872 ;
     RECT  88.128 25.765 144.264 25.872 ;
  END
END ot_s81_hc_ctfnq0
END LIBRARY
